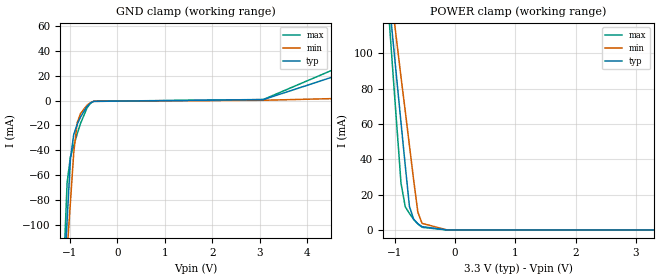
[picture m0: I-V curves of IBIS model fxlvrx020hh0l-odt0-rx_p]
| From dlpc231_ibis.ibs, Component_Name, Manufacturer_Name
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|   Model fxlvrx020hh0l-odt0-rx_p
[Model] fxlvrx020hh0l-odt0-rx_p
Model_type Input
Polarity   Non-Inverting
Vinl =  1.250V
Vinh =  1.250V
C_comp   0.838pF   0.793pF   0.889pF
C_comp_pullup   0.208pF   0.168pF   0.233pF
[Model Spec]
Vinh   1.250V   1.250V   1.250V
Vinl   1.250V   1.250V   1.250V
[Temperature Range]   40.000   0.125k   -40.000
[Voltage Range]   3.300V   2.970V   3.630V
[Pullup Reference]   3.300V   2.970V   3.630V
[Pulldown Reference]   0.0V   0.0V   0.0V
[POWER Clamp Reference]   3.300V   2.970V   3.630V
[GND Clamp Reference]   0.0V   0.0V   0.0V
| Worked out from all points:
|   GND clamp passes 1 mA (typ) near -0.52 V on its own axis
|   POWER clamp passes 1 mA (typ) near -0.49 V on its own axis
[GND_clamp]
|Voltage   I(typ)   I(min)   I(max)
-3.3V     -1.777A    -1.443A    -2.296A
-1.13V    -147.3mA   -160.7mA   -133.1mA
-1.06V    -96.46mA   -121mA     -65.94mA
-990mV    -46.56mA   -81.44mA   -45.11mA
-920mV    -27.23mA   -41.76mA   -36.16mA
-850mV    -19.43mA   -18.17mA   -27.05mA
-780mV    -13.39mA   -10.64mA   -18.6mA
-640mV    -4.604mA   -3.691mA   -5.833mA
-570mV    -2.048mA   -1.757mA   -2.243mA
-500mV    -679.6uA   -643.4uA   -592.3uA
3.07V     723uA      208.1uA    801.7uA
6.58V     44.35mA    3.413mA    57.79mA
[POWER_clamp]
|Voltage   I(typ)   I(min)   I(max)
-3.28V    1.18A      1.008A     1.441A
-1.18V    159.7mA    167.6mA    159.1mA
-1.11V    134.5mA    146.7mA    125.3mA
-1.04V    109.6mA    126.2mA    91.85mA
-900mV    60.75mA    86.59mA    26.55mA
-830mV    36.72mA    67.43mA    13.23mA
-760mV    13.35mA    47.84mA    9.33mA
-690mV    6.049mA    28.33mA    6.066mA
-620mV    3.518mA    10.04mA    3.397mA
-550mV    1.873mA    3.726mA    1.494mA
-130mV    0A         0A         0A
3.3V      0A         0A         0A
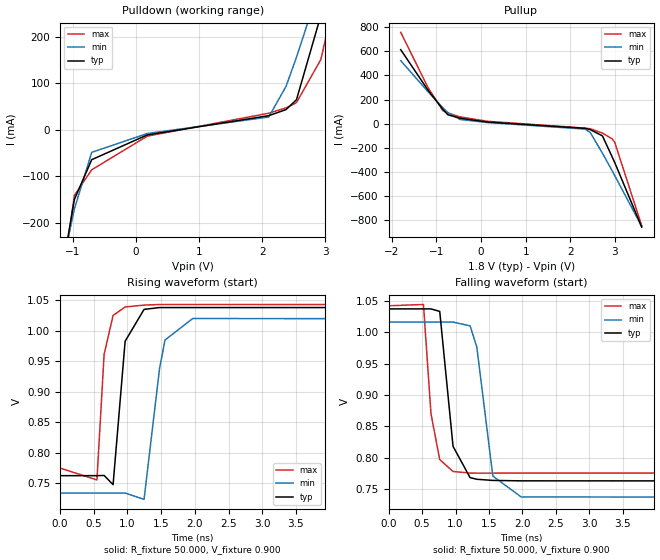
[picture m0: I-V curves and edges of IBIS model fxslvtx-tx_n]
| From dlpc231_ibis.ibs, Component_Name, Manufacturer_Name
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|   Model fxslvtx030hh0l-tx_n
[Model] fxslvtx-tx_n
Model_type Output
Polarity   Inverting
Vmeas =  0.900V
C_comp   4.596pF   4.576pF   4.628pF
C_comp_pullup   0.720pF   0.673pF   0.780pF
C_comp_pulldown   0.529pF   0.517pF   0.543pF
[Model Spec]
Vmeas   0.900V   0.900V   0.900V
[Temperature Range]   40.000   0.125k   -40.000
[Voltage Range]   1.800V   1.620V   1.980V
[Pullup Reference]   1.800V   1.620V   1.980V
[Pulldown Reference]   0.0V   0.0V   0.0V
[POWER Clamp Reference]   1.800V   1.620V   1.980V
[GND Clamp Reference]   0.0V   0.0V   0.0V
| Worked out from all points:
|   slope of the pulldown table from 0 to 0.27 V, typ, clamps not added: 26.4 ohm
|   slope of the pullup table from 0 to 0.27 V, typ, clamps not added: 26.3 ohm
|   rising waveform, R_fixture 50.000, V_fixture 0.900: 20-80 % time 115ps typ, 164ps min, 93.6ps max; typ from 0.763 V to 1.04 V
|   falling waveform, R_fixture 50.000, V_fixture 0.900: 20-80 % time 133ps typ, 178ps min, 123ps max; typ from 1.04 V to 0.763 V
[Pulldown]
|Voltage   I(typ)   I(min)   I(max)
-1.8V     -861.9mA   -731mA     -1.071A
-1.195V   -325.7mA   -310mA     -357.2mA
-975mV    -150.4mA   -170.7mA   -141.6mA
-700mV    -64.49mA   -48.72mA   -86.29mA
180mV     -11.16mA   -8.121mA   -13.74mA
2.105V    30.29mA    27.42mA    35.56mA
2.38V     43.45mA    93.62mA    47.16mA
2.545V    64.78mA    156.3mA    58.49mA
2.93V     245.8mA    316.5mA    151.1mA
3.095V    336.1mA    386mA      248.2mA
3.205V    397mA      432.4mA    324.4mA
3.6V      615.2mA    600.8mA    624mA
[Pullup]
|Voltage   I(typ)   I(min)   I(max)
-1.8V     614.6mA    523.2mA    759mA
-1.185V   275.8mA    263.9mA    296.7mA
-855mV    118.7mA    131.2mA    106.6mA
-745mV    73.55mA    92.03mA    88.76mA
-470mV    44.52mA    34.36mA    55.71mA
135mV     12.86mA    8.96mA     19.38mA
2.335V    -39.86mA   -46.08mA   -37.65mA
2.445V    -49.94mA   -73.94mA   -42.66mA
2.72V     -102.2mA   -245.9mA   -78.84mA
2.94V     -278.6mA   -394mA     -127.7mA
2.995V    -323.5mA   -432.3mA   -155.1mA
3.6V      -861.5mA   -855.2mA   -849.2mA
[Ramp]
| variable   typ   min   max
dV/dt_r   0.165/0.110n   0.169/0.150n   0.160/94.189p
dV/dt_f   0.165/0.143n   0.169/0.203n   0.160/0.123n
R_load = 50.000
[Rising Waveform]
R_fixture= 50.000
V_fixture= 0.900
V_fixture_min= 0.875
V_fixture_max= 0.908
|time   V(typ)   V(min)   V(max)
0s        762.5mV    734mV      774.9mV
546ps     762.5mV    734mV      755.5mV
653ps     762.8mV    734mV      961.4mV
786ps     747.7mV    734mV      1.025V
965ps     982.8mV    734mV      1.039V
1.246ns   1.035V     723.7mV    1.042V
1.476ns   1.038V     938.2mV    1.043V
1.557ns   1.038V     984.7mV    1.043V
1.968ns   1.038V     1.02V      1.043V
50ns      1.037V     1.016V     1.042V
[Falling Waveform]
R_fixture= 50.000
V_fixture= 0.900
V_fixture_min= 0.875
V_fixture_max= 0.908
|time   V(typ)   V(min)   V(max)
0s        1.037V     1.016V     1.042V
520ps     1.037V     1.016V     1.044V
632ps     1.037V     1.016V     870.4mV
763ps     1.033V     1.016V     797.2mV
962ps     818.3mV    1.016V     778.3mV
1.217ns   768.5mV    1.01V      775.8mV
1.317ns   765.9mV    976.4mV    775.7mV
1.557ns   764.1mV    770.9mV    775.7mV
1.981ns   763.4mV    737.8mV    775.8mV
50ns      762.5mV    734mV      774.9mV
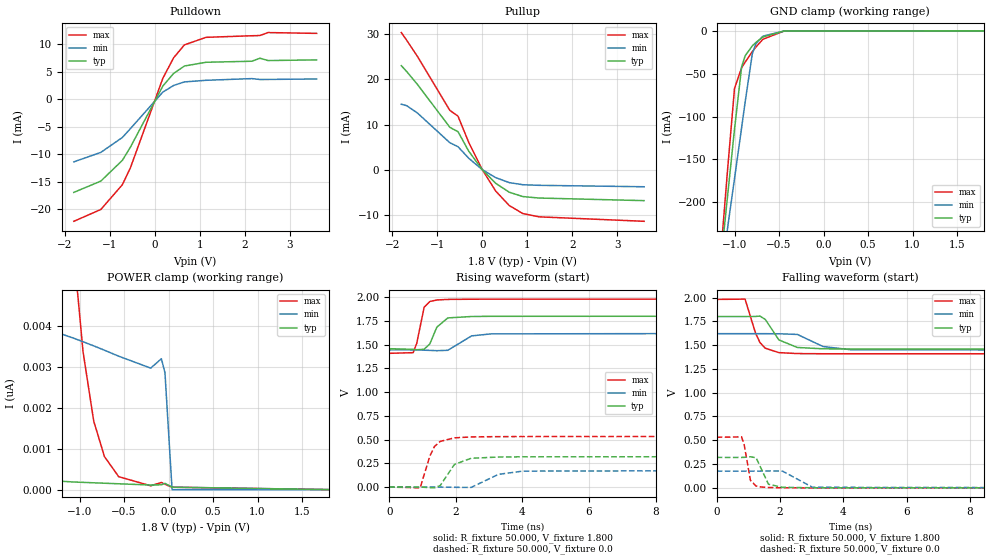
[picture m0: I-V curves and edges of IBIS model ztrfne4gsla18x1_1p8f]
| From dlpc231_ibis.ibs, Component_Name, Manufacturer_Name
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[Model] ztrfne4gsla18x1_1p8f
Model_type I/O
Polarity   Non-Inverting
Enable   Active-High
Vinl =  0.540V
Vinh =  1.260V
Vref = 0.000V
Rref = 0.50k
Cref = 50.00pF
Vmeas = 0.90V
C_comp   2.109pF   2.101pF   2.161pF
C_comp_pullup   0.472pF   0.454pF   0.586pF
C_comp_pulldown   0.472pF   0.454pF   0.586pF
[Temperature Range]   25.000   0.125k   -40.000
[Voltage Range]   1.800V   1.620V   1.980V
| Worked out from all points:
|   slope of the pulldown table from 0 to 0.27 V, typ, clamps not added: 79.5 ohm
|   slope of the pullup table from 0 to 0.27 V, typ, clamps not added: 97.1 ohm
|   GND clamp passes 1 mA (typ) near -0.53 V on its own axis
|   rising waveform, R_fixture 50.000, V_fixture 1.800: 20-80 % time 252ps typ, 379ps min, 183ps max; typ from 1.46 V to 1.8 V
|   rising waveform, R_fixture 50.000, V_fixture 0.0: 20-80 % time 403ps typ, 628ps min, 300ps max; typ from 0 V to 0.32 V
|   falling waveform, R_fixture 50.000, V_fixture 1.800: 20-80 % time 461ps typ, 702ps min, 338ps max; typ from 1.8 V to 1.46 V
|   falling waveform, R_fixture 50.000, V_fixture 0.0: 20-80 % time 230ps typ, 353ps min, 156ps max; typ from 0.32 V to 0 V
[Pulldown]
-1.8V     -16.95mA   -11.39mA   -22.22mA
-1.2V     -14.9mA    -9.67mA    -20.07mA
-720mV    -11.11mA   -6.946mA   -15.55mA
-540mV    -8.689mA   -5.327mA   -12.44mA
180mV     2.424mA    1.317mA    3.83mA
420mV     4.723mA    2.526mA    7.576mA
660mV     6.065mA    3.174mA    9.921mA
1.14V     6.75mA     3.464mA    11.29mA
2.16V     6.938mA    3.775mA    11.58mA
2.34V     7.486mA    3.611mA    11.62mA
2.52V     7.061mA    3.621mA    12.16mA
3.6V      7.184mA    3.708mA    12.01mA
[Pullup]
-1.8V     23.05mA    14.5mA     30.39mA
-1.68V    21.74mA    14.18mA    28.68mA
-1.44V    18.87mA    12.54mA    25.07mA
-720mV    9.367mA    5.957mA    13.13mA
-540mV    8.432mA    5.089mA    11.86mA
-300mV    4.077mA    2.52mA     6.027mA
0V        10.36pA    166.7pA    4.435pA
300mV     -3.041mA   -1.773mA   -4.761mA
600mV     -5mA       -2.872mA   -7.949mA
900mV     -5.961mA   -3.338mA   -9.725mA
1.26V     -6.291mA   -3.475mA   -10.46mA
3.6V      -6.87mA    -3.792mA   -11.45mA
[GND_clamp]
-1.8V     -927mA     -775.7mA   -1.101A
-1.16V    -275.3mA   -291.3mA   -268.1mA
-1.12V    -235.1mA   -261.5mA   -216.5mA
-1.08V    -194.9mA   -231.7mA   -164.9mA
-1V       -114.9mA   -172.5mA   -67.23mA
-920mV    -41.99mA   -112.9mA   -43.08mA
-880mV    -29.06mA   -82.77mA   -36.47mA
-800mV    -17.56mA   -26.87mA   -24.31mA
-760mV    -13.55mA   -15.08mA   -18.89mA
-680mV    -7.158mA   -6.178mA   -9.822mA
-440mV    -133.7uA   -176.5uA   -112.6uA
1.8V      0A         0A         0A
[POWER_clamp]
-1.8V     288.6pA    4.231nA    140.6nA
-1.08V    187.2pA    3.703nA    6.484nA
-1.04V    183.6pA    3.671nA    5.234nA
-960mV    176.5pA    3.605nA    3.359nA
-840mV    166pA      3.504nA    1.668nA
-720mV    155.7pA    3.399nA    806.1pA
-560mV    142pA      3.253nA    315.8pA
-200mV    111.6pA    2.962nA    92.54pA
-80mV     117.3pA    3.191nA    175.1pA
-40mV     151.6pA    2.851nA    129.2pA
40mV      60.08pA    0A         58.67pA
1.8V      0A         0A         0A
[Ramp]
dV/dt_r   0.192/0.402n   0.106/0.635n   0.319/0.301n
dV/dt_f   0.205/0.462n   0.105/0.700n   0.343/0.338n
R_load = 50.000
[Rising Waveform]
R_fixture= 50.000
V_fixture= 1.800
V_fixture_min= 1.620
V_fixture_max= 1.980
0s        1.458V     1.445V     1.409V
719ps     1.451V     1.445V     1.416V
829ps     1.447V     1.445V     1.516V
1.049ns   1.452V     1.442V     1.895V
1.22ns    1.508V     1.44V      1.955V
1.431ns   1.685V     1.437V     1.971V
1.761ns   1.782V     1.441V     1.977V
2.476ns   1.797V     1.593V     1.979V
3.066ns   1.799V     1.614V     1.98V
15ns      1.8V       1.62V      1.98V
[Rising Waveform]
R_fixture= 50.000
V_fixture= 0.0
V_fixture_min= 0.0
V_fixture_max= 0.0
0s        0V         0V         0V
930ps     -62.39uV   300.9uV    -8.214mV
1.22ns    -5.677mV   323.3uV    325.7mV
1.359ns   -8.367mV   274.3uV    427.2mV
1.531ns   15.77mV    79.15uV    481.1mV
1.96ns    238.9mV    -2.756mV   518.4mV
2.461ns   303.3mV    -3.894mV   528.2mV
3.281ns   316.4mV    133.8mV    531.5mV
4.01ns    318.9mV    168mV      531.9mV
15ns      320mV      176.1mV    532mV
[Falling Waveform]
R_fixture= 50.000
V_fixture= 1.800
V_fixture_min= 1.620
V_fixture_max= 1.980
0s        1.8V       1.62V      1.98V
896ps     1.8V       1.62V      1.983V
1.224ns   1.801V     1.62V      1.628V
1.364ns   1.805V     1.62V      1.528V
1.534ns   1.77V      1.62V      1.467V
1.965ns   1.554V     1.619V     1.421V
2.548ns   1.475V     1.612V     1.411V
3.358ns   1.461V     1.485V     1.409V
4.217ns   1.459V     1.452V     1.409V
15ns      1.458V     1.445V     1.409V
[Falling Waveform]
R_fixture= 50.000
V_fixture= 0.0
V_fixture_min= 0.0
V_fixture_max= 0.0
0s        320mV      176.1mV    532mV
785ps     319.9mV    176.1mV    535.5mV
866ps     320.4mV    176.1mV    458.1mV
1.066ns   326.6mV    176mV      79.15mV
1.244ns   316.4mV    176mV      18.67mV
1.394ns   209.6mV    176.2mV    9.401mV
1.635ns   38.02mV    177.8mV    3.778mV
2.076ns   6.113mV    176.3mV    834.5uV
3.028ns   788.1uV    6.018mV    40.72uV
15ns      0V         0V         0V
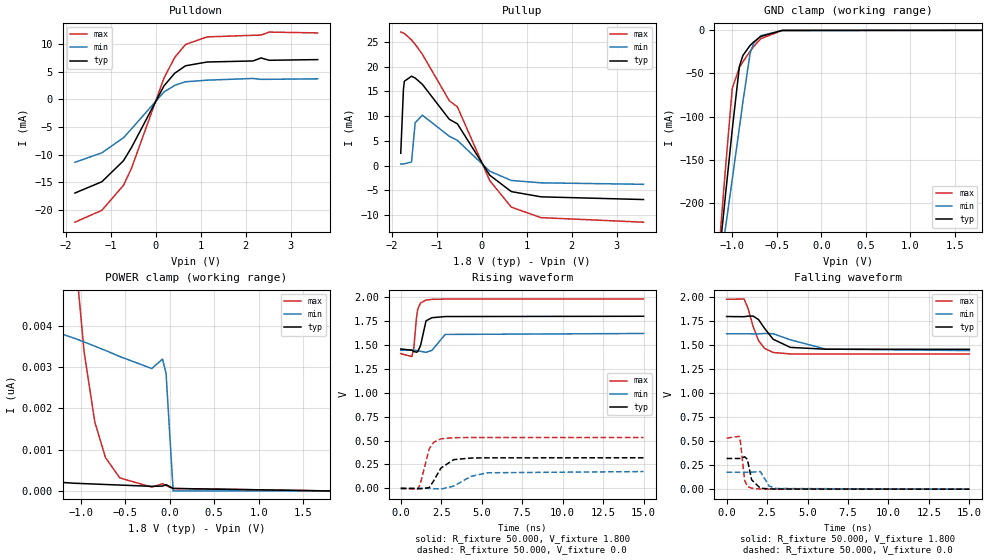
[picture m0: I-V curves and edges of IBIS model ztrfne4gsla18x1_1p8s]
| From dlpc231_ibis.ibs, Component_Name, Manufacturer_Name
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| Model ztrfne4gsla18x1_1p8s
[Model] ztrfne4gsla18x1_1p8s
Model_type I/O
Polarity   Non-Inverting
Enable   Active-High
Vinl =  0.540V
Vinh =  1.260V
Vref = 0.000V
Rref = 0.50k
Cref = 50.00pF
Vmeas = 0.90V
C_comp   2.095pF   2.092pF   2.148pF
C_comp_pullup   0.469pF   0.448pF   0.594pF
C_comp_pulldown   0.469pF   0.448pF   0.594pF
[Temperature Range]   25.000   0.125k   -40.000
[Voltage Range]   1.800V   1.620V   1.980V
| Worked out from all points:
|   slope of the pulldown table from 0 to 0.27 V, typ, clamps not added: 79.5 ohm
|   slope of the pullup table from 0 to 0.27 V, typ, clamps not added: 97.1 ohm
|   GND clamp passes 1 mA (typ) near -0.53 V on its own axis
|   rising waveform, R_fixture 50.000, V_fixture 1.800: 20-80 % time 240ps typ, 347ps min, 196ps max; typ from 1.46 V to 1.8 V
|   rising waveform, R_fixture 50.000, V_fixture 0.0: 20-80 % time 734ps typ, 1.24ns min, 504ps max; typ from 0 V to 0.32 V
|   falling waveform, R_fixture 50.000, V_fixture 1.800: 20-80 % time 1.02ns typ, 1.64ns min, 706ps max; typ from 1.8 V to 1.46 V
|   falling waveform, R_fixture 50.000, V_fixture 0.0: 20-80 % time 253ps typ, 354ps min, 201ps max; typ from 0.32 V to 0 V
[Pulldown]
-1.8V     -16.95mA   -11.39mA   -22.22mA
-1.2V     -14.9mA    -9.67mA    -20.07mA
-720mV    -11.11mA   -6.946mA   -15.55mA
-540mV    -8.689mA   -5.327mA   -12.44mA
180mV     2.424mA    1.317mA    3.83mA
420mV     4.723mA    2.526mA    7.576mA
660mV     6.065mA    3.174mA    9.921mA
1.14V     6.75mA     3.464mA    11.29mA
2.16V     6.938mA    3.775mA    11.58mA
2.34V     7.486mA    3.611mA    11.62mA
2.52V     7.061mA    3.621mA    12.16mA
3.6V      7.184mA    3.708mA    12.01mA
[Pullup]
-1.8V     2.484mA    326.4uA    26.98mA
-1.74V    15.41mA    339.3uA    26.8mA
-1.72V    17.04mA    346.2uA    26.7mA
-1.56V    18.06mA    719.8uA    25.39mA
-1.48V    17.7mA     8.623mA    24.52mA
-1.32V    16.43mA    10.18mA    22.51mA
-720mV    9.35mA     5.922mA    13.11mA
-540mV    8.432mA    5.089mA    11.86mA
180mV     -1.959mA   -1.146mA   -3.055mA
660mV     -5.269mA   -3.014mA   -8.412mA
1.32V     -6.324mA   -3.492mA   -10.53mA
3.6V      -6.87mA    -3.792mA   -11.45mA
[GND_clamp]
-1.8V     -927mA     -775.7mA   -1.101A
-1.16V    -275.3mA   -291.3mA   -268.1mA
-1.12V    -235.1mA   -261.5mA   -216.5mA
-1.08V    -194.9mA   -231.7mA   -164.9mA
-1V       -114.9mA   -172.5mA   -67.23mA
-920mV    -41.99mA   -112.9mA   -43.08mA
-880mV    -29.06mA   -82.77mA   -36.47mA
-800mV    -17.56mA   -26.87mA   -24.31mA
-760mV    -13.55mA   -15.08mA   -18.89mA
-680mV    -7.158mA   -6.178mA   -9.822mA
-440mV    -133.7uA   -176.5uA   -112.6uA
1.8V      0A         0A         0A
[POWER_clamp]
-1.8V     288.6pA    4.231nA    140.6nA
-1.08V    187.2pA    3.703nA    6.484nA
-1.04V    183.6pA    3.671nA    5.234nA
-960mV    176.5pA    3.605nA    3.359nA
-840mV    166pA      3.504nA    1.668nA
-720mV    155.7pA    3.399nA    806.1pA
-560mV    142pA      3.253nA    315.8pA
-200mV    111.6pA    2.962nA    92.54pA
-80mV     117.3pA    3.191nA    175.1pA
-40mV     151.6pA    2.851nA    129.2pA
40mV      60.08pA    0A         58.67pA
1.8V      0A         0A         0A
[Ramp]
dV/dt_r   0.192/0.733n   0.106/1.235n   0.319/0.505n
dV/dt_f   0.205/1.024n   0.105/1.646n   0.343/0.716n
R_load = 50.000
[Rising Waveform]
R_fixture= 50.000
V_fixture= 1.800
V_fixture_min= 1.620
V_fixture_max= 1.980
0s        1.458V     1.445V     1.409V
689ps     1.445V     1.446V     1.379V
810ps     1.433V     1.445V     1.472V
971ps     1.424V     1.442V     1.784V
1.051ns   1.431V     1.44V      1.875V
1.221ns   1.493V     1.434V     1.939V
1.561ns   1.752V     1.423V     1.969V
1.925ns   1.785V     1.443V     1.977V
2.746ns   1.797V     1.61V      1.98V
15ns      1.8V       1.62V      1.98V
[Rising Waveform]
R_fixture= 50.000
V_fixture= 0.0
V_fixture_min= 0.0
V_fixture_max= 0.0
0s        0V         0V         0V
1.07ns    -1.24mV    473.8uV    -8.116mV
1.2ns     -3.926mV   490.6uV    43.61mV
1.761ns   7.701mV    -536.2uV   413.9mV
2.04ns    80.74mV    -2.825mV   482.6mV
2.481ns   212.5mV    -6.943mV   518.4mV
3.276ns   300.8mV    24.34mV    530.3mV
4.346ns   317.5mV    126.1mV    531.9mV
5.366ns   319.6mV    163.2mV    532mV
15ns      320mV      176.1mV    532mV
[Falling Waveform]
R_fixture= 50.000
V_fixture= 1.800
V_fixture_min= 1.620
V_fixture_max= 1.980
0s        1.8V       1.62V      1.98V
1.085ns   1.798V     1.62V      1.982V
1.325ns   1.804V     1.62V      1.885V
1.636ns   1.805V     1.619V     1.697V
1.976ns   1.768V     1.619V     1.549V
2.336ns   1.679V     1.623V     1.469V
2.876ns   1.563V     1.621V     1.425V
3.944ns   1.478V     1.557V     1.41V
6.137ns   1.459V     1.46V      1.409V
15ns      1.458V     1.445V     1.409V
[Falling Waveform]
R_fixture= 50.000
V_fixture= 0.0
V_fixture_min= 0.0
V_fixture_max= 0.0
0s        320mV      176.1mV    532mV
786ps     319.7mV    176.1mV    551.6mV
856ps     320.3mV    176mV      491.5mV
1.116ns   337.7mV    175.9mV    91.16mV
1.284ns   311.5mV    175.9mV    29.33mV
1.548ns   97.14mV    177.3mV    9.31mV
2.088ns   9.682mV    183.3mV    1.632mV
2.618ns   3.218mV    33.57mV    353.7uV
3.054ns   1.41mV     6.768mV    104.6uV
15ns      0V         0V         0V
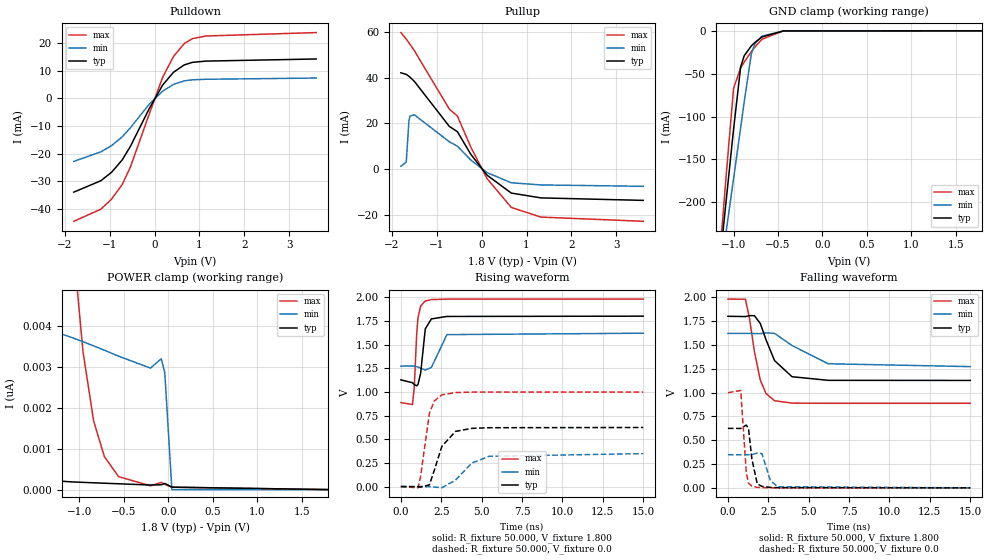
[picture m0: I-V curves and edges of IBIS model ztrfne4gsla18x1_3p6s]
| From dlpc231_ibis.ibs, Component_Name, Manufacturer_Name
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| Model ztrfne4gsla18x1_3p6s
[Model] ztrfne4gsla18x1_3p6s
Model_type I/O
Polarity   Non-Inverting
Enable   Active-High
Vinl =  0.540V
Vinh =  1.260V
Vref = 0.000V
Rref = 0.50k
Cref = 50.00pF
Vmeas = 0.90V
C_comp   2.197pF   2.186pF   2.249pF
C_comp_pullup   0.537pF   0.484pF   0.701pF
C_comp_pulldown   0.537pF   0.484pF   0.701pF
[Temperature Range]   25.000   0.125k   -40.000
[Voltage Range]   1.800V   1.620V   1.980V
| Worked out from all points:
|   slope of the pulldown table from 0 to 0.27 V, typ, clamps not added: 39.8 ohm
|   slope of the pullup table from 0 to 0.27 V, typ, clamps not added: 48.5 ohm
|   GND clamp passes 1 mA (typ) near -0.53 V on its own axis
|   rising waveform, R_fixture 50.000, V_fixture 1.800: 20-80 % time 240ps typ, 349ps min, 194ps max; typ from 1.13 V to 1.8 V
|   rising waveform, R_fixture 50.000, V_fixture 0.0: 20-80 % time 786ps typ, 1.31ns min, 520ps max; typ from 0 V to 0.624 V
|   falling waveform, R_fixture 50.000, V_fixture 1.800: 20-80 % time 1.04ns typ, 1.68ns min, 699ps max; typ from 1.8 V to 1.13 V
|   falling waveform, R_fixture 50.000, V_fixture 0.0: 20-80 % time 271ps typ, 377ps min, 211ps max; typ from 0.624 V to 0 V
[Pulldown]
-1.8V     -33.89mA   -22.78mA   -44.44mA
-1.2V     -29.79mA   -19.34mA   -40.09mA
-960mV    -26.74mA   -17.1mA    -36.45mA
-720mV    -22.21mA   -13.88mA   -31.07mA
-540mV    -17.37mA   -10.64mA   -24.87mA
-120mV    -3.725mA   -2.11mA    -5.686mA
180mV     4.844mA    2.631mA    7.654mA
420mV     9.436mA    5.045mA    15.14mA
660mV     12.11mA    6.338mA    19.82mA
840mV     13.02mA    6.716mA    21.6mA
1.14V     13.48mA    6.915mA    22.56mA
3.6V      14.25mA    7.361mA    23.8mA
[Pullup]
-1.8V     42.07mA    1.185mA    59.67mA
-1.68V    41.39mA    2.996mA    56.77mA
-1.62V    40.54mA    21.06mA    55.18mA
-1.6V     40.21mA    23.09mA    54.64mA
-1.5V     38.34mA    23.7mA     51.81mA
-720mV    18.62mA    11.91mA    26.16mA
-540mV    16.3mA     9.959mA    23.16mA
-240mV    6.367mA    3.893mA    9.494mA
120mV     -2.703mA   -1.584mA   -4.209mA
660mV     -10.54mA   -6.029mA   -16.83mA
1.32V     -12.65mA   -6.984mA   -21.05mA
3.6V      -13.74mA   -7.586mA   -22.89mA
[GND_clamp]
-1.8V     -927mA     -775.7mA   -1.101A
-1.16V    -275.3mA   -291.3mA   -268.1mA
-1.12V    -235.1mA   -261.5mA   -216.5mA
-1.08V    -194.9mA   -231.7mA   -164.9mA
-1V       -114.9mA   -172.5mA   -67.23mA
-920mV    -41.99mA   -112.9mA   -43.08mA
-880mV    -29.06mA   -82.77mA   -36.47mA
-800mV    -17.56mA   -26.87mA   -24.31mA
-760mV    -13.55mA   -15.08mA   -18.89mA
-680mV    -7.158mA   -6.178mA   -9.822mA
-440mV    -133.7uA   -176.5uA   -112.6uA
1.8V      0A         0A         0A
[POWER_clamp]
-1.8V     288.6pA    4.231nA    140.6nA
-1.08V    187.2pA    3.703nA    6.484nA
-1.04V    183.6pA    3.671nA    5.234nA
-960mV    176.5pA    3.605nA    3.359nA
-840mV    166pA      3.504nA    1.668nA
-720mV    155.7pA    3.399nA    806.1pA
-560mV    142pA      3.253nA    315.8pA
-200mV    111.6pA    2.962nA    92.54pA
-80mV     117.3pA    3.191nA    175.1pA
-40mV     151.6pA    2.851nA    129.2pA
40mV      60.08pA    0A         58.67pA
1.8V      0A         0A         0A
[Ramp]
dV/dt_r   0.374/0.786n   0.209/1.315n   0.599/0.525n
dV/dt_f   0.404/1.054n   0.209/1.684n   0.656/0.704n
R_load = 50.000
[Rising Waveform]
R_fixture= 50.000
V_fixture= 1.800
V_fixture_min= 1.620
V_fixture_max= 1.980
0s        1.127V     1.272V     886.8mV
719ps     1.097V     1.274V     866.4mV
829ps     1.077V     1.273V     1.044V
980ps     1.064V     1.267V     1.615V
1.06ns    1.078V     1.262V     1.785V
1.227ns   1.2V       1.25V      1.907V
1.511ns   1.666V     1.231V     1.961V
1.889ns   1.771V     1.258V     1.975V
2.851ns   1.797V     1.605V     1.98V
15ns      1.8V       1.62V      1.98V
[Rising Waveform]
R_fixture= 50.000
V_fixture= 0.0
V_fixture_min= 0.0
V_fixture_max= 0.0
0s        0V         0V         0V
1.069ns   -1.973mV   754.7uV    -13.93mV
1.21ns    -6.548mV   767.8uV    96.37mV
1.769ns   18.15mV    -983.2uV   774.5mV
2.069ns   172mV      -5.19mV    903.6mV
2.54ns    425.4mV    -12.79mV   969.1mV
3.38ns    582.4mV    67.33mV    993.3mV
4.396ns   614.7mV    248.5mV    997.7mV
5.466ns   621.5mV    319.8mV    998.6mV
15ns      623.9mV    347.9mV    998.7mV
[Falling Waveform]
R_fixture= 50.000
V_fixture= 1.800
V_fixture_min= 1.620
V_fixture_max= 1.980
0s        1.8V       1.62V      1.98V
1.085ns   1.797V     1.62V      1.979V
1.335ns   1.807V     1.62V      1.779V
1.644ns   1.806V     1.619V     1.426V
2.006ns   1.724V     1.618V     1.13V
2.354ns   1.556V     1.626V     991.1mV
2.888ns   1.335V     1.621V     914.3mV
3.968ns   1.166V     1.493V     888.9mV
6.208ns   1.128V     1.302V     887mV
15ns      1.127V     1.272V     886.8mV
[Falling Waveform]
R_fixture= 50.000
V_fixture= 0.0
V_fixture_min= 0.0
V_fixture_max= 0.0
0s        623.9mV    347.9mV    998.7mV
795ps     623.4mV    347.8mV    1.022V
1.136ns   658.8mV    347.4mV    163.4mV
1.276ns   620mV      347.4mV    49.4mV
1.484ns   304.3mV    348.7mV    17.99mV
1.814ns   42.55mV    364.8mV    5.362mV
2.107ns   15.25mV    359.1mV    2.102mV
2.627ns   4.855mV    76.61mV    455.8uV
3.087ns   2.001mV    12.32mV    124.7uV
15ns      0V         0V         0V
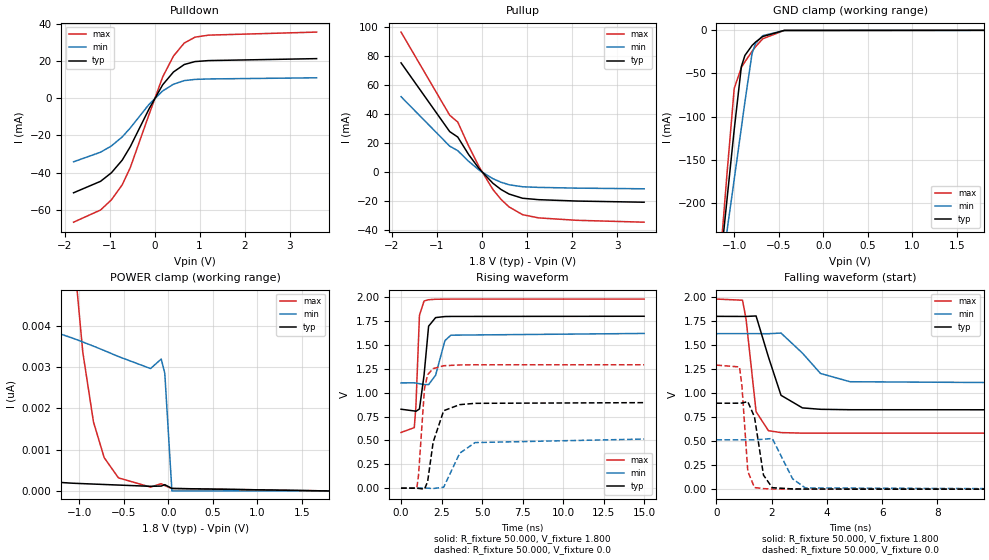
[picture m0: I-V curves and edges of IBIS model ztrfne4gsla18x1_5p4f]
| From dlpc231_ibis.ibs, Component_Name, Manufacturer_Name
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| Model ztrfne4gsla18x1_5p4f
[Model] ztrfne4gsla18x1_5p4f
Model_type I/O
Polarity   Non-Inverting
Enable   Active-High
Vinl =  0.540V
Vinh =  1.260V
Vref = 0.000V
Rref = 0.50k
Cref = 50.00pF
Vmeas = 0.90V
C_comp   2.335pF   2.280pF   2.446pF
C_comp_pullup   0.619pF   0.537pF   0.802pF
C_comp_pulldown   0.619pF   0.537pF   0.802pF
[Temperature Range]   25.000   0.125k   -40.000
[Voltage Range]   1.800V   1.620V   1.980V
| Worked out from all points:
|   slope of the pulldown table from 0 to 0.27 V, typ, clamps not added: 26.5 ohm
|   slope of the pullup table from 0 to 0.27 V, typ, clamps not added: 32.4 ohm
|   GND clamp passes 1 mA (typ) near -0.53 V on its own axis
|   rising waveform, R_fixture 50.000, V_fixture 1.800: 20-80 % time 293ps typ, 469ps min, 181ps max; typ from 0.827 V to 1.8 V
|   rising waveform, R_fixture 50.000, V_fixture 0.0: 20-80 % time 559ps typ, 910ps min, 318ps max; typ from 0 V to 0.895 V
|   falling waveform, R_fixture 50.000, V_fixture 1.800: 20-80 % time 531ps typ, 859ps min, 301ps max; typ from 1.8 V to 0.827 V
|   falling waveform, R_fixture 50.000, V_fixture 0.0: 20-80 % time 278ps typ, 454ps min, 174ps max; typ from 0.895 V to 0 V
[Pulldown]
-1.8V     -50.83mA   -34.16mA   -66.65mA
-1.2V     -44.66mA   -29mA      -60.09mA
-960mV    -40.09mA   -25.65mA   -54.65mA
-720mV    -33.3mA    -20.81mA   -46.59mA
-540mV    -26.05mA   -15.97mA   -37.31mA
-120mV    -5.589mA   -3.166mA   -8.53mA
180mV     7.268mA    3.947mA    11.48mA
420mV     14.16mA    7.57mA     22.72mA
660mV     18.18mA    9.512mA    29.74mA
900mV     19.76mA    10.17mA    32.9mA
1.2V      20.29mA    10.41mA    33.98mA
3.6V      21.34mA    11.03mA    35.62mA
[Pullup]
-1.8V     75.13mA    51.91mA    96.29mA
-720mV    27.93mA    17.95mA    39.19mA
-540mV    24.16mA    14.81mA    34.44mA
-300mV    12.23mA    7.543mA    18.07mA
-60mV     2.221mA    1.318mA    3.411mA
240mV     -7.567mA   -4.42mA    -11.82mA
420mV     -11.85mA   -6.876mA   -18.65mA
600mV     -15mA      -8.618mA   -23.85mA
900mV     -17.89mA   -10.01mA   -29.18mA
1.26V     -18.87mA   -10.43mA   -31.39mA
2.1V      -19.81mA   -10.93mA   -33.04mA
3.6V      -20.62mA   -11.39mA   -34.34mA
[GND_clamp]
-1.8V     -927mA     -775.7mA   -1.101A
-1.16V    -275.3mA   -291.3mA   -268.1mA
-1.12V    -235.1mA   -261.5mA   -216.5mA
-1.08V    -194.9mA   -231.7mA   -164.9mA
-1V       -114.9mA   -172.5mA   -67.23mA
-920mV    -41.99mA   -112.9mA   -43.08mA
-880mV    -29.06mA   -82.77mA   -36.47mA
-800mV    -17.56mA   -26.87mA   -24.31mA
-760mV    -13.55mA   -15.08mA   -18.89mA
-680mV    -7.158mA   -6.178mA   -9.822mA
-440mV    -133.7uA   -176.5uA   -112.6uA
1.8V      0A         0A         0A
[POWER_clamp]
-1.8V     288.6pA    4.231nA    140.6nA
-1.08V    187.2pA    3.703nA    6.484nA
-1.04V    183.6pA    3.671nA    5.234nA
-960mV    176.5pA    3.605nA    3.359nA
-840mV    166pA      3.504nA    1.668nA
-720mV    155.7pA    3.399nA    806.1pA
-560mV    142pA      3.253nA    315.8pA
-200mV    111.6pA    2.962nA    92.54pA
-80mV     117.3pA    3.191nA    175.1pA
-40mV     151.6pA    2.851nA    129.2pA
40mV      60.08pA    0A         58.67pA
1.8V      0A         0A         0A
[Ramp]
dV/dt_r   0.537/0.564n   0.309/0.916n   0.775/0.317n
dV/dt_f   0.584/0.538n   0.311/0.856n   0.838/0.303n
R_load = 50.000
[Rising Waveform]
R_fixture= 50.000
V_fixture= 1.800
V_fixture_min= 1.620
V_fixture_max= 1.980
0s        826.5mV    1.102V     583.2mV
816ps     808.6mV    1.103V     634mV
916ps     804.5mV    1.1V       854.1mV
1.136ns   829.5mV    1.094V     1.81V
1.421ns   1.186V     1.085V     1.96V
1.7ns     1.696V     1.084V     1.973V
2.134ns   1.786V     1.183V     1.978V
2.704ns   1.797V     1.544V     1.979V
3.074ns   1.798V     1.602V     1.98V
15ns      1.8V       1.62V      1.98V
[Rising Waveform]
R_fixture= 50.000
V_fixture= 0.0
V_fixture_min= 0.0
V_fixture_max= 0.0
0s        0V         0V         0V
976ps     -471.2uV   457.5uV    3.982mV
1.076ns   -2.154mV   472.2uV    131.3mV
1.446ns   -10.41mV   304.4uV    1.044V
1.64ns    68.35mV    -232.8uV   1.188V
1.981ns   481.8mV    -3.86mV    1.252V
2.63ns    811.1mV    9.891mV    1.282V
3.62ns    874.6mV    366mV      1.29V
4.57ns    888.3mV    477.5mV    1.292V
15ns      895.4mV    514.2mV    1.292V
[Falling Waveform]
R_fixture= 50.000
V_fixture= 1.800
V_fixture_min= 1.620
V_fixture_max= 1.980
0s        1.8V       1.62V      1.98V
946ps     1.799V     1.62V      1.968V
1.075ns   1.799V     1.62V      1.767V
1.436ns   1.804V     1.62V      806.6mV
1.884ns   1.376V     1.619V     609.1mV
2.338ns   977.8mV    1.626V     589.2mV
3.114ns   846.5mV    1.417V     583.6mV
3.768ns   831.7mV    1.205V     583.2mV
4.838ns   827.4mV    1.119V     583.2mV
15ns      826.5mV    1.102V     583.2mV
[Falling Waveform]
R_fixture= 50.000
V_fixture= 0.0
V_fixture_min= 0.0
V_fixture_max= 0.0
0s        895.4mV    514.2mV    1.292V
836ps     895.6mV    514.1mV    1.273V
926ps     897.6mV    514.1mV    1.068V
1.136ns   911.8mV    514mV      186mV
1.379ns   752mV      514.2mV    16.7mV
1.704ns   146.5mV    519.9mV    5.628mV
2.022ns   15.38mV    528.2mV    1.874mV
2.758ns   2.848mV    107.9mV    173.4uV
3.218ns   1.18mV     12.96mV    42.04uV
15ns      0V         0V         0V
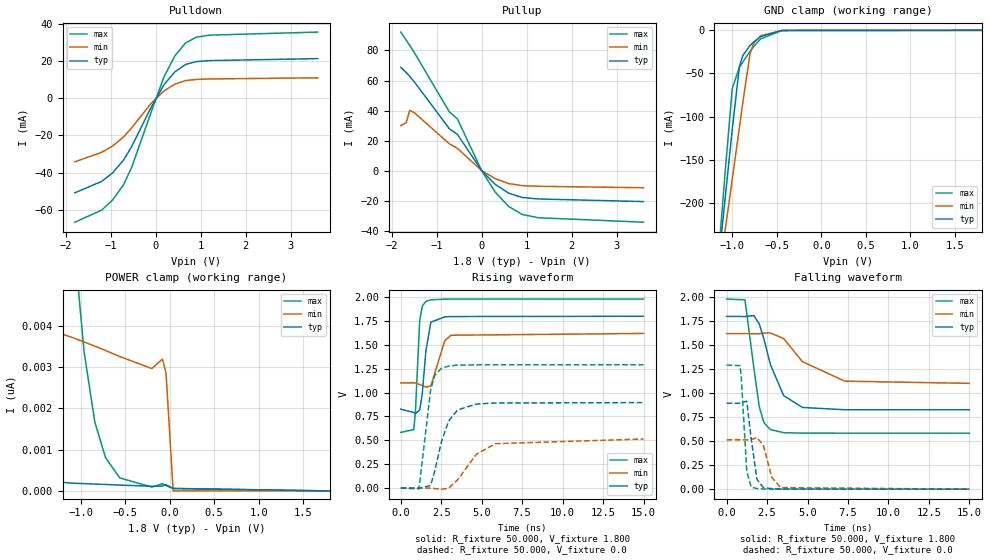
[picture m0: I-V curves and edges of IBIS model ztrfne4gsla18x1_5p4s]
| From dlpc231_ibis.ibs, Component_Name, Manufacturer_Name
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| Model ztrfne4gsla18x1_5p4s
[Model] ztrfne4gsla18x1_5p4s
Model_type I/O
Polarity   Non-Inverting
Enable   Active-High
Vinl =  0.540V
Vinh =  1.260V
Vref = 0.000V
Rref = 0.50k
Cref = 50.00pF
Vmeas = 0.90V
C_comp   2.281pF   2.243pF   2.413pF
C_comp_pullup   0.604pF   0.518pF   0.816pF
C_comp_pulldown   0.604pF   0.518pF   0.816pF
[Temperature Range]   25.000   0.125k   -40.000
[Voltage Range]   1.800V   1.620V   1.980V
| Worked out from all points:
|   slope of the pulldown table from 0 to 0.27 V, typ, clamps not added: 26.5 ohm
|   slope of the pullup table from 0 to 0.27 V, typ, clamps not added: 32.4 ohm
|   GND clamp passes 1 mA (typ) near -0.53 V on its own axis
|   rising waveform, R_fixture 50.000, V_fixture 1.800: 20-80 % time 302ps typ, 456ps min, 218ps max; typ from 0.827 V to 1.8 V
|   rising waveform, R_fixture 50.000, V_fixture 0.0: 20-80 % time 900ps typ, 1.53ns min, 508ps max; typ from 0 V to 0.895 V
|   falling waveform, R_fixture 50.000, V_fixture 1.800: 20-80 % time 1.1ns typ, 1.83ns min, 621ps max; typ from 1.8 V to 0.827 V
|   falling waveform, R_fixture 50.000, V_fixture 0.0: 20-80 % time 361ps typ, 513ps min, 259ps max; typ from 0.895 V to 0 V
[Pulldown]
-1.8V     -50.83mA   -34.16mA   -66.65mA
-1.2V     -44.66mA   -29mA      -60.09mA
-960mV    -40.09mA   -25.65mA   -54.65mA
-720mV    -33.3mA    -20.81mA   -46.59mA
-540mV    -26.05mA   -15.97mA   -37.31mA
-120mV    -5.589mA   -3.166mA   -8.53mA
180mV     7.268mA    3.947mA    11.48mA
420mV     14.16mA    7.57mA     22.72mA
660mV     18.18mA    9.512mA    29.74mA
900mV     19.76mA    10.17mA    32.9mA
1.2V      20.29mA    10.41mA    33.98mA
3.6V      21.34mA    11.03mA    35.62mA
[Pullup]
-1.8V     68.72mA    29.98mA    92.25mA
-1.68V    65.4mA     31.9mA     86.99mA
-1.6V     62.76mA    40.08mA    83.35mA
-1.5V     59.2mA     38.62mA    78.68mA
-720mV    27.89mA    17.89mA    39.16mA
-540mV    24.16mA    14.81mA    34.44mA
0V        10.36pA    166.7pA    4.435pA
300mV     -9.124mA   -5.319mA   -14.29mA
600mV     -15mA      -8.618mA   -23.85mA
900mV     -17.89mA   -10.01mA   -29.18mA
1.26V     -18.87mA   -10.43mA   -31.39mA
3.6V      -20.62mA   -11.39mA   -34.34mA
[GND_clamp]
-1.8V     -927mA     -775.7mA   -1.101A
-1.16V    -275.3mA   -291.3mA   -268.1mA
-1.12V    -235.1mA   -261.5mA   -216.5mA
-1.08V    -194.9mA   -231.7mA   -164.9mA
-1V       -114.9mA   -172.5mA   -67.23mA
-920mV    -41.99mA   -112.9mA   -43.08mA
-880mV    -29.06mA   -82.77mA   -36.47mA
-800mV    -17.56mA   -26.87mA   -24.31mA
-760mV    -13.55mA   -15.08mA   -18.89mA
-680mV    -7.158mA   -6.178mA   -9.822mA
-440mV    -133.7uA   -176.5uA   -112.6uA
1.8V      0A         0A         0A
[POWER_clamp]
-1.8V     288.6pA    4.231nA    140.6nA
-1.08V    187.2pA    3.703nA    6.484nA
-1.04V    183.6pA    3.671nA    5.234nA
-960mV    176.5pA    3.605nA    3.359nA
-840mV    166pA      3.504nA    1.668nA
-720mV    155.7pA    3.399nA    806.1pA
-560mV    142pA      3.253nA    315.8pA
-200mV    111.6pA    2.962nA    92.54pA
-80mV     117.3pA    3.191nA    175.1pA
-40mV     151.6pA    2.851nA    129.2pA
40mV      60.08pA    0A         58.67pA
1.8V      0A         0A         0A
[Ramp]
dV/dt_r   0.537/0.903n   0.308/1.530n   0.775/0.514n
dV/dt_f   0.584/1.110n   0.311/1.838n   0.838/0.627n
R_load = 50.000
[Rising Waveform]
R_fixture= 50.000
V_fixture= 1.800
V_fixture_min= 1.620
V_fixture_max= 1.980
0s        826.5mV    1.102V     583.2mV
806ps     791.8mV    1.103V     612.7mV
906ps     780.5mV    1.101V     799mV
1.17ns    817.2mV    1.085V     1.754V
1.331ns   990.6mV    1.073V     1.906V
1.553ns   1.437V     1.059V     1.956V
1.86ns    1.738V     1.069V     1.972V
2.714ns   1.793V     1.542V     1.979V
3.104ns   1.797V     1.601V     1.98V
15ns      1.8V       1.62V      1.98V
[Rising Waveform]
R_fixture= 50.000
V_fixture= 0.0
V_fixture_min= 0.0
V_fixture_max= 0.0
0s        0V         0V         0V
1.126ns   -2.506mV   652.6uV    -7.974mV
1.846ns   27.93mV    -1.249mV   1.028V
2.095ns   174.6mV    -4.421mV   1.179V
2.506ns   482.3mV    -11.2mV    1.254V
2.95ns    700.1mV    -2.553mV   1.278V
3.51ns    819mV      86.19mV    1.288V
4.67ns    880.2mV    354.1mV    1.291V
5.85ns    891.5mV    465.3mV    1.292V
15ns      895.4mV    514.1mV    1.292V
[Falling Waveform]
R_fixture= 50.000
V_fixture= 1.800
V_fixture_min= 1.620
V_fixture_max= 1.980
0s        1.8V       1.62V      1.98V
1.135ns   1.798V     1.62V      1.972V
1.686ns   1.808V     1.619V     1.263V
2.016ns   1.722V     1.619V     861mV
2.305ns   1.565V     1.626V     693.1mV
2.704ns   1.299V     1.627V     620.6mV
3.523ns   975mV      1.569V     588.4mV
4.688ns   851.1mV    1.328V     583.5mV
7.298ns   827.1mV    1.125V     583.2mV
15ns      826.5mV    1.102V     583.2mV
[Falling Waveform]
R_fixture= 50.000
V_fixture= 0.0
V_fixture_min= 0.0
V_fixture_max= 0.0
0s        895.4mV    514.2mV    1.292V
836ps     895.5mV    514.1mV    1.287V
916ps     898.2mV    514mV      1.143V
1.246ns   917.2mV    513.7mV    188.8mV
1.514ns   534.4mV    515.6mV    21.8mV
1.874ns   102.6mV    536.7mV    6.178mV
2.267ns   16.87mV    459.9mV    1.869mV
2.798ns   5.102mV    122.1mV    434.1uV
3.337ns   1.88mV     16.17mV    105.4uV
15ns      0V         0V         0V
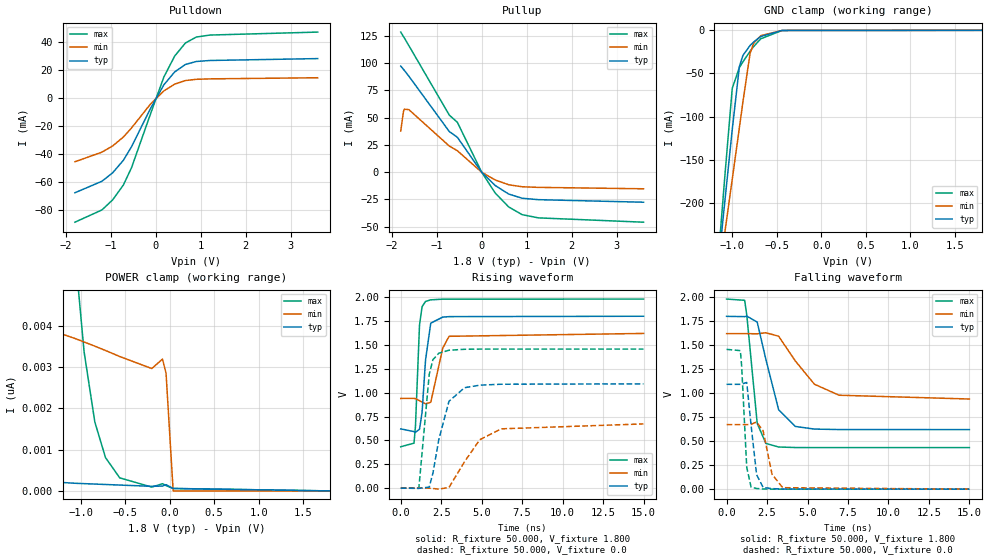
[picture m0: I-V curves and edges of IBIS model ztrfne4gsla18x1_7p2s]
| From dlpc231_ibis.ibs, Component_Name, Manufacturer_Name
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| Model ztrfne4gsla18x1_7p2s
[Model] ztrfne4gsla18x1_7p2s
Model_type I/O
Polarity   Non-Inverting
Enable   Active-High
Vinl =  0.540V
Vinh =  1.260V
Vref = 0.000V
Rref = 0.50k
Cref = 50.00pF
Vmeas = 0.90V
C_comp   2.363pF   2.288pF   2.543pF
C_comp_pullup   0.659pF   0.550pF   0.898pF
C_comp_pulldown   0.659pF   0.550pF   0.898pF
[Temperature Range]   25.000   0.125k   -40.000
[Voltage Range]   1.800V   1.620V   1.980V
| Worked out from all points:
|   slope of the pulldown table from 0 to 0.27 V, typ, clamps not added: 19.9 ohm
|   slope of the pullup table from 0 to 0.27 V, typ, clamps not added: 24.3 ohm
|   GND clamp passes 1 mA (typ) near -0.53 V on its own axis
|   rising waveform, R_fixture 50.000, V_fixture 1.800: 20-80 % time 296ps typ, 452ps min, 211ps max; typ from 0.62 V to 1.8 V
|   rising waveform, R_fixture 50.000, V_fixture 0.0: 20-80 % time 833ps typ, 1.58ns min, 434ps max; typ from 0 V to 1.09 V
|   falling waveform, R_fixture 50.000, V_fixture 1.800: 20-80 % time 967ps typ, 1.82ns min, 514ps max; typ from 1.8 V to 0.62 V
|   falling waveform, R_fixture 50.000, V_fixture 0.0: 20-80 % time 365ps typ, 519ps min, 254ps max; typ from 1.09 V to 0 V
[Pulldown]
-1.8V     -67.78mA   -45.55mA   -88.87mA
-1.2V     -59.54mA   -38.67mA   -80.11mA
-960mV    -53.44mA   -34.19mA   -72.85mA
-720mV    -44.39mA   -27.75mA   -62.11mA
-540mV    -34.73mA   -21.28mA   -49.74mA
-120mV    -7.451mA   -4.22mA    -11.37mA
180mV     9.688mA    5.261mA    15.31mA
420mV     18.87mA    10.09mA    30.28mA
660mV     24.23mA    12.68mA    39.65mA
900mV     26.34mA    13.56mA    43.85mA
1.2V      27.05mA    13.87mA    45.28mA
3.6V      28.41mA    14.68mA    47.41mA
[Pullup]
-1.8V     97.23mA    37.75mA    128.4mA
-1.74V    94.29mA    55.57mA    124.3mA
-1.72V    93.27mA    57.7mA     123mA
-1.62V    88.01mA    57.37mA    116mA
-720mV    37.26mA    23.96mA    52.32mA
-540mV    31.98mA    19.65mA    45.69mA
0V        10.36pA    166.7pA    4.435pA
300mV     -12.17mA   -7.092mA   -19.05mA
600mV     -20mA      -11.49mA   -31.8mA
900mV     -23.85mA   -13.35mA   -38.91mA
1.26V     -25.17mA   -13.9mA    -41.85mA
3.6V      -27.51mA   -15.2mA    -45.81mA
[GND_clamp]
-1.8V     -927mA     -775.7mA   -1.101A
-1.16V    -275.3mA   -291.3mA   -268.1mA
-1.12V    -235.1mA   -261.5mA   -216.5mA
-1.08V    -194.9mA   -231.7mA   -164.9mA
-1V       -114.9mA   -172.5mA   -67.23mA
-920mV    -41.99mA   -112.9mA   -43.08mA
-880mV    -29.06mA   -82.77mA   -36.47mA
-800mV    -17.56mA   -26.87mA   -24.31mA
-760mV    -13.55mA   -15.08mA   -18.89mA
-680mV    -7.158mA   -6.178mA   -9.822mA
-440mV    -133.7uA   -176.5uA   -112.6uA
1.8V      0A         0A         0A
[POWER_clamp]
-1.8V     288.6pA    4.231nA    140.6nA
-1.08V    187.2pA    3.703nA    6.484nA
-1.04V    183.6pA    3.671nA    5.234nA
-960mV    176.5pA    3.605nA    3.359nA
-840mV    166pA      3.504nA    1.668nA
-720mV    155.7pA    3.399nA    806.1pA
-560mV    142pA      3.253nA    315.8pA
-200mV    111.6pA    2.962nA    92.54pA
-80mV     117.3pA    3.191nA    175.1pA
-40mV     151.6pA    2.851nA    129.2pA
40mV      60.08pA    0A         58.67pA
1.8V      0A         0A         0A
[Ramp]
dV/dt_r   0.655/0.836n   0.403/1.589n   0.874/0.435n
dV/dt_f   0.708/0.975n   0.409/1.828n   0.928/0.515n
R_load = 50.000
[Rising Waveform]
R_fixture= 50.000
V_fixture= 1.800
V_fixture_min= 1.620
V_fixture_max= 1.980
0s        620.3mV    939mV      433.1mV
819ps     592mV      940.3mV    471mV
909ps     585.2mV    936.4mV    647.6mV
1.159ns   616.9mV    916.1mV    1.707V
1.317ns   792.6mV    900.6mV    1.9V
1.532ns   1.343V     882.5mV    1.955V
1.854ns   1.728V     898.8mV    1.972V
2.594ns   1.791V     1.466V     1.979V
2.985ns   1.796V     1.59V      1.979V
15ns      1.8V       1.62V      1.98V
[Rising Waveform]
R_fixture= 50.000
V_fixture= 0.0
V_fixture_min= 0.0
V_fixture_max= 0.0
0s        0V         0V         0V
1.119ns   -3.101mV   826.7uV    2.722mV
1.76ns    10.68mV    -861uV     1.192V
1.989ns   157.7mV    -3.991mV   1.345V
2.352ns   509.1mV    -11.04mV   1.413V
2.98ns    909.1mV    6.51mV     1.444V
3.942ns   1.052V     276.8mV    1.454V
4.88ns    1.078V     506.5mV    1.456V
6.2ns     1.088V     620.7mV    1.456V
15ns      1.092V     672.4mV    1.456V
[Falling Waveform]
R_fixture= 50.000
V_fixture= 1.800
V_fixture_min= 1.620
V_fixture_max= 1.980
0s        1.8V       1.62V      1.98V
1.115ns   1.797V     1.62V      1.967V
1.251ns   1.802V     1.62V      1.81V
1.892ns   1.74V      1.618V     686mV
2.426ns   1.353V     1.629V     476.6mV
3.215ns   828mV      1.593V     439.1mV
4.248ns   653.3mV    1.335V     433.7mV
5.427ns   625.8mV    1.093V     433.2mV
6.95ns    620.9mV    978.4mV    433.1mV
15ns      620.3mV    939mV      433.1mV
[Falling Waveform]
R_fixture= 50.000
V_fixture= 0.0
V_fixture_min= 0.0
V_fixture_max= 0.0
0s        1.092V     672.9mV    1.456V
852ps     1.092V     672.6mV    1.443V
932ps     1.095V     672.5mV    1.281V
1.245ns   1.111V     672.2mV    228mV
1.515ns   664.4mV    674.7mV    20.43mV
1.855ns   150.1mV    700.2mV    6.827mV
2.258ns   18.04mV    607.1mV    2.015mV
2.808ns   5.569mV    155.5mV    434.6uV
3.468ns   1.682mV    15.4mV     75uV
15ns      0V         0V         0V
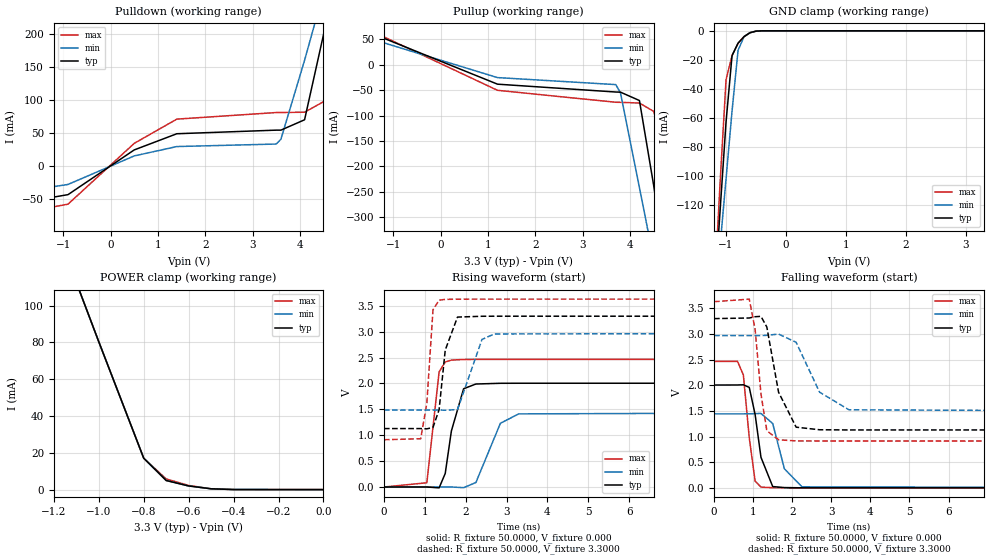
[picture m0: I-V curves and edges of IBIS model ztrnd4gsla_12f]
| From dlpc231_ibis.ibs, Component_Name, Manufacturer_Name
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| Model ztrnd4gsla_12f
[Model]   ztrnd4gsla_12f
Model_type   I/O
Polarity   Non-Inverting
Enable   Active-High
Vinl = 0.8000V
Vinh = 2.0000V
Vmeas = 1.5000V
Cref =50.0000pF
Rref = 0.5000k
Vref =  0.000V
C_comp   0.7000pF   0.7000pF   0.7000pF
[Temperature Range]   25.0000   0.1240k   -40.0000
[Voltage Range]   3.3000V   2.9700V   3.6300V
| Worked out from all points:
|   slope of the pulldown table from 0 to 0.495 V, typ, clamps not added: 20.8 ohm
|   slope of the pullup table from 0 to 0.495 V, typ, clamps not added: 25.7 ohm
|   GND clamp passes 1 mA (typ) near -0.57 V on its own axis
|   POWER clamp passes 1 mA (typ) near -0.54 V on its own axis
|   rising waveform, R_fixture 50.0000, V_fixture 0.000: 20-80 % time 257ps typ, 438ps min, 208ps max; typ from 0 V to 2 V
|   rising waveform, R_fixture 50.0000, V_fixture 3.3000: 20-80 % time 199ps typ, 304ps min, 158ps max; typ from 1.13 V to 3.3 V
|   falling waveform, R_fixture 50.0000, V_fixture 0.000: 20-80 % time 264ps typ, 319ps min, 208ps max; typ from 2 V to 0 V
|   falling waveform, R_fixture 50.0000, V_fixture 3.3000: 20-80 % time 345ps typ, 596ps min, 227ps max; typ from 3.3 V to 1.13 V
[Pulldown]
-3.3V     -73mA      -55mA      -90mA
-900mV    -43.69mA   -28.26mA   -58.09mA
500mV     23.99mA    14.89mA    33.9mA
1.4V      48.44mA    29.06mA    70.56mA
3.5V      53.88mA    32.86mA    80.51mA
3.6V      53.91mA    40.18mA    80.55mA
4.1V      69.56mA    159.6mA    81.03mA
4.5V      198.3mA    262.5mA    96.9mA
4.7V      266mA      317.2mA    172.7mA
4.9V      336.1mA    374.9mA    257.2mA
5.1V      409.2mA    436.3mA    344.5mA
6.6V      1.092A     994.6mA    1.119A
[Pullup]
-3.3V     43mA       55.7mA     31mA
-2.5V     69.3mA     66.1mA     65.5mA
-1.5V     63.3mA     51.6mA     67.9mA
1.2V      -38.25mA   -25.31mA   -50.33mA
3.7V      -53.69mA   -39.1mA    -73.83mA
3.8V      -53.99mA   -55.36mA   -73.99mA
4.2V      -70.44mA   -241.6mA   -75.38mA
4.5V      -236.8mA   -383.2mA   -91.7mA
4.7V      -361.3mA   -478.4mA   -150.8mA
4.9V      -486.6mA   -574.2mA   -307mA
5.1V      -612.6mA   -670.5mA   -464.3mA
6.6V      -1.569A    -1.403A    -1.657A
[GND_clamp]
-3.3V     -1.517A    -1.206A    -1.849A
-1.2V     -185.7mA   -194.8mA   -182.8mA
-1.1V     -124mA     -148.1mA   -104.8mA
-1V       -62.54mA   -101.7mA   -33.61mA
-900mV    -17.04mA   -55.16mA   -17.04mA
-800mV    -8.525mA   -13.45mA   -8.525mA
-700mV    -3.999mA   -3.999mA   -3.999mA
-600mV    -1.289mA   -1.289mA   -1.289mA
-500mV    -219.7uA   -252.6uA   -203.6uA
-400mV    -15.61uA   -27.49uA   -11.15uA
3.3V      3.373nA    3.373nA    17.05nA
[POWER_clamp]
-3.3V     1.027A     840.1mA    1.22A
-1.1V     112.7mA    112.7mA    112.7mA
-1V       80.41mA    80.41mA    80.41mA
-800mV    17.08mA    17.08mA    17.08mA
-700mV    4.947mA    4.947mA    5.794mA
-600mV    1.98mA     1.98mA     2.27mA
-500mV    443.8uA    443.8uA    443.8uA
-400mV    34.78uA    34.78uA    34.78uA
0V        3.373nA    3.373nA    57.43nA
[Ramp]
dV/dt_r   1.2030/0.2484n   0.8658/0.4212n   1.4790/0.1694n
dV/dt_f   1.3026/0.3326n   0.8898/0.5892n   1.6300/0.2114n
R_load = 50.0000
[Rising Waveform]
R_fixture = 50.0000
V_fixture = 0.000
V_fixture_min = 0.000
V_fixture_max = 0.000
0s        0V         0V         0V
1.05ns    386uV      -4.8uV     82.49mV
1.35ns    -16.27mV   73.97uV    2.224V
1.5ns     262.1mV    381.9uV    2.415V
1.65ns    1.081V     344.9uV    2.452V
1.95ns    1.899V     -12.83mV   2.464V
2.25ns    1.99V      86.8mV     2.465V
2.85ns    2.004V     1.232V     2.465V
3.3ns     2.005V     1.413V     2.465V
14.85ns   2.005V     1.443V     2.465V
[Rising Waveform]
R_fixture = 50.0000
V_fixture = 3.3000
V_fixture_min = 2.9700
V_fixture_max = 3.6300
0s        1.129V     1.487V     913.4mV
900ps     1.129V     1.487V     933.1mV
1.05ns    1.124V     1.487V     1.623V
1.2ns     1.151V     1.487V     3.423V
1.35ns    1.495V     1.487V     3.61V
1.5ns     2.646V     1.484V     3.625V
1.8ns     3.283V     1.495V     3.629V
2.4ns     3.299V     2.852V     3.63V
2.7ns     3.3V       2.957V     3.63V
14.85ns   3.3V       2.97V      3.63V
[Falling Waveform]
R_fixture = 50.0000
V_fixture = 0.000
V_fixture_min = 0.000
V_fixture_max = 0.000
0s        2.005V     1.443V     2.465V
600ps     2.006V     1.443V     2.466V
750ps     2.01V      1.443V     2.2V
900ps     1.959V     1.444V     979.7mV
1.05ns    1.433V     1.448V     132mV
1.2ns     595.7mV    1.451V     14.35mV
1.5ns     25.44mV    1.255V     3.15mV
1.8ns     5.564mV    370.9mV    662.8uV
2.25ns    878.8uV    20.03mV    57.62uV
14.85ns   0V         0V         0V
[Falling Waveform]
R_fixture = 50.0000
V_fixture = 3.3000
V_fixture_min = 2.9700
V_fixture_max = 3.6300
0s        3.3V       2.97V      3.63V
900ps     3.312V     2.969V     3.68V
1.05ns    3.337V     2.969V     3.091V
1.2ns     3.344V     2.97V      1.828V
1.35ns    3.135V     2.974V     1.114V
1.65ns    1.865V     2.999V     937.2mV
2.1ns     1.183V     2.838V     915.4mV
2.7ns     1.133V     1.865V     913.5mV
3.45ns    1.129V     1.522V     913.4mV
14.85ns   1.129V     1.487V     913.4mV
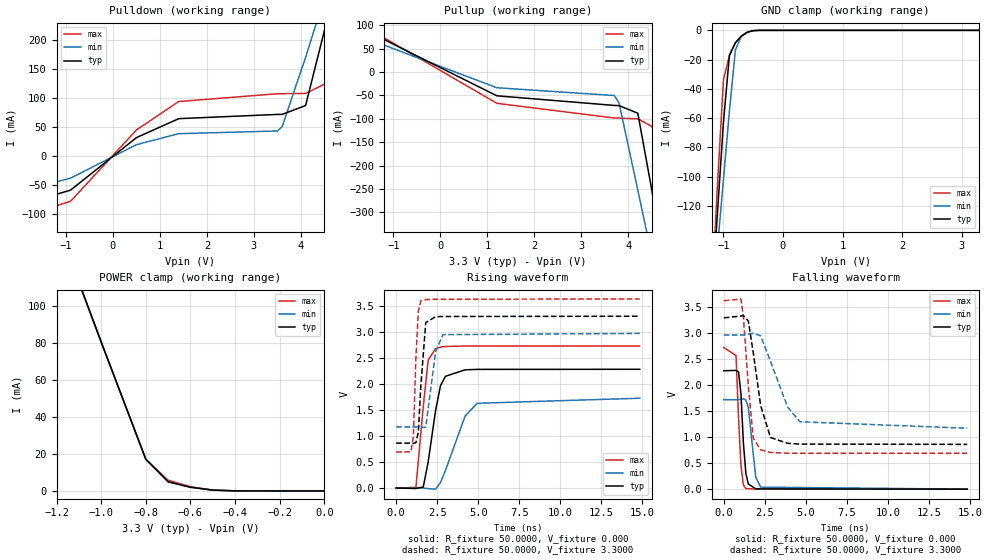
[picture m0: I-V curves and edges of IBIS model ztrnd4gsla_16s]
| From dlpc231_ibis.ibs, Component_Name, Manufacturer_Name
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| Model ztrnd4gsla_16s
[Model]   ztrnd4gsla_16s
Model_type   I/O
Polarity   Non-Inverting
Enable   Active-High
Vinl = 0.8000V
Vinh = 2.0000V
Vmeas = 1.5000V
Cref =50.0000pF
Rref = 0.5000k
Vref =  0.000V
C_comp   0.7000pF   0.7000pF   0.7000pF
[Temperature Range]   25.0000   0.1240k   -40.0000
[Voltage Range]   3.3000V   2.9700V   3.6300V
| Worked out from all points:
|   slope of the pulldown table from 0 to 0.495 V, typ, clamps not added: 15.6 ohm
|   slope of the pullup table from 0 to 0.495 V, typ, clamps not added: 19.3 ohm
|   GND clamp passes 1 mA (typ) near -0.57 V on its own axis
|   POWER clamp passes 1 mA (typ) near -0.54 V on its own axis
|   rising waveform, R_fixture 50.0000, V_fixture 0.000: 20-80 % time 668ps typ, 1.19ns min, 438ps max; typ from 0 V to 2.28 V
|   rising waveform, R_fixture 50.0000, V_fixture 3.3000: 20-80 % time 250ps typ, 336ps min, 212ps max; typ from 0.863 V to 3.3 V
|   falling waveform, R_fixture 50.0000, V_fixture 0.000: 20-80 % time 258ps typ, 337ps min, 235ps max; typ from 2.28 V to 0 V
|   falling waveform, R_fixture 50.0000, V_fixture 3.3000: 20-80 % time 674ps typ, 1.28ns min, 425ps max; typ from 3.3 V to 0.863 V
[Pulldown]
-3.3V     -98mA      -73mA      -121mA
-1.9V     -82.3mA    -58.8mA    -103mA
-900mV    -58.28mA   -37.7mA    -77.43mA
500mV     32mA       19.87mA    45.18mA
1.4V      64.66mA    38.81mA    94.14mA
3.5V      71.95mA    43.46mA    107.5mA
3.6V      72mA       50.62mA    107.6mA
4.1V      87.22mA    170.1mA    108.1mA
4.5V      216.1mA    273mA      123.9mA
4.7V      283.8mA    327.8mA    199mA
4.9V      354.1mA    385.5mA    283.7mA
6.6V      1.114A     1.007A     1.151A
[Pullup]
-3.3V     58mA       74.3mA     41mA
-2.5V     92.4mA     88.2mA     87.5mA
-1.5V     84.3mA     68.8mA     90.6mA
1.2V      -50.97mA   -33.74mA   -67.05mA
3.7V      -71.59mA   -50.41mA   -98.43mA
3.8V      -71.91mA   -66.34mA   -98.65mA
4.2V      -88.26mA   -252.6mA   -100.2mA
4.5V      -253.9mA   -394.2mA   -116.5mA
4.7V      -378.3mA   -489.4mA   -173.9mA
4.9V      -503.7mA   -585.2mA   -330.2mA
5.1V      -629.8mA   -681.5mA   -487.5mA
6.6V      -1.587A    -1.414A    -1.681A
[GND_clamp]
-3.3V     -1.517A    -1.206A    -1.849A
-1.2V     -185.7mA   -194.8mA   -182.8mA
-1.1V     -124mA     -148.1mA   -104.8mA
-1V       -62.54mA   -101.7mA   -33.61mA
-900mV    -17.04mA   -55.16mA   -17.04mA
-800mV    -8.525mA   -13.45mA   -8.525mA
-700mV    -3.999mA   -3.999mA   -3.999mA
-600mV    -1.289mA   -1.289mA   -1.289mA
-500mV    -219.7uA   -252.6uA   -203.6uA
-400mV    -15.61uA   -27.49uA   -11.15uA
3.3V      3.373nA    3.373nA    17.05nA
[POWER_clamp]
-3.3V     1.027A     840.1mA    1.22A
-1.1V     112.7mA    112.7mA    112.7mA
-1V       80.41mA    80.41mA    80.41mA
-800mV    17.08mA    17.08mA    17.08mA
-700mV    4.947mA    4.947mA    5.794mA
-600mV    1.98mA     1.98mA     2.27mA
-500mV    443.8uA    443.8uA    443.8uA
-400mV    34.78uA    34.78uA    34.78uA
0V        3.373nA    3.373nA    57.43nA
[Ramp]
dV/dt_r   1.3686/0.6595n   1.0344/1.1845n   1.6374/0.4328n
dV/dt_f   1.4623/0.6741n   1.0776/1.2825n   1.7638/0.4167n
R_load = 50.0000
[Rising Waveform]
R_fixture = 50.0000
V_fixture = 0.000
V_fixture_min = 0.000
V_fixture_max = 0.000
0s        0V         0V         0V
1.2ns     -8.573mV   -9.09uV    13.25mV
1.65ns    20.5mV     691.6uV    1.568V
1.95ns    502.5mV    -11.96mV   2.46V
2.4ns     1.489V     -21.86mV   2.677V
2.7ns     1.967V     106.7mV    2.707V
3ns       2.146V     336.6mV    2.719V
4.2ns     2.271V     1.383V     2.728V
4.95ns    2.279V     1.628V     2.729V
14.85ns   2.281V     1.725V     2.729V
[Rising Waveform]
R_fixture = 50.0000
V_fixture = 3.3000
V_fixture_min = 2.9700
V_fixture_max = 3.6300
0s        862.8mV    1.174V     690.3mV
900ps     862.6mV    1.174V     696.6mV
1.05ns    857.3mV    1.174V     999.4mV
1.2ns     870.5mV    1.174V     2.5V
1.35ns    1.077V     1.173V     3.401V
1.5ns     1.957V     1.17V      3.597V
1.8ns     3.177V     1.169V     3.62V
2.4ns     3.291V     2.62V      3.626V
2.85ns    3.295V     2.947V     3.628V
14.85ns   3.3V       2.97V      3.63V
[Falling Waveform]
R_fixture = 50.0000
V_fixture = 0.000
V_fixture_min = 0.000
V_fixture_max = 0.000
0s        2.281V     1.725V     2.729V
750ps     2.288V     1.724V     2.574V
900ps     2.261V     1.725V     1.388V
1.05ns    1.835V     1.73V      446.2mV
1.2ns     881.2mV    1.737V     80.53mV
1.35ns    302.2mV    1.718V     13.4mV
1.5ns     98.68mV    1.571V     7.626mV
1.95ns    7.169mV    228.3mV    3.834mV
2.25ns    4.575mV    39.11mV    2.422mV
14.85ns   0V         0V         0V
[Falling Waveform]
R_fixture = 50.0000
V_fixture = 3.3000
V_fixture_min = 2.9700
V_fixture_max = 3.6300
0s        3.3V       2.97V      3.63V
1.05ns    3.336V     2.969V     3.662V
1.2ns     3.344V     2.969V     3.313V
1.5ns     3.24V      2.988V     1.985V
1.8ns     2.631V     3.004V     983.7mV
2.25ns    1.612V     2.954V     757.3mV
2.85ns    995.1mV    2.463V     707.6mV
3.9ns     883.1mV    1.579V     692.2mV
4.65ns    868.5mV    1.298V     690.7mV
14.85ns   862.8mV    1.174V     690.3mV
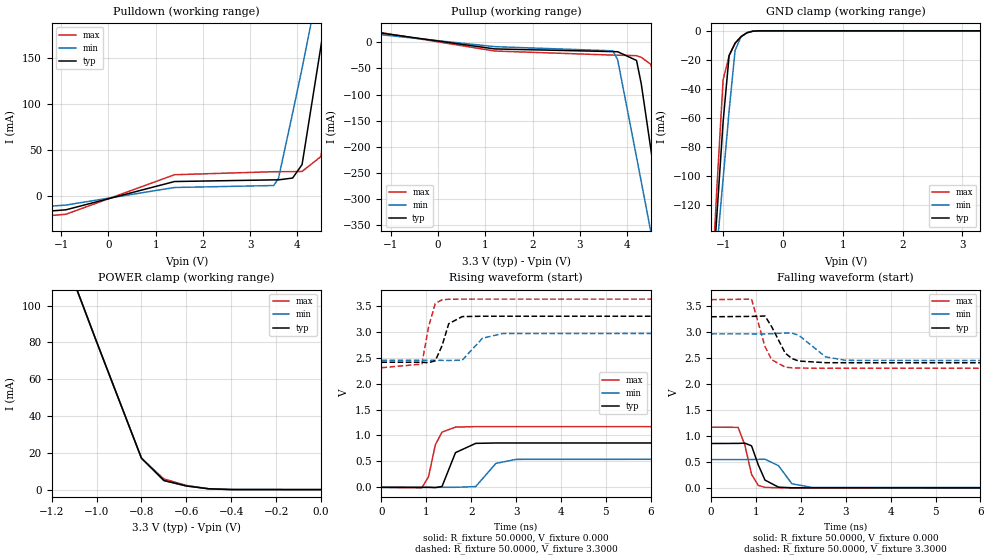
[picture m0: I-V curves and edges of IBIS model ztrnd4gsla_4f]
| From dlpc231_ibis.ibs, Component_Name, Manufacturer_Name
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| Model ztrnd4gsla_4f
[Model]   ztrnd4gsla_4f
Model_type   I/O
Polarity   Non-Inverting
Enable   Active-High
Vinl = 0.8000V
Vinh = 2.0000V
Vmeas = 1.5000V
Cref =50.0000pF
Rref = 0.5000k
Vref =  0.000V
C_comp   0.7000pF   0.7000pF   0.7000pF
[Temperature Range]   25.0000   0.1240k   -40.0000
[Voltage Range]   3.3000V   2.9700V   3.6300V
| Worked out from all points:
|   slope of the pulldown table from 0 to 0.495 V, typ, clamps not added: 62.5 ohm
|   slope of the pullup table from 0 to 0.495 V, typ, clamps not added: 77 ohm
|   GND clamp passes 1 mA (typ) near -0.57 V on its own axis
|   POWER clamp passes 1 mA (typ) near -0.54 V on its own axis
|   rising waveform, R_fixture 50.0000, V_fixture 0.000: 20-80 % time 253ps typ, 326ps min, 215ps max; typ from 0 V to 0.856 V
|   rising waveform, R_fixture 50.0000, V_fixture 3.3000: 20-80 % time 211ps typ, 265ps min, 199ps max; typ from 2.41 V to 3.3 V
|   falling waveform, R_fixture 50.0000, V_fixture 0.000: 20-80 % time 237ps typ, 278ps min, 217ps max; typ from 0.856 V to 0 V
|   falling waveform, R_fixture 50.0000, V_fixture 3.3000: 20-80 % time 325ps typ, 437ps min, 296ps max; typ from 3.3 V to 2.41 V
[Pulldown]
-3.3V     -24mA      -18mA      -30mA
-900mV    -14.55mA   -9.41mA    -19.37mA
1.4V      16.11mA    9.655mA    23.49mA
3.5V      17.9mA     11.77mA    26.76mA
3.6V      17.91mA    19.43mA    26.77mA
3.9V      19.9mA     90.39mA    26.83mA
4.1V      34.51mA    138.9mA    27.06mA
4.5V      163.1mA    241.5mA    43.23mA
4.7V      230.5mA    296.1mA    120.2mA
4.9V      300.3mA    353.6mA    204.3mA
5.1V      373.1mA    414.8mA    291.1mA
6.6V      1.049A     968.2mA    1.056A
[Pullup]
-3.3V     15mA       18.5mA     10mA
-1.5V     21.2mA     17.2mA     22.7mA
1.2V      -12.77mA   -8.444mA   -16.81mA
3.7V      -17.91mA   -16.46mA   -24.61mA
3.8V      -18.14mA   -33.44mA   -24.66mA
4.2V      -34.83mA   -219.7mA   -25.74mA
4.3V      -79.52mA   -266.7mA   -28.82mA
4.5V      -202.8mA   -361.2mA   -42.15mA
4.7V      -327.1mA   -456.4mA   -104.6mA
4.9V      -452.4mA   -552.1mA   -260.7mA
5.1V      -578.3mA   -648.3mA   -417.9mA
6.6V      -1.534A    -1.38A     -1.61A
[GND_clamp]
-3.3V     -1.517A    -1.206A    -1.849A
-1.2V     -185.7mA   -194.8mA   -182.8mA
-1.1V     -124mA     -148.1mA   -104.8mA
-1V       -62.54mA   -101.7mA   -33.61mA
-900mV    -17.04mA   -55.16mA   -17.04mA
-800mV    -8.525mA   -13.45mA   -8.525mA
-700mV    -3.999mA   -3.999mA   -3.999mA
-600mV    -1.289mA   -1.289mA   -1.289mA
-500mV    -219.7uA   -252.6uA   -203.6uA
-400mV    -15.61uA   -27.49uA   -11.15uA
3.3V      3.373nA    3.373nA    17.05nA
[POWER_clamp]
-3.3V     1.027A     840.1mA    1.22A
-1.1V     112.7mA    112.7mA    112.7mA
-1V       80.41mA    80.41mA    80.41mA
-800mV    17.08mA    17.08mA    17.08mA
-700mV    4.947mA    4.947mA    5.794mA
-600mV    1.98mA     1.98mA     2.27mA
-500mV    443.8uA    443.8uA    443.8uA
-400mV    34.78uA    34.78uA    34.78uA
0V        3.373nA    3.373nA    57.43nA
[Ramp]
dV/dt_r   0.5134/0.2343n   0.3275/0.3025n   0.7026/0.1999n
dV/dt_f   0.5322/0.3194n   0.3126/0.4236n   0.7938/0.2708n
R_load = 50.0000
[Rising Waveform]
R_fixture = 50.0000
V_fixture = 0.000
V_fixture_min = 0.000
V_fixture_max = 0.000
0s        0V         0V         0V
900ps     168.8uV    -1.632uV   -9.925mV
1.05ns    559.1uV    -3.729uV   204.7mV
1.2ns     -5.581mV   -3.758uV   817.5mV
1.35ns    17.02mV    52.15uV    1.065V
1.65ns    669.2mV    424.8uV    1.162V
2.1ns     848.3mV    15.08mV    1.171V
2.55ns    855.4mV    461.2mV    1.171V
3ns       855.7mV    539.8mV    1.171V
14.85ns   855.7mV    545.9mV    1.171V
[Rising Waveform]
R_fixture = 50.0000
V_fixture = 3.3000
V_fixture_min = 2.9700
V_fixture_max = 3.6300
0s        2.413V     2.449V     2.307V
900ps     2.412V     2.449V     2.377V
1.05ns    2.404V     2.449V     3.091V
1.2ns     2.442V     2.449V     3.548V
1.35ns    2.73V      2.449V     3.617V
1.5ns     3.156V     2.447V     3.628V
1.8ns     3.293V     2.452V     3.63V
2.25ns    3.3V       2.875V     3.63V
2.7ns     3.3V       2.967V     3.63V
14.85ns   3.3V       2.97V      3.63V
[Falling Waveform]
R_fixture = 50.0000
V_fixture = 0.000
V_fixture_min = 0.000
V_fixture_max = 0.000
0s        855.7mV    545.9mV    1.171V
600ps     857.7mV    545.8mV    1.167V
750ps     862.2mV    545.8mV    828.3mV
900ps     810.5mV    546.6mV    260.5mV
1.05ns    443.3mV    549.4mV    46.77mV
1.2ns     149.3mV    552.3mV    10.12mV
1.5ns     13.42mV    427.8mV    705.8uV
1.8ns     1.72mV     78.17mV    48.42uV
2.25ns    77.66uV    8.578mV    494.6nV
14.85ns   0V         0V         0V
[Falling Waveform]
R_fixture = 50.0000
V_fixture = 3.3000
V_fixture_min = 2.9700
V_fixture_max = 3.6300
0s        3.3V       2.97V      3.63V
900ps     3.307V     2.969V     3.64V
1.2ns     3.314V     2.969V     2.722V
1.35ns    3.105V     2.972V     2.471V
1.65ns    2.599V     2.988V     2.329V
1.8ns     2.494V     2.985V     2.315V
1.95ns    2.446V     2.944V     2.31V
2.55ns    2.414V     2.526V     2.307V
3ns       2.413V     2.459V     2.307V
14.85ns   2.413V     2.449V     2.307V
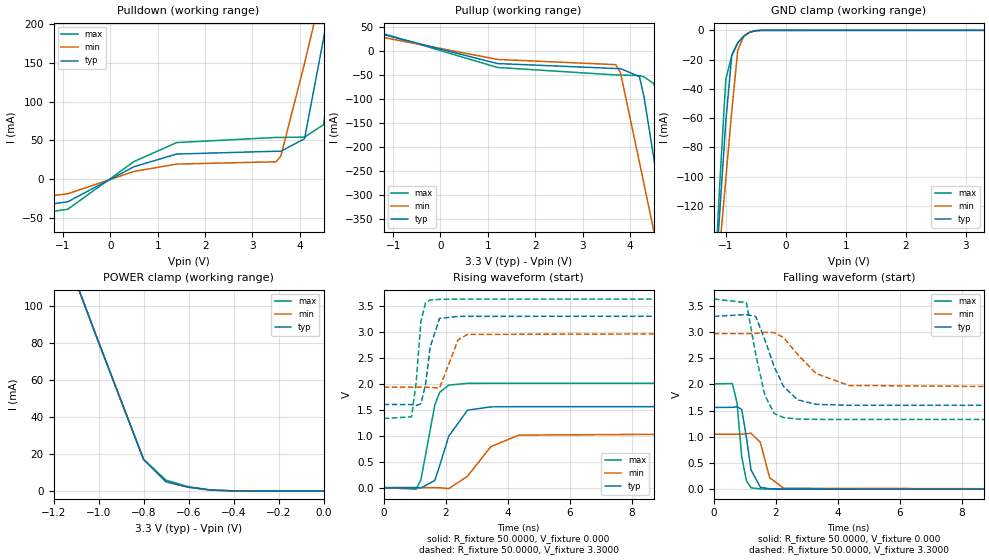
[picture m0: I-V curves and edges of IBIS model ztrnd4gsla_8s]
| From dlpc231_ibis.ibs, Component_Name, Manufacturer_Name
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| Model ztrnd4gsla_8s
[Model]   ztrnd4gsla_8s
Model_type   I/O
Polarity   Non-Inverting
Enable   Active-High
Vinl = 0.8000V
Vinh = 2.0000V
Vmeas = 1.5000V
Cref =50.0000pF
Rref = 0.5000k
Vref =  0.000V
C_comp   0.7000pF   0.7000pF   0.7000pF
[Temperature Range]   25.0000   0.1240k   -40.0000
[Voltage Range]   3.3000V   2.9700V   3.6300V
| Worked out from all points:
|   slope of the pulldown table from 0 to 0.495 V, typ, clamps not added: 31.1 ohm
|   slope of the pullup table from 0 to 0.495 V, typ, clamps not added: 38.5 ohm
|   GND clamp passes 1 mA (typ) near -0.57 V on its own axis
|   POWER clamp passes 1 mA (typ) near -0.54 V on its own axis
|   rising waveform, R_fixture 50.0000, V_fixture 0.000: 20-80 % time 550ps typ, 870ps min, 384ps max; typ from 0 V to 1.56 V
|   rising waveform, R_fixture 50.0000, V_fixture 3.3000: 20-80 % time 255ps typ, 328ps min, 202ps max; typ from 1.6 V to 3.3 V
|   falling waveform, R_fixture 50.0000, V_fixture 0.000: 20-80 % time 256ps typ, 288ps min, 216ps max; typ from 1.56 V to 0 V
|   falling waveform, R_fixture 50.0000, V_fixture 3.3000: 20-80 % time 687ps typ, 1.03ns min, 467ps max; typ from 3.3 V to 1.6 V
[Pulldown]
-3.3V     -49mA      -37mA      -60mA
-900mV    -29.2mA    -18.88mA   -38.82mA
500mV     16.04mA    9.953mA    22.68mA
1.4V      32.36mA    19.42mA    47.15mA
3.5V      35.98mA    22.38mA    53.75mA
3.6V      36mA       29.86mA    53.78mA
4.1V      52.11mA    149.3mA    54.16mA
4.5V      180.8mA    252.1mA    70.17mA
4.7V      248.3mA    306.7mA    146.6mA
4.9V      318.3mA    364.3mA    230.8mA
5.1V      391.2mA    425.6mA    317.9mA
6.6V      1.071A     981.5mA    1.087A
[Pullup]
-3.3V     29mA       37.1mA     20mA
-1.5V     42.2mA     34.4mA     45.3mA
1.2V      -25.52mA   -16.89mA   -33.59mA
3.7V      -35.8mA    -27.78mA   -49.22mA
3.8V      -36.07mA   -44.4mA    -49.33mA
4.2V      -52.63mA   -230.7mA   -50.56mA
4.3V      -96.51mA   -277.7mA   -53.61mA
4.5V      -219.8mA   -372.2mA   -66.93mA
4.7V      -344.2mA   -467.4mA   -127.7mA
4.9V      -469.5mA   -563.1mA   -283.9mA
5.1V      -595.5mA   -659.4mA   -441.1mA
6.6V      -1.552A    -1.391A    -1.633A
[GND_clamp]
-3.3V     -1.517A    -1.206A    -1.849A
-1.2V     -185.7mA   -194.8mA   -182.8mA
-1.1V     -124mA     -148.1mA   -104.8mA
-1V       -62.54mA   -101.7mA   -33.61mA
-900mV    -17.04mA   -55.16mA   -17.04mA
-800mV    -8.525mA   -13.45mA   -8.525mA
-700mV    -3.999mA   -3.999mA   -3.999mA
-600mV    -1.289mA   -1.289mA   -1.289mA
-500mV    -219.7uA   -252.6uA   -203.6uA
-400mV    -15.61uA   -27.49uA   -11.15uA
3.3V      3.373nA    3.373nA    17.05nA
[POWER_clamp]
-3.3V     1.027A     840.1mA    1.22A
-1.1V     112.7mA    112.7mA    112.7mA
-1V       80.41mA    80.41mA    80.41mA
-800mV    17.08mA    17.08mA    17.08mA
-700mV    4.947mA    4.947mA    5.794mA
-600mV    1.98mA     1.98mA     2.27mA
-500mV    443.8uA    443.8uA    443.8uA
-400mV    34.78uA    34.78uA    34.78uA
0V        3.373nA    3.373nA    57.43nA
[Ramp]
dV/dt_r   0.9354/0.5421n   0.6288/0.8699n   1.2060/0.3776n
dV/dt_f   1.0194/0.6830n   0.6204/1.0289n   1.3794/0.4672n
R_load = 50.0000
[Rising Waveform]
R_fixture = 50.0000
V_fixture = 0.000
V_fixture_min = 0.000
V_fixture_max = 0.000
0s        0V         0V         0V
1.05ns    1.145mV    -7.76uV    -28.88mV
1.2ns     -6.544mV   -9.567uV   150.5mV
1.65ns    139.7mV    930.6uV    1.595V
1.8ns     414.7mV    -2.404mV   1.832V
2.1ns     992.1mV    -17.24mV   1.974V
2.7ns     1.491V     218mV      2.008V
3.45ns    1.555V     787.7mV    2.01V
4.35ns    1.559V     1.011V     2.01V
14.85ns   1.559V     1.048V     2.01V
[Rising Waveform]
R_fixture = 50.0000
V_fixture = 3.3000
V_fixture_min = 2.9700
V_fixture_max = 3.6300
0s        1.601V     1.935V     1.331V
900ps     1.6V       1.935V     1.364V
1.05ns    1.583V     1.935V     2.043V
1.2ns     1.615V     1.936V     3.196V
1.35ns    1.985V     1.935V     3.56V
1.5ns     2.709V     1.93V      3.612V
1.8ns     3.257V     1.917V     3.625V
2.4ns     3.296V     2.846V     3.629V
2.7ns     3.298V     2.949V     3.629V
14.85ns   3.3V       2.97V      3.63V
[Falling Waveform]
R_fixture = 50.0000
V_fixture = 0.000
V_fixture_min = 0.000
V_fixture_max = 0.000
0s        1.559V     1.048V     2.01V
600ps     1.563V     1.048V     2.016V
750ps     1.575V     1.048V     1.646V
900ps     1.523V     1.049V     619.5mV
1.05ns    996.7mV    1.057V     165.9mV
1.2ns     369.3mV    1.068V     25.13mV
1.5ns     35.35mV    894.3mV    5.521mV
1.8ns     6.654mV    219.7mV    2.83mV
2.25ns    2.943mV    17.75mV    747.4uV
14.85ns   0V         0V         0V
[Falling Waveform]
R_fixture = 50.0000
V_fixture = 3.3000
V_fixture_min = 2.9700
V_fixture_max = 3.6300
0s        3.3V       2.97V      3.63V
1.05ns    3.333V     2.969V     3.562V
1.35ns    3.299V     2.973V     2.581V
1.65ns    2.848V     2.995V     1.785V
1.95ns    2.332V     2.989V     1.443V
2.25ns    1.961V     2.894V     1.367V
2.7ns     1.706V     2.574V     1.339V
3.3ns     1.62V      2.208V     1.333V
4.35ns    1.602V     1.98V      1.331V
14.85ns   1.601V     1.935V     1.331V
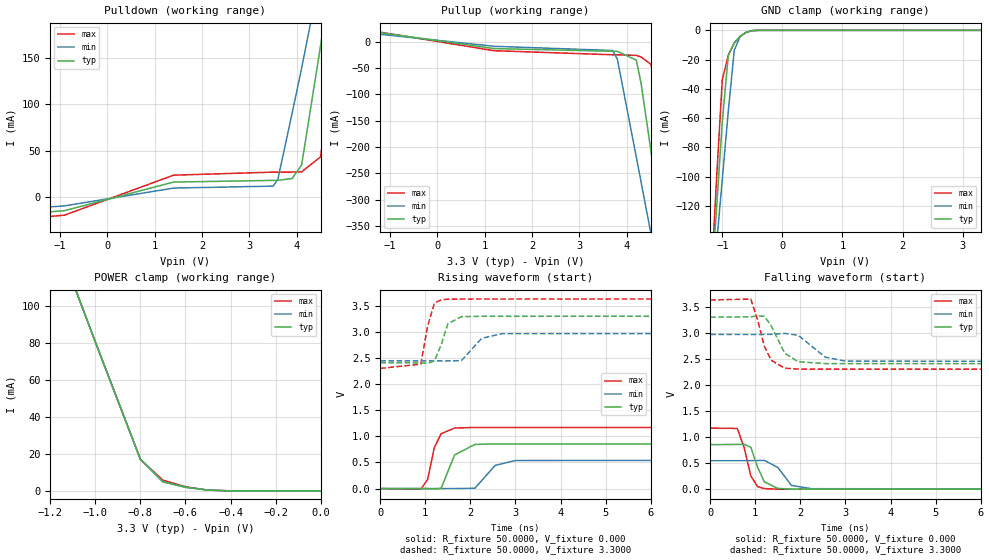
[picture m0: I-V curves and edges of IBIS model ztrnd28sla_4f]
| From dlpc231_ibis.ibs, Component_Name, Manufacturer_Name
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| Model ztrnd28sla_4f
[Model]   ztrnd28sla_4f
Model_type   I/O
Polarity   Non-Inverting
Enable   Active-High
Vinl = 0.8000V
Vinh = 2.0000V
Vmeas = 1.5000V
Cref =50.0000pF
Rref = 0.5000k
Vref =  0.000V
C_comp   0.7000pF   0.7000pF   0.7000pF
[Temperature Range]   25.0000   0.1240k   -40.0000
[Voltage Range]   3.3000V   2.9700V   3.6300V
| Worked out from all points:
|   slope of the pulldown table from 0 to 0.495 V, typ, clamps not added: 62.2 ohm
|   slope of the pullup table from 0 to 0.495 V, typ, clamps not added: 76.9 ohm
|   GND clamp passes 1 mA (typ) near -0.57 V on its own axis
|   POWER clamp passes 1 mA (typ) near -0.54 V on its own axis
|   rising waveform, R_fixture 50.0000, V_fixture 0.000: 20-80 % time 268ps typ, 330ps min, 221ps max; typ from 0 V to 0.856 V
|   rising waveform, R_fixture 50.0000, V_fixture 3.3000: 20-80 % time 217ps typ, 271ps min, 199ps max; typ from 2.41 V to 3.3 V
|   falling waveform, R_fixture 50.0000, V_fixture 0.000: 20-80 % time 237ps typ, 283ps min, 220ps max; typ from 0.856 V to 0 V
|   falling waveform, R_fixture 50.0000, V_fixture 3.3000: 20-80 % time 324ps typ, 435ps min, 292ps max; typ from 3.3 V to 2.41 V
[Pulldown]
-3.3V     -24mA      -18mA      -30mA
-900mV    -14.61mA   -9.45mA    -19.44mA
1.4V      16.19mA    9.709mA    23.59mA
3.5V      17.99mA    11.83mA    26.87mA
3.6V      18mA       19.49mA    26.89mA
3.9V      19.99mA    90.45mA    26.94mA
4.1V      34.59mA    138.9mA    27.17mA
4.5V      163.2mA    241.6mA    43.34mA
4.7V      230.6mA    296.2mA    120.3mA
4.9V      300.4mA    353.7mA    204.4mA
5.1V      373.1mA    414.9mA    291.2mA
6.6V      1.049A     968.3mA    1.056A
[Pullup]
-3.3V     15mA       18.6mA     10mA
-1.5V     21.2mA     17.2mA     22.7mA
1.2V      -12.77mA   -8.446mA   -16.81mA
3.7V      -17.91mA   -16.47mA   -24.61mA
3.8V      -18.14mA   -33.44mA   -24.67mA
4.2V      -34.83mA   -219.7mA   -25.75mA
4.3V      -79.53mA   -266.7mA   -28.82mA
4.5V      -202.8mA   -361.2mA   -42.16mA
4.7V      -327.1mA   -456.4mA   -104.6mA
4.9V      -452.4mA   -552.1mA   -260.7mA
5.1V      -578.3mA   -648.3mA   -417.9mA
6.6V      -1.534A    -1.38A     -1.61A
[GND_clamp]
-3.3V     -1.517A    -1.206A    -1.849A
-1.2V     -185.7mA   -194.8mA   -182.8mA
-1.1V     -124mA     -148.1mA   -104.8mA
-1V       -62.54mA   -101.7mA   -33.61mA
-900mV    -17.04mA   -55.16mA   -17.04mA
-800mV    -8.525mA   -13.45mA   -8.525mA
-700mV    -3.999mA   -3.999mA   -3.999mA
-600mV    -1.289mA   -1.289mA   -1.289mA
-500mV    -219.7uA   -252.6uA   -203.6uA
-400mV    -15.61uA   -27.49uA   -11.15uA
3.3V      3.373nA    3.373nA    17.05nA
[POWER_clamp]
-3.3V     1.027A     840.1mA    1.22A
-1.1V     112.7mA    112.7mA    112.7mA
-1V       80.41mA    80.41mA    80.41mA
-800mV    17.08mA    17.08mA    17.08mA
-700mV    4.947mA    4.947mA    5.794mA
-600mV    1.98mA     1.98mA     2.27mA
-500mV    443.8uA    443.8uA    443.8uA
-400mV    34.78uA    34.78uA    34.78uA
0V        3.373nA    3.373nA    57.43nA
[Ramp]
dV/dt_r   0.5135/0.2406n   0.3276/0.3187n   0.7026/0.2044n
dV/dt_f   0.5346/0.3177n   0.3144/0.4244n   0.7968/0.2646n
R_load = 50.0000
[Rising Waveform]
R_fixture = 50.0000
V_fixture = 0.000
V_fixture_min = 0.000
V_fixture_max = 0.000
0s        0V         0V         0V
900ps     173.3uV    -1.53uV    -11.16mV
1.05ns    404.1uV    -3.481uV   173.2mV
1.2ns     -6.434mV   -3.271uV   786.1mV
1.35ns    5.755mV    54.49uV    1.05V
1.65ns    644.4mV    309.3uV    1.16V
2.1ns     846.2mV    7.359mV    1.171V
2.55ns    855.4mV    444.8mV    1.171V
3ns       855.8mV    537.6mV    1.171V
14.85ns   855.8mV    546.1mV    1.171V
[Rising Waveform]
R_fixture = 50.0000
V_fixture = 3.3000
V_fixture_min = 2.9700
V_fixture_max = 3.6300
0s        2.409V     2.446V     2.302V
900ps     2.408V     2.446V     2.383V
1.05ns    2.399V     2.446V     3.107V
1.2ns     2.444V     2.446V     3.55V
1.35ns    2.752V     2.446V     3.617V
1.5ns     3.157V     2.444V     3.628V
1.8ns     3.293V     2.45V      3.63V
2.25ns    3.3V       2.878V     3.63V
2.7ns     3.3V       2.966V     3.63V
14.85ns   3.3V       2.97V      3.63V
[Falling Waveform]
R_fixture = 50.0000
V_fixture = 0.000
V_fixture_min = 0.000
V_fixture_max = 0.000
0s        855.8mV    546.1mV    1.171V
600ps     857.9mV    545.9mV    1.165V
750ps     862.5mV    545.9mV    801.5mV
900ps     803.4mV    546.8mV    252.9mV
1.05ns    422.1mV    549.7mV    48.96mV
1.2ns     141.4mV    552.5mV    10.44mV
1.5ns     13.98mV    415.7mV    624.9uV
1.8ns     1.725mV    72.06mV    41.5uV
2.25ns    57.74uV    8.991mV    422.4nV
14.85ns   0V         0V         0V
[Falling Waveform]
R_fixture = 50.0000
V_fixture = 3.3000
V_fixture_min = 2.9700
V_fixture_max = 3.6300
0s        3.3V       2.97V      3.63V
900ps     3.308V     2.969V     3.648V
1.05ns    3.327V     2.969V     3.249V
1.2ns     3.316V     2.97V      2.743V
1.35ns    3.138V     2.972V     2.475V
1.65ns    2.612V     2.989V     2.322V
1.95ns    2.445V     2.954V     2.304V
2.55ns    2.41V      2.534V     2.302V
3ns       2.409V     2.457V     2.302V
14.85ns   2.409V     2.446V     2.302V
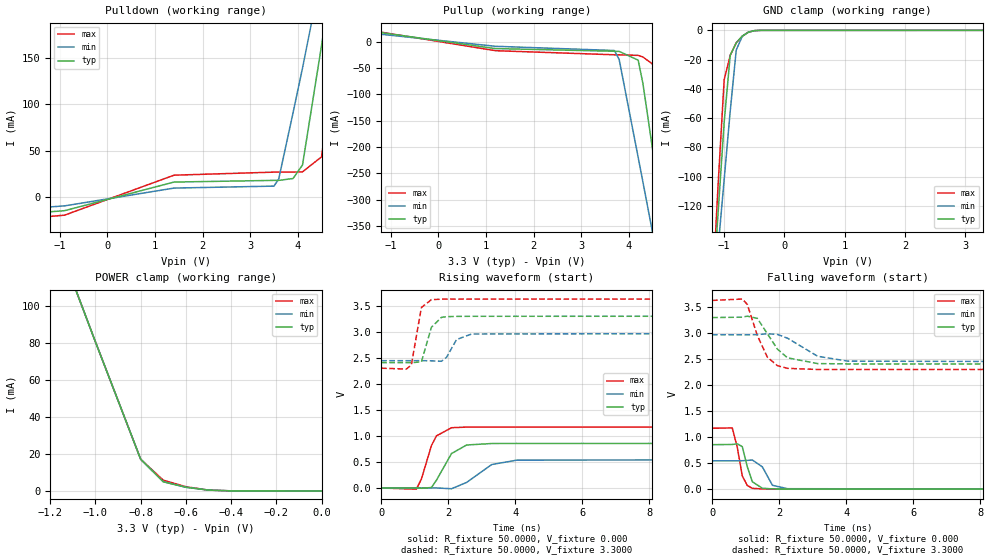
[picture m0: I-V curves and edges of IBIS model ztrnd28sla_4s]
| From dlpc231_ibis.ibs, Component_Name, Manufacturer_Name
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| Model ztrnd28sla_4s
[Model]   ztrnd28sla_4s
Model_type   I/O
Polarity   Non-Inverting
Enable   Active-High
Vinl = 0.8000V
Vinh = 2.0000V
Vmeas = 1.5000V
Cref =50.0000pF
Rref = 0.5000k
Vref =  0.000V
C_comp   0.7000pF   0.7000pF   0.7000pF
[Temperature Range]   25.0000   0.1240k   -40.0000
[Voltage Range]   3.3000V   2.9700V   3.6300V
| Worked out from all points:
|   slope of the pulldown table from 0 to 0.495 V, typ, clamps not added: 62.2 ohm
|   slope of the pullup table from 0 to 0.495 V, typ, clamps not added: 76.9 ohm
|   GND clamp passes 1 mA (typ) near -0.57 V on its own axis
|   POWER clamp passes 1 mA (typ) near -0.54 V on its own axis
|   rising waveform, R_fixture 50.0000, V_fixture 0.000: 20-80 % time 473ps typ, 698ps min, 370ps max; typ from 0 V to 0.856 V
|   rising waveform, R_fixture 50.0000, V_fixture 3.3000: 20-80 % time 245ps typ, 291ps min, 218ps max; typ from 2.41 V to 3.3 V
|   falling waveform, R_fixture 50.0000, V_fixture 0.000: 20-80 % time 233ps typ, 271ps min, 219ps max; typ from 0.856 V to 0 V
|   falling waveform, R_fixture 50.0000, V_fixture 3.3000: 20-80 % time 586ps typ, 836ps min, 477ps max; typ from 3.3 V to 2.41 V
[Pulldown]
-3.3V     -24mA      -18mA      -30mA
-900mV    -14.61mA   -9.45mA    -19.44mA
1.4V      16.19mA    9.709mA    23.59mA
3.5V      17.99mA    11.83mA    26.87mA
3.6V      18mA       19.49mA    26.89mA
3.9V      19.99mA    90.45mA    26.94mA
4.1V      34.59mA    138.9mA    27.17mA
4.5V      163.2mA    241.6mA    43.34mA
4.7V      230.6mA    296.2mA    120.3mA
4.9V      300.4mA    353.7mA    204.4mA
5.1V      373.1mA    414.9mA    291.2mA
6.6V      1.049A     968.3mA    1.056A
[Pullup]
-3.3V     15mA       18.6mA     10mA
-1.5V     21.2mA     17.2mA     22.7mA
1.2V      -12.77mA   -8.446mA   -16.81mA
3.7V      -17.91mA   -16.47mA   -24.61mA
3.8V      -18.14mA   -33.44mA   -24.67mA
4.2V      -34.83mA   -219.7mA   -25.75mA
4.3V      -79.53mA   -266.7mA   -28.82mA
4.5V      -202.8mA   -361.2mA   -42.16mA
4.7V      -327.1mA   -456.4mA   -104.6mA
4.9V      -452.4mA   -552.1mA   -260.7mA
5.1V      -578.3mA   -648.3mA   -417.9mA
6.6V      -1.534A    -1.38A     -1.61A
[GND_clamp]
-3.3V     -1.517A    -1.206A    -1.849A
-1.2V     -185.7mA   -194.8mA   -182.8mA
-1.1V     -124mA     -148.1mA   -104.8mA
-1V       -62.54mA   -101.7mA   -33.61mA
-900mV    -17.04mA   -55.16mA   -17.04mA
-800mV    -8.525mA   -13.45mA   -8.525mA
-700mV    -3.999mA   -3.999mA   -3.999mA
-600mV    -1.289mA   -1.289mA   -1.289mA
-500mV    -219.7uA   -252.6uA   -203.6uA
-400mV    -15.61uA   -27.49uA   -11.15uA
3.3V      3.373nA    3.373nA    17.05nA
[POWER_clamp]
-3.3V     1.027A     840.1mA    1.22A
-1.1V     112.7mA    112.7mA    112.7mA
-1V       80.41mA    80.41mA    80.41mA
-800mV    17.08mA    17.08mA    17.08mA
-700mV    4.947mA    4.947mA    5.794mA
-600mV    1.98mA     1.98mA     2.27mA
-500mV    443.8uA    443.8uA    443.8uA
-400mV    34.78uA    34.78uA    34.78uA
0V        3.373nA    3.373nA    57.43nA
[Ramp]
dV/dt_r   0.5135/0.4666n   0.3276/0.6893n   0.7026/0.3567n
dV/dt_f   0.5346/0.5866n   0.3144/0.8333n   0.7968/0.4698n
R_load = 50.0000
[Rising Waveform]
R_fixture = 50.0000
V_fixture = 0.000
V_fixture_min = 0.000
V_fixture_max = 0.000
0s        0V         0V         0V
1.05ns    971.3uV    -6.119uV   -22.53mV
1.2ns     -5.624mV   -7.537uV   171.8mV
1.5ns     8.957mV    467.8uV    815.5mV
1.65ns    150.2mV    738.1uV    1.002V
2.1ns     662.4mV    -14.51mV   1.158V
2.55ns    826.2mV    106.8mV    1.17V
3.3ns     854.8mV    451mV      1.171V
4.05ns    855.8mV    534.9mV    1.171V
14.85ns   855.8mV    546.1mV    1.171V
[Rising Waveform]
R_fixture = 50.0000
V_fixture = 3.3000
V_fixture_min = 2.9700
V_fixture_max = 3.6300
0s        2.409V     2.446V     2.302V
750ps     2.409V     2.446V     2.285V
900ps     2.408V     2.446V     2.362V
1.2ns     2.423V     2.447V     3.468V
1.5ns     3.089V     2.443V     3.619V
1.8ns     3.278V     2.435V     3.628V
1.95ns    3.291V     2.51V      3.629V
2.25ns    3.297V     2.853V     3.629V
2.7ns     3.299V     2.959V     3.63V
14.85ns   3.3V       2.97V      3.63V
[Falling Waveform]
R_fixture = 50.0000
V_fixture = 0.000
V_fixture_min = 0.000
V_fixture_max = 0.000
0s        855.8mV    546.1mV    1.171V
600ps     859.5mV    545.8mV    1.178V
750ps     872.4mV    545.7mV    807.4mV
900ps     818.2mV    547mV      254.8mV
1.05ns    430.9mV    552.9mV    70.71mV
1.2ns     142.5mV    561.6mV    16.38mV
1.5ns     17.77mV    429.1mV    4.294mV
1.8ns     5.075mV    74.81mV    1.412mV
2.25ns    1.512mV    8.841mV    220.5uV
14.85ns   0V         0V         0V
[Falling Waveform]
R_fixture = 50.0000
V_fixture = 3.3000
V_fixture_min = 2.9700
V_fixture_max = 3.6300
0s        3.3V       2.97V      3.63V
900ps     3.308V     2.969V     3.656V
1.05ns    3.327V     2.969V     3.554V
1.35ns    3.285V     2.972V     2.954V
1.65ns    2.988V     2.989V     2.537V
1.95ns    2.693V     2.976V     2.375V
2.25ns    2.526V     2.904V     2.323V
3.15ns    2.415V     2.556V     2.302V
4.05ns    2.409V     2.462V     2.302V
14.85ns   2.409V     2.446V     2.302V
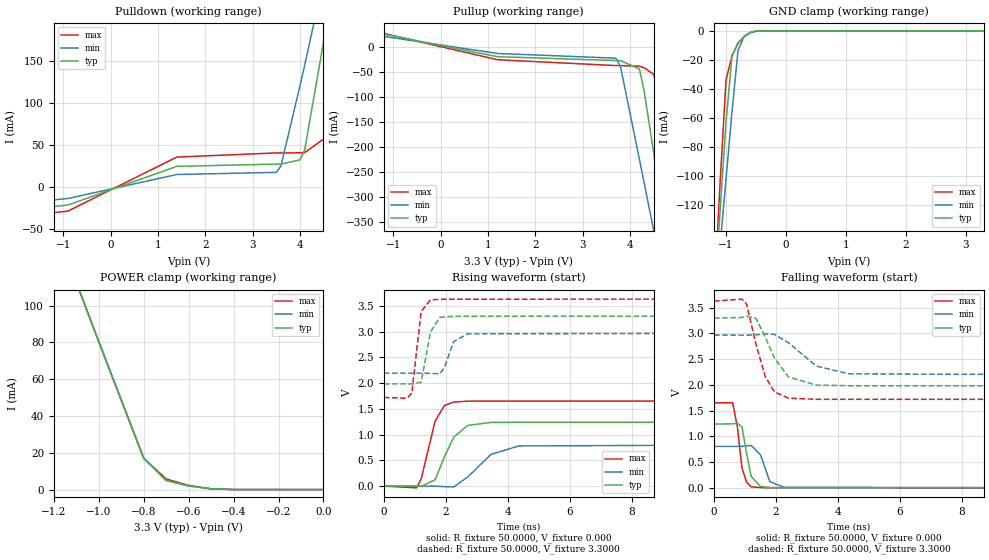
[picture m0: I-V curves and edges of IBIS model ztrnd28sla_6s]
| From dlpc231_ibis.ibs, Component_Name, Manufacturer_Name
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| Model ztrnd28sla_6s
[Model]   ztrnd28sla_6s
Model_type   I/O
Polarity   Non-Inverting
Enable   Active-High
Vinl = 0.8000V
Vinh = 2.0000V
Vmeas = 1.5000V
Cref =50.0000pF
Rref = 0.5000k
Vref =  0.000V
C_comp   0.7000pF   0.7000pF   0.7000pF
[Temperature Range]   25.0000   0.1240k   -40.0000
[Voltage Range]   3.3000V   2.9700V   3.6300V
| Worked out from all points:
|   slope of the pulldown table from 0 to 0.495 V, typ, clamps not added: 41.7 ohm
|   slope of the pullup table from 0 to 0.495 V, typ, clamps not added: 51.3 ohm
|   GND clamp passes 1 mA (typ) near -0.57 V on its own axis
|   POWER clamp passes 1 mA (typ) near -0.54 V on its own axis
|   rising waveform, R_fixture 50.0000, V_fixture 0.000: 20-80 % time 568ps typ, 865ps min, 419ps max; typ from 0 V to 1.24 V
|   rising waveform, R_fixture 50.0000, V_fixture 3.3000: 20-80 % time 249ps typ, 283ps min, 219ps max; typ from 1.98 V to 3.3 V
|   falling waveform, R_fixture 50.0000, V_fixture 0.000: 20-80 % time 236ps typ, 275ps min, 222ps max; typ from 1.24 V to 0 V
|   falling waveform, R_fixture 50.0000, V_fixture 3.3000: 20-80 % time 664ps typ, 950ps min, 516ps max; typ from 3.3 V to 1.98 V
[Pulldown]
-3.3V     -36mA      -27mA      -45mA
-900mV    -21.82mA   -14.1mA    -29.03mA
1.4V      24.15mA    14.48mA    35.22mA
3.5V      26.85mA    17.02mA    40.14mA
3.6V      26.87mA    24.59mA    40.16mA
4V        31.8mA     119.5mA    40.29mA
4.1V      43.22mA    144mA      40.49mA
4.5V      171.8mA    246.7mA    56.57mA
4.7V      239.3mA    301.4mA    133.3mA
4.9V      309.2mA    358.9mA    217.5mA
5.1V      382mA      420.2mA    304.4mA
6.6V      1.06A      974.8mA    1.071A
[Pullup]
-3.3V     22mA       27.8mA     15mA
-1.5V     31.7mA     25.8mA     34mA
1.2V      -19.14mA   -12.66mA   -25.2mA
3.7V      -26.85mA   -22.12mA   -36.91mA
3.8V      -27.1mA    -38.91mA   -36.99mA
4.2V      -43.73mA   -225.2mA   -38.15mA
4.3V      -88.01mA   -272.2mA   -41.21mA
4.5V      -211.3mA   -366.7mA   -54.54mA
4.7V      -335.7mA   -461.9mA   -116.1mA
4.9V      -460.9mA   -557.6mA   -272.3mA
5.1V      -586.9mA   -653.8mA   -429.5mA
6.6V      -1.543A    -1.386A    -1.621A
[GND_clamp]
-3.3V     -1.517A    -1.206A    -1.849A
-1.2V     -185.7mA   -194.8mA   -182.8mA
-1.1V     -124mA     -148.1mA   -104.8mA
-1V       -62.54mA   -101.7mA   -33.61mA
-900mV    -17.04mA   -55.16mA   -17.04mA
-800mV    -8.525mA   -13.45mA   -8.525mA
-700mV    -3.999mA   -3.999mA   -3.999mA
-600mV    -1.289mA   -1.289mA   -1.289mA
-500mV    -219.7uA   -252.6uA   -203.6uA
-400mV    -15.61uA   -27.49uA   -11.15uA
3.3V      3.373nA    3.373nA    17.05nA
[POWER_clamp]
-3.3V     1.027A     840.1mA    1.22A
-1.1V     112.7mA    112.7mA    112.7mA
-1V       80.41mA    80.41mA    80.41mA
-800mV    17.08mA    17.08mA    17.08mA
-700mV    4.947mA    4.947mA    5.794mA
-600mV    1.98mA     1.98mA     2.27mA
-500mV    443.8uA    443.8uA    443.8uA
-400mV    34.78uA    34.78uA    34.78uA
0V        3.373nA    3.373nA    57.43nA
[Ramp]
dV/dt_r   0.7440/0.5575n   0.4834/0.8551n   0.9906/0.4072n
dV/dt_f   0.7896/0.6637n   0.4662/0.9502n   1.1454/0.5090n
R_load = 50.0000
[Rising Waveform]
R_fixture = 50.0000
V_fixture = 0.000
V_fixture_min = 0.000
V_fixture_max = 0.000
0s        0V         0V         0V
1.05ns    980.5uV    -7.218uV   -34.04mV
1.2ns     -7.843mV   -8.771uV   136.7mV
1.65ns    122.8mV    774.7uV    1.261V
1.95ns    566.6mV    -11.01mV   1.563V
2.25ns    948.2mV    -17.19mV   1.632V
2.7ns     1.178V     174.8mV    1.649V
3.45ns    1.236V     613.7mV    1.651V
4.35ns    1.24V      779.7mV    1.651V
14.85ns   1.24V      805.7mV    1.651V
[Rising Waveform]
R_fixture = 50.0000
V_fixture = 3.3000
V_fixture_min = 2.9700
V_fixture_max = 3.6300
0s        1.984V     2.193V     1.721V
750ps     1.985V     2.193V     1.706V
900ps     1.983V     2.193V     1.808V
1.2ns     2.015V     2.193V     3.39V
1.5ns     2.991V     2.187V     3.616V
1.8ns     3.272V     2.182V     3.626V
1.95ns    3.287V     2.299V     3.628V
2.25ns    3.295V     2.807V     3.629V
2.7ns     3.298V     2.956V     3.629V
14.85ns   3.3V       2.97V      3.63V
[Falling Waveform]
R_fixture = 50.0000
V_fixture = 0.000
V_fixture_min = 0.000
V_fixture_max = 0.000
0s        1.24V      805.7mV    1.651V
600ps     1.244V     805.5mV    1.655V
750ps     1.257V     805.3mV    1.192V
900ps     1.184V     806.9mV    385.6mV
1.05ns    659.5mV    814.2mV    107.9mV
1.2ns     220.9mV    824.5mV    20.06mV
1.5ns     24.9mV     638.3mV    5.191mV
1.8ns     6.078mV    119.2mV    2.323mV
2.25ns    2.42mV     12.49mV    522uV
14.85ns   0V         0V         0V
[Falling Waveform]
R_fixture = 50.0000
V_fixture = 3.3000
V_fixture_min = 2.9700
V_fixture_max = 3.6300
0s        3.3V       2.97V      3.63V
900ps     3.311V     2.969V     3.668V
1.05ns    3.334V     2.969V     3.571V
1.35ns    3.295V     2.973V     2.793V
1.65ns    2.931V     2.995V     2.166V
1.95ns    2.52V      2.981V     1.863V
2.4ns     2.155V     2.821V     1.744V
3.3ns     1.997V     2.366V     1.721V
4.35ns    1.985V     2.216V     1.721V
14.85ns   1.984V     2.193V     1.721V
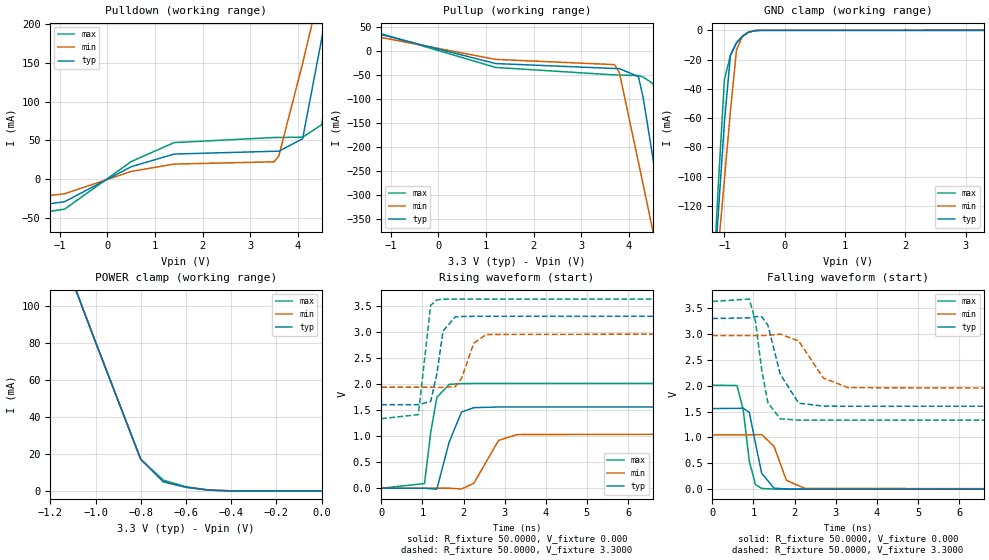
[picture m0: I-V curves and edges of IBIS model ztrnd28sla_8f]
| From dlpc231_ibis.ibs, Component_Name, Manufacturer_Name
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| Model ztrnd28sla_8f
[Model]   ztrnd28sla_8f
Model_type   I/O
Polarity   Non-Inverting
Enable   Active-High
Vinl = 0.8000V
Vinh = 2.0000V
Vmeas = 1.5000V
Cref =50.0000pF
Rref = 0.5000k
Vref =  0.000V
C_comp   0.7000pF   0.7000pF   0.7000pF
[Temperature Range]   25.0000   0.1240k   -40.0000
[Voltage Range]   3.3000V   2.9700V   3.6300V
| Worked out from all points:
|   slope of the pulldown table from 0 to 0.495 V, typ, clamps not added: 31.2 ohm
|   slope of the pullup table from 0 to 0.495 V, typ, clamps not added: 38.5 ohm
|   GND clamp passes 1 mA (typ) near -0.57 V on its own axis
|   POWER clamp passes 1 mA (typ) near -0.54 V on its own axis
|   rising waveform, R_fixture 50.0000, V_fixture 0.000: 20-80 % time 280ps typ, 432ps min, 222ps max; typ from 0 V to 1.56 V
|   rising waveform, R_fixture 50.0000, V_fixture 3.3000: 20-80 % time 210ps typ, 274ps min, 197ps max; typ from 1.6 V to 3.3 V
|   falling waveform, R_fixture 50.0000, V_fixture 0.000: 20-80 % time 240ps typ, 287ps min, 217ps max; typ from 1.56 V to 0 V
|   falling waveform, R_fixture 50.0000, V_fixture 3.3000: 20-80 % time 369ps typ, 533ps min, 260ps max; typ from 3.3 V to 1.6 V
[Pulldown]
-3.3V     -49mA      -37mA      -60mA
-900mV    -29.14mA   -18.84mA   -38.75mA
500mV     16mA       9.925mA    22.62mA
1.4V      32.28mA    19.36mA    47.04mA
3.5V      35.89mA    22.32mA    53.63mA
3.6V      35.91mA    29.8mA     53.66mA
4.1V      52.02mA    149.2mA    54.04mA
4.5V      180.7mA    252mA      70.05mA
4.7V      248.2mA    306.7mA    146.4mA
4.9V      318.2mA    364.2mA    230.7mA
5.1V      391.1mA    425.6mA    317.8mA
6.6V      1.071A     981.4mA    1.087A
[Pullup]
-3.3V     29mA       37.1mA     20mA
-1.5V     42.2mA     34.4mA     45.3mA
1.2V      -25.52mA   -16.88mA   -33.59mA
3.7V      -35.8mA    -27.78mA   -49.22mA
3.8V      -36.07mA   -44.39mA   -49.33mA
4.2V      -52.63mA   -230.7mA   -50.56mA
4.3V      -96.51mA   -277.7mA   -53.61mA
4.5V      -219.8mA   -372.2mA   -66.93mA
4.7V      -344.2mA   -467.4mA   -127.7mA
4.9V      -469.5mA   -563.1mA   -283.9mA
5.1V      -595.5mA   -659.4mA   -441.1mA
6.6V      -1.552A    -1.391A    -1.633A
[GND_clamp]
-3.3V     -1.517A    -1.206A    -1.849A
-1.2V     -185.7mA   -194.8mA   -182.8mA
-1.1V     -124mA     -148.1mA   -104.8mA
-1V       -62.54mA   -101.7mA   -33.61mA
-900mV    -17.04mA   -55.16mA   -17.04mA
-800mV    -8.525mA   -13.45mA   -8.525mA
-700mV    -3.999mA   -3.999mA   -3.999mA
-600mV    -1.289mA   -1.289mA   -1.289mA
-500mV    -219.7uA   -252.6uA   -203.6uA
-400mV    -15.61uA   -27.49uA   -11.15uA
3.3V      3.373nA    3.373nA    17.05nA
[POWER_clamp]
-3.3V     1.027A     840.1mA    1.22A
-1.1V     112.7mA    112.7mA    112.7mA
-1V       80.41mA    80.41mA    80.41mA
-800mV    17.08mA    17.08mA    17.08mA
-700mV    4.947mA    4.947mA    5.794mA
-600mV    1.98mA     1.98mA     2.27mA
-500mV    443.8uA    443.8uA    443.8uA
-400mV    34.78uA    34.78uA    34.78uA
0V        3.373nA    3.373nA    57.43nA
[Ramp]
dV/dt_r   0.9354/0.2774n   0.6288/0.4207n   1.2060/0.2027n
dV/dt_f   1.0176/0.3618n   0.6192/0.5273n   1.3776/0.2537n
R_load = 50.0000
[Rising Waveform]
R_fixture = 50.0000
V_fixture = 0.000
V_fixture_min = 0.000
V_fixture_max = 0.000
0s        0V         0V         0V
1.05ns    272.7uV    -4.478uV   89.53mV
1.2ns     -9.996mV   -4.152uV   1.063V
1.35ns    -18.03mV   72.47uV    1.742V
1.65ns    885mV      240.4uV    1.993V
1.95ns    1.462V     -13.98mV   2.008V
2.25ns    1.546V     94.01mV    2.01V
2.85ns    1.559V     916.2mV    2.01V
3.3ns     1.559V     1.03V      2.01V
14.85ns   1.559V     1.048V     2.01V
[Rising Waveform]
R_fixture = 50.0000
V_fixture = 3.3000
V_fixture_min = 2.9700
V_fixture_max = 3.6300
0s        1.604V     1.938V     1.334V
900ps     1.603V     1.938V     1.413V
1.2ns     1.666V     1.938V     3.508V
1.35ns    2.187V     1.938V     3.614V
1.5ns     3.017V     1.934V     3.627V
1.8ns     3.288V     1.951V     3.629V
1.95ns    3.296V     2.105V     3.63V
2.25ns    3.299V     2.784V     3.63V
2.55ns    3.3V       2.95V      3.63V
14.85ns   3.3V       2.97V      3.63V
[Falling Waveform]
R_fixture = 50.0000
V_fixture = 0.000
V_fixture_min = 0.000
V_fixture_max = 0.000
0s        1.559V     1.048V     2.01V
600ps     1.562V     1.048V     2.004V
750ps     1.566V     1.048V     1.537V
900ps     1.482V     1.049V     532.2mV
1.05ns    881.7mV    1.053V     89.01mV
1.2ns     304.9mV    1.057V     13.96mV
1.5ns     20.74mV    827.7mV    2.018mV
1.8ns     4.258mV    171.2mV    246.6uV
2.25ns    383.6uV    14.98mV    11.4uV
14.85ns   0V         0V         0V
[Falling Waveform]
R_fixture = 50.0000
V_fixture = 3.3000
V_fixture_min = 2.9700
V_fixture_max = 3.6300
0s        3.3V       2.97V      3.63V
900ps     3.313V     2.969V     3.676V
1.05ns    3.337V     2.969V     3.237V
1.2ns     3.336V     2.97V      2.307V
1.35ns    3.173V     2.974V     1.67V
1.65ns    2.226V     2.998V     1.36V
2.1ns     1.662V     2.865V     1.335V
2.7ns     1.606V     2.15V      1.334V
3.3ns     1.604V     1.963V     1.334V
14.85ns   1.604V     1.938V     1.334V
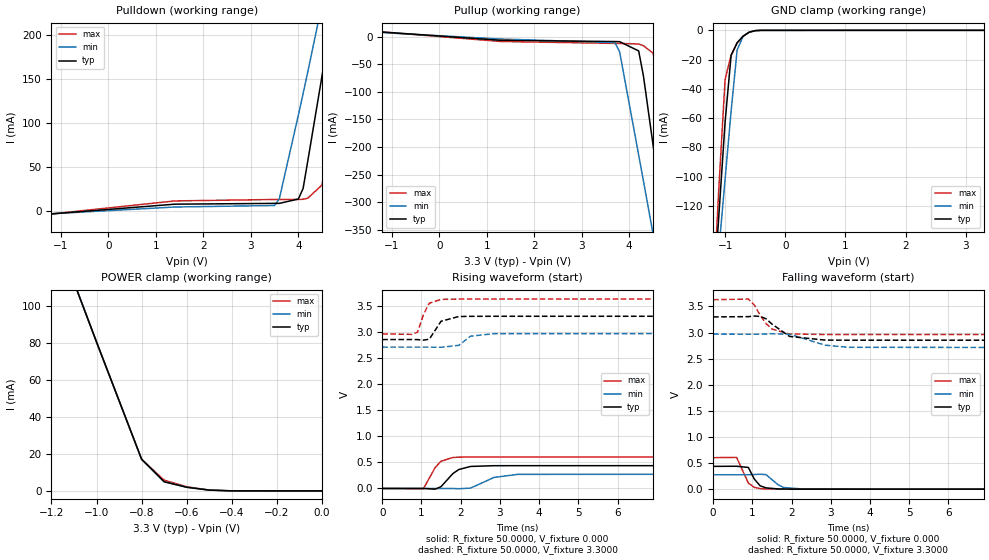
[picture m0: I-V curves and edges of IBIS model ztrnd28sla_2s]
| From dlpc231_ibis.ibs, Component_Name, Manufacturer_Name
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| Model ztrnd28sla_2s
[Model]   ztrnd28sla_2s
Model_type   I/O
Polarity   Non-Inverting
Enable   Active-High
Vinl = 0.8000V
Vinh = 2.0000V
Vmeas = 1.5000V
Cref =50.0000pF
Rref = 0.5000k
Vref =  0.000V
C_comp   0.7000pF   0.7000pF   0.7000pF
[Temperature Range]   25.0000   0.1240k   -40.0000
[Voltage Range]   3.3000V   2.9700V   3.6300V
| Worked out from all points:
|   slope of the pulldown table from 0 to 0.495 V, typ, clamps not added: 125 ohm
|   slope of the pullup table from 0 to 0.495 V, typ, clamps not added: 154 ohm
|   GND clamp passes 1 mA (typ) near -0.57 V on its own axis
|   POWER clamp passes 1 mA (typ) near -0.54 V on its own axis
|   rising waveform, R_fixture 50.0000, V_fixture 0.000: 20-80 % time 364ps typ, 503ps min, 304ps max; typ from 0 V to 0.437 V
|   rising waveform, R_fixture 50.0000, V_fixture 3.3000: 20-80 % time 237ps typ, 270ps min, 218ps max; typ from 2.85 V to 3.3 V
|   falling waveform, R_fixture 50.0000, V_fixture 0.000: 20-80 % time 228ps typ, 264ps min, 215ps max; typ from 0.437 V to 0 V
|   falling waveform, R_fixture 50.0000, V_fixture 3.3000: 20-80 % time 472ps typ, 639ps min, 385ps max; typ from 3.3 V to 2.85 V
[Pulldown]
-3.3V     -12mA      -9mA       -15mA
1.4V      8.055mA    4.828mA    11.75mA
3.5V      8.95mA     6.531mA    13.38mA
3.6V      8.957mA    14.28mA    13.39mA
4V        13.9mA     109.2mA    13.43mA
4.1V      25.79mA    133.7mA    13.62mA
4.2V      57.48mA    158.7mA    14.96mA
4.5V      154.3mA    236.3mA    29.88mA
4.7V      221.6mA    290.9mA    107.1mA
4.9V      291.4mA    348.3mA    191.1mA
5.1V      364.1mA    409.5mA    277.8mA
6.6V      1.038A     961.6mA    1.04A
[Pullup]
-3.3V     7mA        9.3mA      5mA
-1.7V     11.3mA     9.5mA      11.8mA
1.3V      -6.71mA    -4.429mA   -8.856mA
3.7V      -8.962mA   -10.81mA   -12.3mA
3.8V      -9.181mA   -27.96mA   -12.33mA
4.2V      -25.94mA   -214.3mA   -13.34mA
4.3V      -71.03mA   -261.2mA   -16.42mA
4.5V      -194.2mA   -355.7mA   -29.77mA
4.7V      -318.6mA   -450.9mA   -93.02mA
4.9V      -443.8mA   -546.6mA   -249.2mA
5.1V      -569.7mA   -642.7mA   -406.3mA
6.6V      -1.526A    -1.374A    -1.598A
[GND_clamp]
-3.3V     -1.517A    -1.206A    -1.849A
-1.2V     -185.7mA   -194.8mA   -182.8mA
-1.1V     -124mA     -148.1mA   -104.8mA
-1V       -62.54mA   -101.7mA   -33.61mA
-900mV    -17.04mA   -55.16mA   -17.04mA
-800mV    -8.525mA   -13.45mA   -8.525mA
-700mV    -3.999mA   -3.999mA   -3.999mA
-600mV    -1.289mA   -1.289mA   -1.289mA
-500mV    -219.7uA   -252.6uA   -203.6uA
-400mV    -15.61uA   -27.49uA   -11.15uA
3.3V      3.373nA    3.373nA    17.05nA
[POWER_clamp]
-3.3V     1.027A     840.1mA    1.22A
-1.1V     112.7mA    112.7mA    112.7mA
-1V       80.41mA    80.41mA    80.41mA
-800mV    17.08mA    17.08mA    17.08mA
-700mV    4.947mA    4.947mA    5.794mA
-600mV    1.98mA     1.98mA     2.27mA
-500mV    443.8uA    443.8uA    443.8uA
-400mV    34.78uA    34.78uA    34.78uA
0V        3.373nA    3.373nA    57.43nA
[Ramp]
dV/dt_r   0.2620/0.3511n   0.1658/0.4992n   0.3620/0.2820n
dV/dt_f   0.2676/0.4613n   0.1566/0.6413n   0.4002/0.3770n
R_load = 50.0000
[Rising Waveform]
R_fixture = 50.0000
V_fixture = 0.000
V_fixture_min = 0.000
V_fixture_max = 0.000
0s        0V         0V         0V
1.05ns    819.8uV    -4.414uV   -5.727mV
1.35ns    -13.42mV   55.12uV    403mV
1.5ns     35.29mV    333.9uV    522mV
1.8ns     284.6mV    -1.154mV   593.3mV
1.95ns    362.6mV    -5.238mV   600mV
2.25ns    422mV      6.652mV    603mV
2.85ns    436.4mV    211.4mV    603.4mV
3.45ns    436.7mV    270mV      603.4mV
14.85ns   436.7mV    276.4mV    603.4mV
[Rising Waveform]
R_fixture = 50.0000
V_fixture = 3.3000
V_fixture_min = 2.9700
V_fixture_max = 3.6300
0s        2.854V     2.709V     2.963V
750ps     2.854V     2.709V     2.953V
900ps     2.853V     2.709V     2.995V
1.05ns    2.843V     2.709V     3.332V
1.2ns     2.861V     2.709V     3.551V
1.5ns     3.205V     2.706V     3.624V
1.95ns    3.295V     2.743V     3.629V
2.25ns    3.299V     2.919V     3.63V
2.85ns    3.3V       2.967V     3.63V
14.85ns   3.3V       2.97V      3.63V
[Falling Waveform]
R_fixture = 50.0000
V_fixture = 0.000
V_fixture_min = 0.000
V_fixture_max = 0.000
0s        436.7mV    276.4mV    603.4mV
600ps     439.1mV    276.2mV    609.1mV
900ps     415.6mV    277mV      116.7mV
1.05ns    195mV      280.8mV    34.56mV
1.2ns     64.2mV     286.2mV    10.34mV
1.35ns    24.8mV     278.5mV    4.554mV
1.65ns    5.094mV    88.63mV    932.9uV
1.8ns     2.876mV    31.61mV    406.1uV
2.25ns    452.1uV    4.692mV    34.21uV
14.85ns   0V         0V         0V
[Falling Waveform]
R_fixture = 50.0000
V_fixture = 3.3000
V_fixture_min = 2.9700
V_fixture_max = 3.6300
0s        3.3V       2.97V      3.63V
900ps     3.305V     2.969V     3.642V
1.05ns    3.317V     2.969V     3.529V
1.2ns     3.309V     2.969V     3.334V
1.35ns    3.264V     2.971V     3.172V
1.5ns     3.164V     2.978V     3.069V
1.95ns    2.926V     2.97V      2.973V
2.85ns    2.856V     2.759V     2.963V
3.45ns    2.854V     2.718V     2.963V
14.85ns   2.854V     2.709V     2.963V
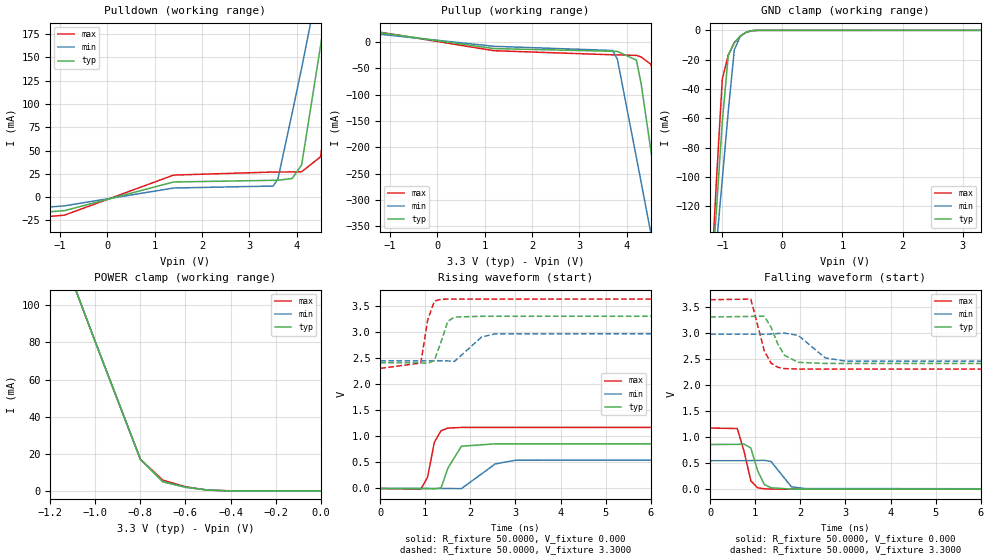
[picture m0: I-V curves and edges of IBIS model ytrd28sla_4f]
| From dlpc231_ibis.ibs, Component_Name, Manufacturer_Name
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| Model ytrd28sla_4f
[Model]   ytrd28sla_4f
Model_type   3-state
Polarity   Non-Inverting
Enable   Active-High
Vmeas = 1.5000V
Cref =50.0000pF
Rref = 0.5000k
Vref =  0.000V
C_comp   0.7000pF   0.7000pF   0.7000pF
[Temperature Range]   25.0000   0.1240k   -40.0000
[Voltage Range]   3.3000V   2.9700V   3.6300V
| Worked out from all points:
|   slope of the pulldown table from 0 to 0.495 V, typ, clamps not added: 62.2 ohm
|   slope of the pullup table from 0 to 0.495 V, typ, clamps not added: 76.9 ohm
|   GND clamp passes 1 mA (typ) near -0.57 V on its own axis
|   POWER clamp passes 1 mA (typ) near -0.54 V on its own axis
|   rising waveform, R_fixture 50.0000, V_fixture 0.000: 20-80 % time 228ps typ, 313ps min, 180ps max; typ from 0 V to 0.856 V
|   rising waveform, R_fixture 50.0000, V_fixture 3.3000: 20-80 % time 212ps typ, 259ps min, 178ps max; typ from 2.41 V to 3.3 V
|   falling waveform, R_fixture 50.0000, V_fixture 0.000: 20-80 % time 217ps typ, 265ps min, 203ps max; typ from 0.856 V to 0 V
|   falling waveform, R_fixture 50.0000, V_fixture 3.3000: 20-80 % time 297ps typ, 415ps min, 263ps max; typ from 3.3 V to 2.41 V
[Pulldown]
-3.3V     -24mA      -19mA      -30mA
-900mV    -14.61mA   -9.45mA    -19.44mA
1.4V      16.19mA    9.709mA    23.59mA
3.5V      17.99mA    11.83mA    26.87mA
3.6V      18mA       19.48mA    26.89mA
3.9V      19.99mA    90.29mA    26.94mA
4.1V      34.58mA    138.6mA    27.17mA
4.5V      162.9mA    241mA      43.33mA
4.7V      230.1mA    295.4mA    120.2mA
4.9V      299.8mA    352.8mA    204.1mA
5.1V      372.3mA    413.8mA    290.7mA
6.6V      1.047A     966.1mA    1.054A
[Pullup]
-3.3V     14mA       18.5mA     10mA
-1.5V     21.1mA     17.2mA     22.7mA
1.2V      -12.77mA   -8.446mA   -16.81mA
3.7V      -17.91mA   -16.42mA   -24.61mA
3.8V      -18.14mA   -33.36mA   -24.67mA
4.2V      -34.7mA    -219.5mA   -25.73mA
4.3V      -79.36mA   -266.4mA   -28.76mA
4.5V      -202.5mA   -360.7mA   -42mA
4.7V      -326.7mA   -455.7mA   -104.3mA
4.9V      -451.8mA   -551.3mA   -260.4mA
5.1V      -577.6mA   -647.4mA   -417.4mA
6.6V      -1.532A    -1.378A    -1.608A
[GND_clamp]
-3.3V     -1.515A    -1.204A    -1.847A
-1.2V     -185.5mA   -194.5mA   -182.5mA
-1.1V     -123.8mA   -147.9mA   -104.5mA
-1V       -62.37mA   -101.6mA   -33.38mA
-900mV    -16.91mA   -55.06mA   -16.91mA
-800mV    -8.434mA   -13.38mA   -8.434mA
-700mV    -3.946mA   -3.946mA   -3.946mA
-600mV    -1.264mA   -1.264mA   -1.264mA
-500mV    -213uA     -246.3uA   -196.1uA
-400mV    -14.84uA   -26.5uA    -10.46uA
3.3V      3.366nA    3.366nA    16.84nA
[POWER_clamp]
-3.3V     1.025A     838.2mA    1.218A
-1.1V     112.5mA    112.5mA    112.5mA
-1V       80.27mA    80.27mA    80.27mA
-800mV    17.07mA    17.07mA    17.07mA
-700mV    4.946mA    4.946mA    5.793mA
-600mV    1.98mA     1.98mA     2.27mA
-500mV    443.7uA    443.7uA    443.7uA
-400mV    34.77uA    34.77uA    34.77uA
0V        3.366nA    3.366nA    56.62nA
[Ramp]
dV/dt_r   0.5135/0.2100n   0.3277/0.2878n   0.7026/0.1692n
dV/dt_f   0.5346/0.2879n   0.3144/0.3980n   0.7968/0.2335n
R_load = 50.0000
[Rising Waveform]
R_fixture = 50.0000
V_fixture = 0.000
V_fixture_min = 0.000
V_fixture_max = 0.000
0s        0V         0V         0V
900ps     202.2uV    -1.736uV   -12.85mV
1.05ns    363.5uV    -3.75uV    215.9mV
1.2ns     -7.418mV   -2.483uV   886.5mV
1.35ns    12.27mV    63.88uV    1.108V
1.5ns     388.1mV    321.3uV    1.157V
1.8ns     810.4mV    -2.864mV   1.17V
2.55ns    855.7mV    470.4mV    1.171V
3ns       855.8mV    541.4mV    1.171V
14.85ns   855.8mV    546.1mV    1.171V
[Rising Waveform]
R_fixture = 50.0000
V_fixture = 3.3000
V_fixture_min = 2.9700
V_fixture_max = 3.6300
0s        2.409V     2.446V     2.302V
900ps     2.408V     2.446V     2.404V
1.05ns    2.398V     2.446V     3.221V
1.2ns     2.454V     2.446V     3.591V
1.35ns    2.812V     2.446V     3.626V
1.5ns     3.206V     2.444V     3.629V
1.65ns    3.285V     2.437V     3.629V
2.25ns    3.3V       2.904V     3.63V
2.55ns    3.3V       2.964V     3.63V
14.85ns   3.3V       2.97V      3.63V
[Falling Waveform]
R_fixture = 50.0000
V_fixture = 0.000
V_fixture_min = 0.000
V_fixture_max = 0.000
0s        855.8mV    546.1mV    1.171V
600ps     858.4mV    545.9mV    1.162V
750ps     863.3mV    545.9mV    724.6mV
900ps     789.9mV    546.9mV    160.4mV
1.05ns    354.8mV    550.2mV    26.75mV
1.2ns     89.15mV    553.1mV    6.866mV
1.35ns    26.52mV    529.6mV    1.842mV
1.8ns     1.265mV    45.15mV    33.77uV
2.1ns     151uV      11.85mV    940.1nV
14.85ns   0V         0V         0V
[Falling Waveform]
R_fixture = 50.0000
V_fixture = 3.3000
V_fixture_min = 2.9700
V_fixture_max = 3.6300
0s        3.3V       2.97V      3.63V
900ps     3.31V      2.969V     3.643V
1.2ns     3.314V     2.97V      2.649V
1.35ns    3.103V     2.973V     2.414V
1.5ns     2.778V     2.983V     2.335V
1.65ns    2.564V     2.99V      2.311V
1.95ns    2.431V     2.948V     2.302V
2.55ns    2.409V     2.515V     2.302V
3ns       2.409V     2.454V     2.302V
14.85ns   2.409V     2.446V     2.302V
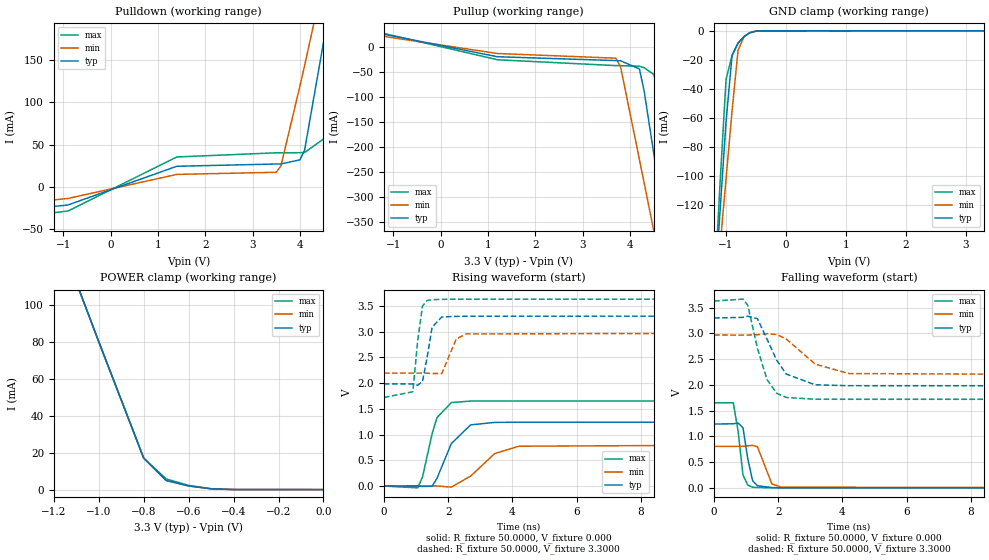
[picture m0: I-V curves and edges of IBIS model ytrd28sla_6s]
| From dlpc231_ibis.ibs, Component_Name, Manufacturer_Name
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| Model ytrd28sla_6s
[Model]   ytrd28sla_6s
Model_type   3-state
Polarity   Non-Inverting
Enable   Active-High
Vmeas = 1.5000V
Cref =50.0000pF
Rref = 0.5000k
Vref =  0.000V
C_comp   0.7000pF   0.7000pF   0.7000pF
[Temperature Range]   25.0000   0.1240k   -40.0000
[Voltage Range]   3.3000V   2.9700V   3.6300V
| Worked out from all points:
|   slope of the pulldown table from 0 to 0.495 V, typ, clamps not added: 41.7 ohm
|   slope of the pullup table from 0 to 0.495 V, typ, clamps not added: 51.3 ohm
|   GND clamp passes 1 mA (typ) near -0.57 V on its own axis
|   POWER clamp passes 1 mA (typ) near -0.54 V on its own axis
|   rising waveform, R_fixture 50.0000, V_fixture 0.000: 20-80 % time 542ps typ, 847ps min, 391ps max; typ from 0 V to 1.24 V
|   rising waveform, R_fixture 50.0000, V_fixture 3.3000: 20-80 % time 220ps typ, 263ps min, 204ps max; typ from 1.98 V to 3.3 V
|   falling waveform, R_fixture 50.0000, V_fixture 0.000: 20-80 % time 218ps typ, 263ps min, 197ps max; typ from 1.24 V to 0 V
|   falling waveform, R_fixture 50.0000, V_fixture 3.3000: 20-80 % time 649ps typ, 937ps min, 490ps max; typ from 3.3 V to 1.98 V
[Pulldown]
-3.3V     -36mA      -28mA      -45mA
-900mV    -21.82mA   -14.1mA    -29.04mA
1.4V      24.15mA    14.48mA    35.22mA
3.5V      26.85mA    17.01mA    40.14mA
3.6V      26.87mA    24.58mA    40.16mA
4V        31.8mA     119.2mA    40.29mA
4.1V      43.21mA    143.7mA    40.49mA
4.5V      171.5mA    246.1mA    56.57mA
4.7V      238.8mA    300.6mA    133.1mA
4.9V      308.6mA    358mA      217.1mA
5.1V      381.2mA    419.1mA    303.9mA
6.6V      1.058A     972.6mA    1.069A
[Pullup]
-3.3V     22mA       27.8mA     15mA
-1.5V     31.6mA     25.8mA     34mA
1.2V      -19.14mA   -12.66mA   -25.2mA
3.7V      -26.85mA   -22.07mA   -36.91mA
3.8V      -27.1mA    -38.84mA   -36.99mA
4.2V      -43.6mA    -224.9mA   -38.13mA
4.3V      -87.85mA   -271.8mA   -41.15mA
4.5V      -211mA     -366.2mA   -54.38mA
4.7V      -335.3mA   -461.2mA   -115.9mA
4.9V      -460.4mA   -556.8mA   -271.9mA
5.1V      -586.2mA   -652.9mA   -429mA
6.6V      -1.541A    -1.384A    -1.619A
[GND_clamp]
-3.3V     -1.515A    -1.204A    -1.847A
-1.2V     -185.5mA   -194.5mA   -182.5mA
-1.1V     -123.8mA   -147.9mA   -104.5mA
-1V       -62.37mA   -101.6mA   -33.38mA
-900mV    -16.91mA   -55.06mA   -16.91mA
-800mV    -8.434mA   -13.38mA   -8.434mA
-700mV    -3.946mA   -3.946mA   -3.946mA
-600mV    -1.264mA   -1.264mA   -1.264mA
-500mV    -213uA     -246.3uA   -196.1uA
-400mV    -14.84uA   -26.5uA    -10.46uA
3.3V      3.366nA    3.366nA    16.84nA
[POWER_clamp]
-3.3V     1.025A     838.2mA    1.218A
-1.1V     112.5mA    112.5mA    112.5mA
-1V       80.27mA    80.27mA    80.27mA
-800mV    17.07mA    17.07mA    17.07mA
-700mV    4.946mA    4.946mA    5.793mA
-600mV    1.98mA     1.98mA     2.27mA
-500mV    443.7uA    443.7uA    443.7uA
-400mV    34.77uA    34.77uA    34.77uA
0V        3.366nA    3.366nA    56.62nA
[Ramp]
dV/dt_r   0.7440/0.5395n   0.4834/0.8388n   0.9906/0.3882n
dV/dt_f   0.7896/0.6441n   0.4662/0.9352n   1.1454/0.4877n
R_load = 50.0000
[Rising Waveform]
R_fixture = 50.0000
V_fixture = 0.000
V_fixture_min = 0.000
V_fixture_max = 0.000
0s        0V         0V         0V
1.05ns    941.4uV    -7.781uV   -35.26mV
1.2ns     -8.92mV    -7.606uV   171.5mV
1.5ns     -4.324mV   629.5uV    1.016V
1.65ns    147.9mV    745.8uV    1.327V
2.1ns     826.1mV    -20.57mV   1.621V
2.7ns     1.188V     193.4mV    1.65V
3.45ns    1.236V     631.1mV    1.651V
4.2ns     1.24V      773.5mV    1.651V
14.85ns   1.24V      805.7mV    1.651V
[Rising Waveform]
R_fixture = 50.0000
V_fixture = 3.3000
V_fixture_min = 2.9700
V_fixture_max = 3.6300
0s        1.984V     2.193V     1.721V
900ps     1.982V     2.193V     1.832V
1.05ns    1.958V     2.193V     2.816V
1.2ns     2.028V     2.193V     3.496V
1.35ns    2.518V     2.192V     3.606V
1.5ns     3.086V     2.186V     3.619V
1.8ns     3.283V     2.185V     3.626V
2.25ns    3.295V     2.853V     3.629V
2.55ns    3.298V     2.954V     3.629V
14.85ns   3.3V       2.97V      3.63V
[Falling Waveform]
R_fixture = 50.0000
V_fixture = 0.000
V_fixture_min = 0.000
V_fixture_max = 0.000
0s        1.24V      805.7mV    1.651V
600ps     1.245V     805.4mV    1.653V
750ps     1.259V     805.2mV    1.095V
900ps     1.168V     807.3mV    250.6mV
1.05ns    565.8mV    815.4mV    53.4mV
1.2ns     139.8mV    826.4mV    12.31mV
1.35ns    40.88mV    799.6mV    6.901mV
1.8ns     5.51mV     76.08mV    2.229mV
2.1ns     3.322mV    13.86mV    801.8uV
14.85ns   0V         0V         0V
[Falling Waveform]
R_fixture = 50.0000
V_fixture = 3.3000
V_fixture_min = 2.9700
V_fixture_max = 3.6300
0s        3.3V       2.97V      3.63V
900ps     3.313V     2.969V     3.667V
1.05ns    3.336V     2.969V     3.547V
1.35ns    3.287V     2.974V     2.712V
1.65ns    2.888V     2.996V     2.103V
1.95ns    2.479V     2.979V     1.838V
2.25ns    2.211V     2.891V     1.756V
3.15ns    2.002V     2.404V     1.722V
4.2ns     1.985V     2.221V     1.721V
14.85ns   1.984V     2.193V     1.721V
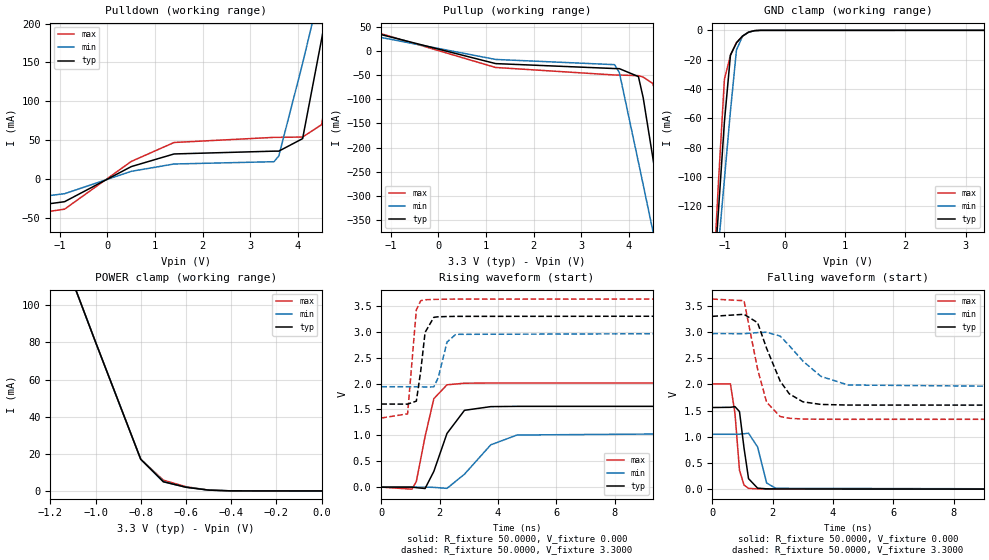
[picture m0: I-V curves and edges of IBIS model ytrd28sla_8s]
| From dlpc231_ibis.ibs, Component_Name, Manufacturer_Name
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| Model ytrd28sla_8s
[Model]   ytrd28sla_8s
Model_type   3-state
Polarity   Non-Inverting
Enable   Active-High
Vmeas = 1.5000V
Cref =50.0000pF
Rref = 0.5000k
Vref =  0.000V
C_comp   0.7000pF   0.7000pF   0.7000pF
[Temperature Range]   25.0000   0.1240k   -40.0000
[Voltage Range]   3.3000V   2.9700V   3.6300V
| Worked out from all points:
|   slope of the pulldown table from 0 to 0.495 V, typ, clamps not added: 31.2 ohm
|   slope of the pullup table from 0 to 0.495 V, typ, clamps not added: 38.5 ohm
|   GND clamp passes 1 mA (typ) near -0.57 V on its own axis
|   POWER clamp passes 1 mA (typ) near -0.54 V on its own axis
|   rising waveform, R_fixture 50.0000, V_fixture 0.000: 20-80 % time 629ps typ, 1.03ns min, 442ps max; typ from 0 V to 1.56 V
|   rising waveform, R_fixture 50.0000, V_fixture 3.3000: 20-80 % time 221ps typ, 270ps min, 207ps max; typ from 1.6 V to 3.3 V
|   falling waveform, R_fixture 50.0000, V_fixture 0.000: 20-80 % time 221ps typ, 270ps min, 188ps max; typ from 1.56 V to 0 V
|   falling waveform, R_fixture 50.0000, V_fixture 3.3000: 20-80 % time 738ps typ, 1.12ns min, 509ps max; typ from 3.3 V to 1.6 V
[Pulldown]
-3.3V     -49mA      -37mA      -60mA
-900mV    -29.14mA   -18.84mA   -38.76mA
500mV     16mA       9.925mA    22.62mA
1.4V      32.28mA    19.36mA    47.04mA
3.5V      35.89mA    22.32mA    53.63mA
3.6V      35.91mA    29.79mA    53.66mA
4.1V      52.01mA    148.9mA    54.04mA
4.5V      180.4mA    251.4mA    70.04mA
4.7V      247.7mA    305.9mA    146.3mA
4.9V      317.6mA    363.3mA    230.4mA
5.1V      390.3mA    424.5mA    317.2mA
6.6V      1.069A     979.2mA    1.085A
[Pullup]
-3.3V     29mA       37.1mA     20mA
-1.5V     42.2mA     34.4mA     45.3mA
1.2V      -25.52mA   -16.88mA   -33.59mA
3.7V      -35.8mA    -27.73mA   -49.22mA
3.8V      -36.06mA   -44.32mA   -49.33mA
4.2V      -52.5mA    -230.4mA   -50.54mA
4.3V      -96.34mA   -277.3mA   -53.55mA
4.5V      -219.5mA   -371.7mA   -66.77mA
4.7V      -343.8mA   -466.8mA   -127.4mA
4.9V      -468.9mA   -562.4mA   -283.5mA
5.1V      -594.8mA   -658.4mA   -440.6mA
6.6V      -1.55A     -1.389A    -1.631A
[GND_clamp]
-3.3V     -1.515A    -1.204A    -1.847A
-1.2V     -185.5mA   -194.5mA   -182.5mA
-1.1V     -123.8mA   -147.9mA   -104.5mA
-1V       -62.37mA   -101.6mA   -33.38mA
-900mV    -16.91mA   -55.06mA   -16.91mA
-800mV    -8.434mA   -13.38mA   -8.434mA
-700mV    -3.946mA   -3.946mA   -3.946mA
-600mV    -1.264mA   -1.264mA   -1.264mA
-500mV    -213uA     -246.3uA   -196.1uA
-400mV    -14.84uA   -26.5uA    -10.46uA
3.3V      3.366nA    3.366nA    16.84nA
[POWER_clamp]
-3.3V     1.025A     838.2mA    1.218A
-1.1V     112.5mA    112.5mA    112.5mA
-1V       80.27mA    80.27mA    80.27mA
-800mV    17.07mA    17.07mA    17.07mA
-700mV    4.946mA    4.946mA    5.793mA
-600mV    1.98mA     1.98mA     2.27mA
-500mV    443.7uA    443.7uA    443.7uA
-400mV    34.77uA    34.77uA    34.77uA
0V        3.366nA    3.366nA    56.62nA
[Ramp]
dV/dt_r   0.9354/0.6259n   0.6288/1.0226n   1.2060/0.4327n
dV/dt_f   1.0176/0.7333n   0.6192/1.1225n   1.3776/0.5031n
R_load = 50.0000
[Rising Waveform]
R_fixture = 50.0000
V_fixture = 0.000
V_fixture_min = 0.000
V_fixture_max = 0.000
0s        0V         0V         0V
1.05ns    778.2uV    -8.022uV   -39.12mV
1.2ns     -10.22mV   -7.649uV   109.3mV
1.5ns     -26.45mV   653.2uV    978.1mV
1.8ns     304.7mV    -4.257mV   1.707V
2.25ns    1.036V     -23.9mV    1.975V
2.85ns    1.483V     250.4mV    2.006V
3.75ns    1.554V     816.1mV    2.01V
4.65ns    1.559V     1.006V     2.01V
14.85ns   1.559V     1.048V     2.01V
[Rising Waveform]
R_fixture = 50.0000
V_fixture = 3.3000
V_fixture_min = 2.9700
V_fixture_max = 3.6300
0s        1.604V     1.938V     1.334V
900ps     1.602V     1.938V     1.414V
1.2ns     1.66V      1.938V     3.42V
1.35ns    2.24V      1.938V     3.598V
1.5ns     2.987V     1.931V     3.617V
1.8ns     3.278V     1.936V     3.623V
1.95ns    3.288V     2.112V     3.625V
2.25ns    3.293V     2.799V     3.628V
2.55ns    3.296V     2.949V     3.629V
14.85ns   3.3V       2.97V      3.63V
[Falling Waveform]
R_fixture = 50.0000
V_fixture = 0.000
V_fixture_min = 0.000
V_fixture_max = 0.000
0s        1.559V     1.048V     2.01V
600ps     1.563V     1.048V     2.01V
750ps     1.576V     1.048V     1.444V
900ps     1.481V     1.05V      359.7mV
1.05ns    786.1mV    1.058V     79.46mV
1.2ns     200.8mV    1.068V     15.04mV
1.5ns     19.87mV    805.7mV    5.768mV
1.8ns     6.53mV     118.3mV    3.492mV
2.1ns     4.386mV    16.3mV     1.582mV
14.85ns   0V         0V         0V
[Falling Waveform]
R_fixture = 50.0000
V_fixture = 3.3000
V_fixture_min = 2.9700
V_fixture_max = 3.6300
0s        3.3V       2.97V      3.63V
1.05ns    3.339V     2.969V     3.599V
1.5ns     3.179V     2.99V      2.292V
1.8ns     2.687V     2.996V     1.659V
2.25ns    2.061V     2.923V     1.387V
2.55ns    1.821V     2.741V     1.354V
3ns       1.668V     2.447V     1.339V
3.6ns     1.618V     2.154V     1.335V
4.5ns     1.606V     1.989V     1.334V
14.85ns   1.604V     1.938V     1.334V
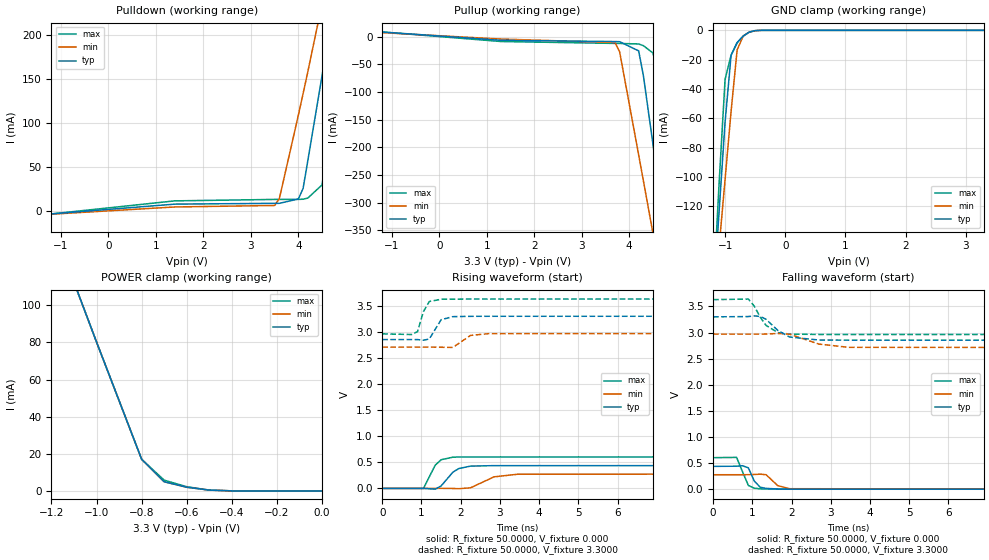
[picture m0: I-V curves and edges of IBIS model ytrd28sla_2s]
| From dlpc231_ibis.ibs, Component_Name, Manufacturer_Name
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| Model ytrd28sla_2s
[Model]   ytrd28sla_2s
Model_type   3-state
Polarity   Non-Inverting
Enable   Active-High
Vmeas = 1.5000V
Cref =50.0000pF
Rref = 0.5000k
Vref =  0.000V
C_comp   0.7000pF   0.7000pF   0.7000pF
[Temperature Range]   25.0000   0.1240k   -40.0000
[Voltage Range]   3.3000V   2.9700V   3.6300V
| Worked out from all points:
|   slope of the pulldown table from 0 to 0.495 V, typ, clamps not added: 125 ohm
|   slope of the pullup table from 0 to 0.495 V, typ, clamps not added: 154 ohm
|   GND clamp passes 1 mA (typ) near -0.57 V on its own axis
|   POWER clamp passes 1 mA (typ) near -0.54 V on its own axis
|   rising waveform, R_fixture 50.0000, V_fixture 0.000: 20-80 % time 341ps typ, 476ps min, 274ps max; typ from 0 V to 0.437 V
|   rising waveform, R_fixture 50.0000, V_fixture 3.3000: 20-80 % time 218ps typ, 256ps min, 198ps max; typ from 2.85 V to 3.3 V
|   falling waveform, R_fixture 50.0000, V_fixture 0.000: 20-80 % time 202ps typ, 235ps min, 203ps max; typ from 0.437 V to 0 V
|   falling waveform, R_fixture 50.0000, V_fixture 3.3000: 20-80 % time 449ps typ, 633ps min, 359ps max; typ from 3.3 V to 2.85 V
[Pulldown]
-3.3V     -12mA      -10mA      -15mA
1.4V      8.055mA    4.828mA    11.75mA
3.5V      8.95mA     6.53mA     13.38mA
3.6V      8.957mA    14.27mA    13.39mA
4V        13.9mA     108.9mA    13.43mA
4.1V      25.78mA    133.4mA    13.62mA
4.2V      57.42mA    158.3mA    14.96mA
4.5V      154mA      235.7mA    29.88mA
4.7V      221.2mA    290.1mA    107mA
4.9V      290.8mA    347.4mA    190.8mA
5.1V      363.2mA    408.4mA    277.3mA
6.6V      1.036A     959.4mA    1.038A
[Pullup]
-3.3V     7mA        9.3mA      5mA
-1.7V     11.3mA     9.5mA      11.8mA
1.3V      -6.71mA    -4.429mA   -8.856mA
3.7V      -8.961mA   -10.76mA   -12.3mA
3.8V      -9.174mA   -27.88mA   -12.33mA
4.2V      -25.8mA    -214mA     -13.32mA
4.3V      -70.86mA   -260.9mA   -16.36mA
4.5V      -194mA     -355.2mA   -29.61mA
4.7V      -318.2mA   -450.2mA   -92.76mA
4.9V      -443.3mA   -545.8mA   -248.8mA
5.1V      -569mA     -641.8mA   -405.8mA
6.6V      -1.524A    -1.372A    -1.596A
[GND_clamp]
-3.3V     -1.515A    -1.204A    -1.847A
-1.2V     -185.5mA   -194.5mA   -182.5mA
-1.1V     -123.8mA   -147.9mA   -104.5mA
-1V       -62.37mA   -101.6mA   -33.38mA
-900mV    -16.91mA   -55.06mA   -16.91mA
-800mV    -8.434mA   -13.38mA   -8.434mA
-700mV    -3.946mA   -3.946mA   -3.946mA
-600mV    -1.264mA   -1.264mA   -1.264mA
-500mV    -213uA     -246.3uA   -196.1uA
-400mV    -14.84uA   -26.5uA    -10.46uA
3.3V      3.366nA    3.366nA    16.84nA
[POWER_clamp]
-3.3V     1.025A     838.2mA    1.218A
-1.1V     112.5mA    112.5mA    112.5mA
-1V       80.27mA    80.27mA    80.27mA
-800mV    17.07mA    17.07mA    17.07mA
-700mV    4.946mA    4.946mA    5.793mA
-600mV    1.98mA     1.98mA     2.27mA
-500mV    443.7uA    443.7uA    443.7uA
-400mV    34.77uA    34.77uA    34.77uA
0V        3.366nA    3.366nA    56.62nA
[Ramp]
dV/dt_r   0.2620/0.3248n   0.1658/0.4758n   0.3620/0.2530n
dV/dt_f   0.2676/0.4394n   0.1566/0.6201n   0.4002/0.3499n
R_load = 50.0000
[Rising Waveform]
R_fixture = 50.0000
V_fixture = 0.000
V_fixture_min = 0.000
V_fixture_max = 0.000
0s        0V         0V         0V
1.05ns    860.2uV    -4.86uV    -1.572mV
1.35ns    -14.81mV   65.89uV    444.9mV
1.5ns     46.26mV    387.8uV    549.3mV
1.8ns     309.6mV    -1.464mV   598.1mV
1.95ns    380.3mV    -6.022mV   601.8mV
2.25ns    427.2mV    10.82mV    603.4mV
2.85ns    436.5mV    221.2mV    603.4mV
3.45ns    436.7mV    271.3mV    603.4mV
14.85ns   436.7mV    276.4mV    603.4mV
[Rising Waveform]
R_fixture = 50.0000
V_fixture = 3.3000
V_fixture_min = 2.9700
V_fixture_max = 3.6300
0s        2.854V     2.709V     2.963V
750ps     2.854V     2.709V     2.95V
900ps     2.853V     2.709V     3.006V
1.05ns    2.841V     2.709V     3.39V
1.2ns     2.865V     2.709V     3.583V
1.5ns     3.234V     2.706V     3.627V
1.8ns     3.293V     2.702V     3.629V
2.25ns    3.299V     2.933V     3.63V
2.7ns     3.3V       2.966V     3.63V
14.85ns   3.3V       2.97V      3.63V
[Falling Waveform]
R_fixture = 50.0000
V_fixture = 0.000
V_fixture_min = 0.000
V_fixture_max = 0.000
0s        436.7mV    276.4mV    603.4mV
600ps     439.7mV    276.2mV    608.4mV
750ps     449mV      276.1mV    334.1mV
900ps     408.4mV    277.2mV    71.54mV
1.05ns    156.6mV    281.4mV    18.65mV
1.2ns     38.07mV    287.2mV    6.447mV
1.35ns    14.34mV    277.3mV    3.535mV
1.65ns    4.023mV    67.34mV    773.9uV
1.95ns    1.361mV    8.525mV    141.3uV
14.85ns   0V         0V         0V
[Falling Waveform]
R_fixture = 50.0000
V_fixture = 3.3000
V_fixture_min = 2.9700
V_fixture_max = 3.6300
0s        3.3V       2.97V      3.63V
900ps     3.306V     2.969V     3.641V
1.05ns    3.319V     2.969V     3.506V
1.2ns     3.308V     2.969V     3.297V
1.35ns    3.254V     2.971V     3.137V
1.65ns    3.041V     2.982V     2.999V
1.95ns    2.914V     2.968V     2.97V
2.7ns     2.856V     2.778V     2.963V
3.45ns    2.854V     2.717V     2.963V
14.85ns   2.854V     2.709V     2.963V
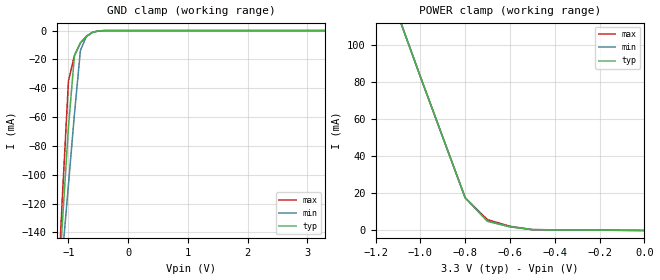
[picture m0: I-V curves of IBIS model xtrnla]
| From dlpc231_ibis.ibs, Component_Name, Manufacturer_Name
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| Model xtrnla
[Model]   xtrnla
Model_type   Input
Polarity   Non-Inverting
Enable   Active-High
Vinl = 0.8000V
Vinh = 2.0000V
C_comp   0.7000pF   0.7000pF   0.7000pF
[Temperature Range]   25.0000   0.1240k   -40.0000
[Voltage Range]   3.3000V   2.9700V   3.6300V
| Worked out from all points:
|   GND clamp passes 1 mA (typ) near -0.57 V on its own axis
|   POWER clamp passes 1 mA (typ) near -0.54 V on its own axis
[GND_clamp]
-3.3V     -1.621A    -1.269A    -2.01A
-1.2V     -198mA     -204.3mA   -198mA
-1.1V     -132.1mA   -155.3mA   -113.7mA
-1V       -66.63mA   -106.7mA   -34.83mA
-900mV    -17.32mA   -57.88mA   -17.32mA
-800mV    -8.573mA   -13.75mA   -8.573mA
-700mV    -4.014mA   -4.014mA   -4.014mA
-600mV    -1.291mA   -1.291mA   -1.291mA
-500mV    -219.8uA   -252.7uA   -203.7uA
-400mV    -15.61uA   -27.49uA   -11.15uA
3.3V      3.373nA    3.373nA    17.05nA
[POWER_clamp]
-3.3V     1.084A     871.5mA    1.299A
-1.1V     116.5mA    116.5mA    116.5mA
-1V       83.07mA    83.07mA    83.07mA
-800mV    17.65mA    17.65mA    17.65mA
-700mV    4.968mA    4.968mA    5.819mA
-600mV    1.985mA    1.985mA    2.276mA
-500mV    444.2uA    444.2uA    444.2uA
0V        3.373nA    3.373nA    57.43nA
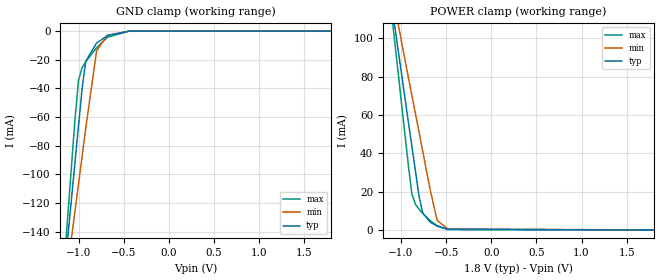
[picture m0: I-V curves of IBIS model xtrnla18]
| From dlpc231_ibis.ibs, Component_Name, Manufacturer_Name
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| Model xtrnla18
[Model] xtrnla18
Model_type Input
Polarity   Non-Inverting
Enable   Active-High
Vinl =  0.540V
Vinh =  1.260V
C_comp   1.622pF   1.492pF   1.779pF
C_comp_pullup   0.865pF   0.772pF   0.967pF
C_comp_pulldown   0.865pF   0.772pF   0.967pF
[Temperature Range]   25.000   0.125k   -40.000
[Voltage Range]   1.800V   1.620V   1.980V
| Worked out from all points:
|   GND clamp passes 1 mA (typ) near -0.58 V on its own axis
|   POWER clamp passes 1 mA (typ) near -0.54 V on its own axis
[GND_clamp]
-1.8V     -598.2mA   -501.7mA   -710.9mA
-1.16V    -171.2mA   -184.6mA   -163.8mA
-1.12V    -144.9mA   -165mA     -130mA
-1.08V    -118.6mA   -145.6mA   -96.24mA
-1.04V    -92.42mA   -126.2mA   -62.54mA
-1V       -66.27mA   -106.8mA   -34.35mA
-960mV    -40.09mA   -87.44mA   -25.54mA
-920mV    -21.19mA   -67.96mA   -21.42mA
-800mV    -8.345mA   -13.86mA   -11.62mA
-680mV    -3.193mA   -2.898mA   -4.322mA
-440mV    -45.57uA   -66.52uA   -36.67uA
1.8V      0A         0A         0A
[POWER_clamp]
-1.8V     368.8mA    314mA      433.7mA
-1.16V    136.8mA    139.5mA    137.3mA
-1.12V    123.2mA    129.4mA    119.8mA
-920mV    56.82mA    79.82mA    34.31mA
-880mV    43.86mA    70.32mA    18.87mA
-840mV    30.83mA    60.81mA    13.38mA
-800mV    17.65mA    51.08mA    10.77mA
-760mV    9.024mA    41.24mA    8.635mA
-680mV    4.213mA    21.65mA    4.997mA
-600mV    1.989mA    5.049mA    2.281mA
-480mV    292.3uA    521.4uA    246.2uA
1.8V      0A         0A         0A
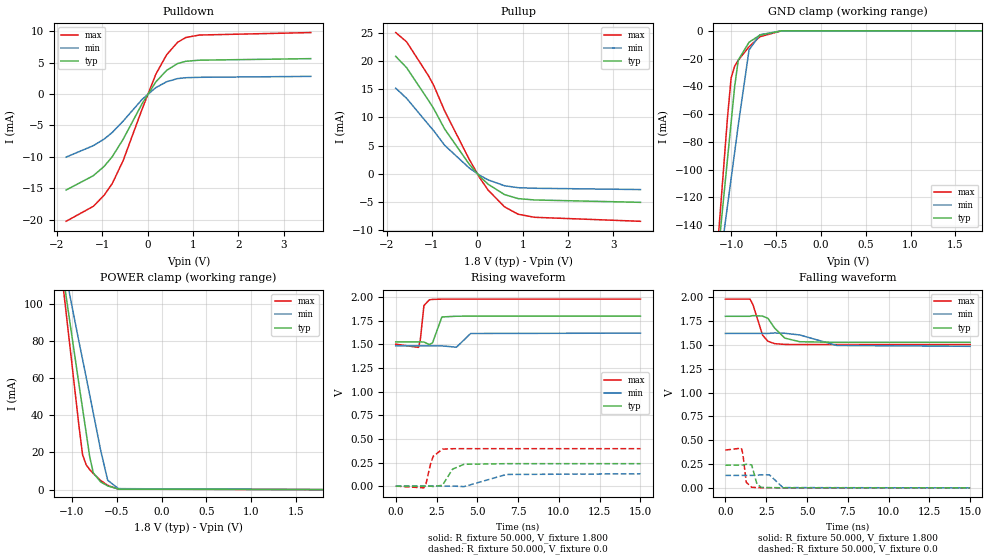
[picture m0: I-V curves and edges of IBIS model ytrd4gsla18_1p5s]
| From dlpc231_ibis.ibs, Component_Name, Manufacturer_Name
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| Model ytrd4gsla18_1p5s
[Model] ytrd4gsla18_1p5s
Model_type 3-state
Polarity   Non-Inverting
Enable   Active-High
Vmeas =  0.900V
Cref =  50.000pF
Rref =  0.500k
Vref =  0.0V
C_comp   1.682pF   1.563pF   1.805pF
C_comp_pullup   0.895pF   0.815pF   0.980pF
C_comp_pulldown   0.895pF   0.815pF   0.980pF
[Temperature Range]   25.000   0.125k   -40.000
[Voltage Range]   1.800V   1.620V   1.980V
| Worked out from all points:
|   slope of the pulldown table from 0 to 0.27 V, typ, clamps not added: 99.4 ohm
|   slope of the pullup table from 0 to 0.27 V, typ, clamps not added: 132 ohm
|   GND clamp passes 1 mA (typ) near -0.59 V on its own axis
|   POWER clamp passes 1 mA (typ) near -0.54 V on its own axis
|   rising waveform, R_fixture 50.000, V_fixture 1.800: 20-80 % time 210ps typ, 320ps min, 161ps max; typ from 1.53 V to 1.8 V
|   rising waveform, R_fixture 50.000, V_fixture 0.0: 20-80 % time 547ps typ, 949ps min, 367ps max; typ from 0 V to 0.238 V
|   falling waveform, R_fixture 50.000, V_fixture 1.800: 20-80 % time 772ps typ, 1.27ns min, 530ps max; typ from 1.8 V to 1.53 V
|   falling waveform, R_fixture 50.000, V_fixture 0.0: 20-80 % time 208ps typ, 316ps min, 155ps max; typ from 0.238 V to 0 V
[Pulldown]
-1.8V     -15.3mA    -10.05mA   -20.28mA
-1.2V     -13.02mA   -8.229mA   -17.9mA
-960mV    -11.53mA   -7.178mA   -16.13mA
-780mV    -9.975mA   -6.114mA   -14.25mA
-540mV    -7.195mA   -4.305mA   -10.6mA
-120mV    -1.499mA   -829uA     -2.359mA
180mV     1.936mA    1.026mA    3.159mA
420mV     3.782mA    1.968mA    6.273mA
660mV     4.863mA    2.466mA    8.245mA
840mV     5.225mA    2.604mA    9.012mA
1.14V     5.399mA    2.671mA    9.408mA
3.6V      5.646mA    2.818mA    9.802mA
[Pullup]
-1.8V     20.84mA    15.19mA    25.06mA
-1.56V    18.83mA    13.39mA    23.42mA
-1.08V    13.06mA    8.751mA    17.43mA
-960mV    11.53mA    7.619mA    15.65mA
-720mV    7.931mA    5.047mA    11.15mA
-180mV    1.72mA     1.042mA    2.588mA
60mV      -515.7uA   -302.6uA   -801.4uA
240mV     -1.861mA   -1.088mA   -2.907mA
600mV     -3.691mA   -2.122mA   -5.865mA
900mV     -4.402mA   -2.466mA   -7.176mA
1.26V     -4.645mA   -2.568mA   -7.72mA
3.6V      -5.067mA   -2.799mA   -8.432mA
[GND_clamp]
-1.8V     -597.4mA   -500.9mA   -710mA
-1.16V    -170.9mA   -184.3mA   -163.5mA
-1.12V    -144.6mA   -164.8mA   -129.7mA
-1.08V    -118.4mA   -145.4mA   -95.95mA
-1.04V    -92.22mA   -126mA     -62.27mA
-1V       -66.09mA   -106.6mA   -34.11mA
-960mV    -39.93mA   -87.3mA    -25.33mA
-920mV    -21.05mA   -67.84mA   -21.23mA
-800mV    -8.254mA   -13.78mA   -11.5mA
-680mV    -3.146mA   -2.862mA   -4.259mA
-440mV    -43.6uA    -64.31uA   -34.79uA
1.8V      0A         0A         0A
[POWER_clamp]
-1.8V     367.9mA    313.2mA    432.7mA
-1.16V    136.5mA    139.2mA    137mA
-1.12V    123mA      129mA      119.6mA
-920mV    56.74mA    79.65mA    34.28mA
-880mV    43.81mA    70.18mA    18.86mA
-840mV    30.81mA    60.69mA    13.38mA
-800mV    17.64mA    50.99mA    10.77mA
-760mV    9.019mA    41.18mA    8.633mA
-680mV    4.212mA    21.63mA    4.996mA
-600mV    1.988mA    5.044mA    2.281mA
-480mV    292.3uA    521.1uA    246.1uA
1.8V      0A         0A         0A
[Ramp]
dV/dt_r 0.143/0.553n   78.316m/0.948n   0.238/0.367n
dV/dt_f 0.164/0.779n   81.123m/1.276n   0.286/0.534n
R_load = 50.000
[Rising Waveform]
R_fixture= 50.000
V_fixture= 1.800
V_fixture_min= 1.620
V_fixture_max= 1.980
0s        1.527V     1.485V     1.503V
1.398ns   1.527V     1.485V     1.469V
1.508ns   1.527V     1.485V     1.551V
1.728ns   1.526V     1.485V     1.911V
2.059ns   1.498V     1.485V     1.973V
2.259ns   1.519V     1.485V     1.977V
2.829ns   1.791V     1.485V     1.98V
3.722ns   1.799V     1.471V     1.98V
4.591ns   1.8V       1.616V     1.98V
15ns      1.8V       1.62V      1.98V
[Rising Waveform]
R_fixture= 50.000
V_fixture= 0.0
V_fixture_min= 0.0
V_fixture_max= 0.0
0s        0V         0V         0V
1.727ns   230.6uV    0V         -18.43mV
1.857ns   627.1uV    -988.5nV   25.97mV
2.128ns   -169.9uV   -4.104uV   230.9mV
2.298ns   -3.987mV   -5.526uV   316.5mV
2.859ns   8.468mV    86.9uV     391.1mV
3.489ns   180.3mV    348.6uV    396.1mV
4.188ns   231.4mV    -5.018mV   396.4mV
6.778ns   237.6mV    123.3mV    396.4mV
15ns      237.6mV    130.5mV    396.4mV
[Falling Waveform]
R_fixture= 50.000
V_fixture= 1.800
V_fixture_min= 1.620
V_fixture_max= 1.980
0s        1.8V       1.62V      1.98V
1.509ns   1.8V       1.62V      1.98V
1.69ns    1.807V     1.62V      1.922V
2.278ns   1.802V     1.62V      1.602V
2.61ns    1.778V     1.62V      1.538V
3.009ns   1.678V     1.625V     1.513V
3.639ns   1.571V     1.622V     1.505V
4.559ns   1.533V     1.604V     1.503V
6.819ns   1.527V     1.494V     1.503V
15ns      1.527V     1.485V     1.503V
[Falling Waveform]
R_fixture= 50.000
V_fixture= 0.0
V_fixture_min= 0.0
V_fixture_max= 0.0
0s        237.6mV    130.5mV    396.4mV
980ps     238.7mV    130.3mV    416.8mV
1.069ns   240.1mV    130.3mV    357.3mV
1.279ns   247.6mV    130.4mV    58.26mV
1.609ns   241.3mV    130.9mV    6.139mV
1.939ns   36.74mV    132.8mV    3.364mV
2.217ns   4.457mV    137.2mV    1.543mV
2.707ns   3.084mV    135.3mV    338.3uV
3.528ns   824.6uV    2.67mV     24.44uV
15ns      0V         0V         0V
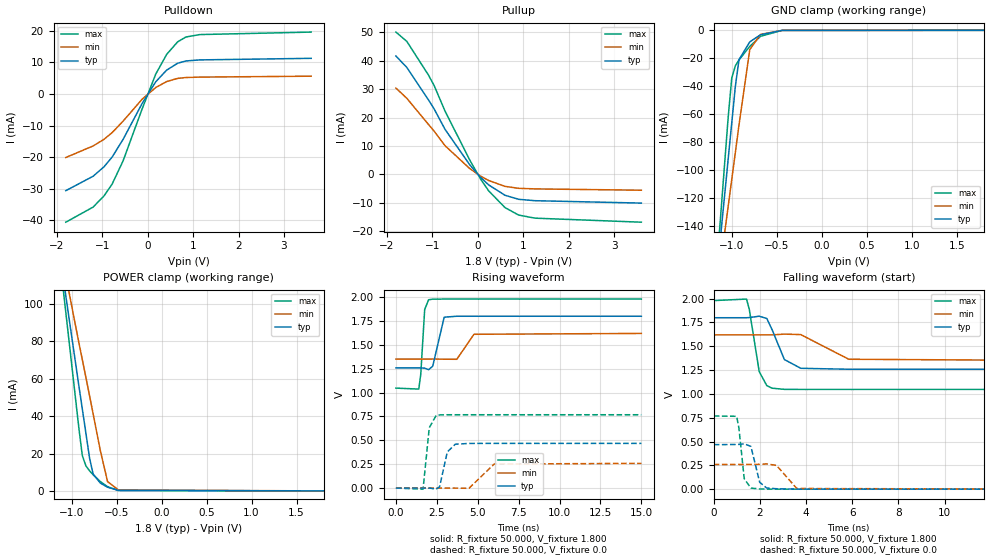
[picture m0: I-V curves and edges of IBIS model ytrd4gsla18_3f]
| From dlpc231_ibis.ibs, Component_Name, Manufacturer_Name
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| Model ytrd4gsla18_3f
[Model] ytrd4gsla18_3f
Model_type 3-state
Polarity   Non-Inverting
Enable   Active-High
Vmeas =  0.900V
Cref =  50.000pF
Rref =  0.500k
Vref =  0.0V
C_comp   1.770pF   1.665pF   1.865pF
C_comp_pullup   0.923pF   0.844pF   1.003pF
C_comp_pulldown   0.923pF   0.844pF   1.003pF
[Temperature Range]   25.000   0.125k   -40.000
[Voltage Range]   1.800V   1.620V   1.980V
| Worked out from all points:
|   slope of the pulldown table from 0 to 0.27 V, typ, clamps not added: 49.8 ohm
|   slope of the pullup table from 0 to 0.27 V, typ, clamps not added: 65.7 ohm
|   GND clamp passes 1 mA (typ) near -0.59 V on its own axis
|   POWER clamp passes 1 mA (typ) near -0.54 V on its own axis
|   rising waveform, R_fixture 50.000, V_fixture 1.800: 20-80 % time 260ps typ, 401ps min, 184ps max; typ from 1.26 V to 1.8 V
|   rising waveform, R_fixture 50.000, V_fixture 0.0: 20-80 % time 357ps typ, 612ps min, 239ps max; typ from 0 V to 0.468 V
|   falling waveform, R_fixture 50.000, V_fixture 1.800: 20-80 % time 536ps typ, 856ps min, 370ps max; typ from 1.8 V to 1.26 V
|   falling waveform, R_fixture 50.000, V_fixture 0.0: 20-80 % time 254ps typ, 388ps min, 187ps max; typ from 0.468 V to 0 V
[Pulldown]
-1.8V     -30.6mA    -20.11mA   -40.57mA
-1.2V     -26.04mA   -16.46mA   -35.8mA
-960mV    -23.06mA   -14.36mA   -32.27mA
-780mV    -19.95mA   -12.23mA   -28.5mA
-540mV    -14.38mA   -8.604mA   -21.18mA
-120mV    -2.994mA   -1.656mA   -4.715mA
180mV     3.867mA    2.049mA    6.312mA
420mV     7.552mA    3.928mA    12.53mA
660mV     9.708mA    4.92mA     16.47mA
840mV     10.43mA    5.193mA    18mA
1.14V     10.77mA    5.327mA    18.78mA
3.6V      11.27mA    5.62mA     19.57mA
[Pullup]
-1.8V     41.69mA    30.4mA     50.13mA
-1.56V    37.67mA    26.79mA    46.85mA
-1.08V    26.14mA    17.51mA    34.87mA
-960mV    23.07mA    15.24mA    31.3mA
-720mV    15.87mA    10.1mA     22.31mA
-180mV    3.442mA    2.085mA    5.177mA
60mV      -1.032mA   -605.4uA   -1.603mA
240mV     -3.724mA   -2.176mA   -5.815mA
600mV     -7.384mA   -4.245mA   -11.73mA
900mV     -8.807mA   -4.934mA   -14.36mA
1.26V     -9.294mA   -5.138mA   -15.45mA
3.6V      -10.14mA   -5.6mA     -16.87mA
[GND_clamp]
-1.8V     -597.4mA   -500.9mA   -710mA
-1.16V    -170.9mA   -184.3mA   -163.5mA
-1.12V    -144.6mA   -164.8mA   -129.7mA
-1.08V    -118.4mA   -145.4mA   -95.95mA
-1.04V    -92.22mA   -126mA     -62.27mA
-1V       -66.09mA   -106.6mA   -34.11mA
-960mV    -39.93mA   -87.3mA    -25.33mA
-920mV    -21.05mA   -67.84mA   -21.23mA
-800mV    -8.254mA   -13.78mA   -11.5mA
-680mV    -3.146mA   -2.862mA   -4.259mA
-440mV    -43.6uA    -64.31uA   -34.79uA
1.8V      0A         0A         0A
[POWER_clamp]
-1.8V     367.9mA    313.2mA    432.7mA
-1.16V    136.5mA    139.2mA    137mA
-1.12V    123mA      129mA      119.6mA
-920mV    56.74mA    79.65mA    34.28mA
-880mV    43.81mA    70.18mA    18.86mA
-840mV    30.81mA    60.69mA    13.38mA
-800mV    17.64mA    50.99mA    10.77mA
-760mV    9.019mA    41.18mA    8.633mA
-680mV    4.212mA    21.63mA    4.996mA
-600mV    1.988mA    5.044mA    2.281mA
-480mV    292.3uA    521.1uA    246.1uA
1.8V      0A         0A         0A
[Ramp]
dV/dt_r 0.281/0.357n   0.155/0.610n   0.461/0.241n
dV/dt_f 0.325/0.537n   0.161/0.870n   0.560/0.369n
R_load = 50.000
[Rising Waveform]
R_fixture= 50.000
V_fixture= 1.800
V_fixture_min= 1.620
V_fixture_max= 1.980
0s        1.259V     1.351V     1.047V
1.398ns   1.259V     1.351V     1.037V
1.518ns   1.259V     1.351V     1.193V
1.758ns   1.256V     1.351V     1.871V
1.998ns   1.24V      1.351V     1.973V
2.249ns   1.277V     1.352V     1.979V
2.949ns   1.79V      1.35V      1.98V
3.721ns   1.8V       1.349V     1.98V
4.771ns   1.8V       1.611V     1.98V
15ns      1.8V       1.62V      1.98V
[Rising Waveform]
R_fixture= 50.000
V_fixture= 0.0
V_fixture_min= 0.0
V_fixture_max= 0.0
0s        0V         0V         0V
1.658ns   70.98uV    0V         -11.44mV
2.038ns   280.6uV    -2.456uV   632.2mV
2.459ns   -11.54mV   -2.175uV   761mV
2.669ns   13mV       3.429uV    766.3mV
3.139ns   378.2mV    279.6uV    768mV
3.628ns   459.2mV    -624.4uV   768.1mV
4.462ns   467.5mV    -2.56mV    768.1mV
6.008ns   467.7mV    251.7mV    768.1mV
15ns      467.7mV    258.9mV    768.1mV
[Falling Waveform]
R_fixture= 50.000
V_fixture= 1.800
V_fixture_min= 1.620
V_fixture_max= 1.980
0s        1.8V       1.62V      1.98V
1.419ns   1.8V       1.62V      1.996V
1.539ns   1.802V     1.62V      1.888V
1.969ns   1.816V     1.62V      1.234V
2.298ns   1.792V     1.62V      1.087V
2.529ns   1.673V     1.62V      1.06V
3.059ns   1.361V     1.628V     1.048V
3.769ns   1.269V     1.623V     1.047V
5.849ns   1.259V     1.364V     1.047V
15ns      1.259V     1.351V     1.047V
[Falling Waveform]
R_fixture= 50.000
V_fixture= 0.0
V_fixture_min= 0.0
V_fixture_max= 0.0
0s        467.7mV    258.9mV    768.1mV
990ps     468.7mV    258.8mV    765mV
1.089ns   470mV      258.8mV    641.9mV
1.319ns   476.5mV    258.9mV    109.4mV
1.609ns   449.1mV    259.3mV    11.19mV
1.989ns   72.02mV    261.2mV    2.16mV
2.289ns   12.26mV    265.1mV    515.3uV
2.719ns   4.581mV    249.4mV    63.22uV
3.597ns   294.9uV    6.98mV     864.7nV
15ns      0V         0V         0V
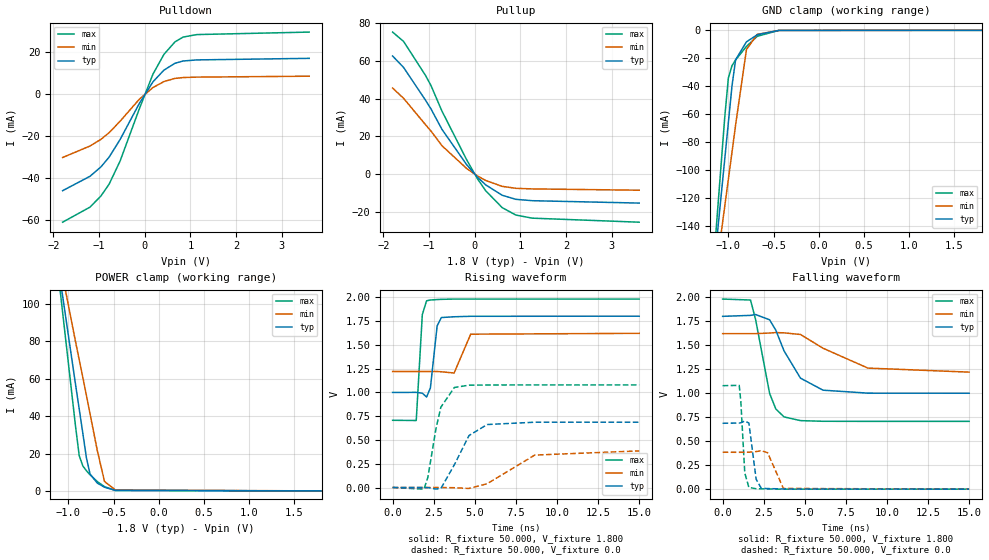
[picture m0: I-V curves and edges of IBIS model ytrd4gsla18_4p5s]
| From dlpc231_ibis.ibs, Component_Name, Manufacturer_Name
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| Model ytrd4gsla18_4p5s
[Model] ytrd4gsla18_4p5s
Model_type 3-state
Polarity   Non-Inverting
Enable   Active-High
Vmeas =  0.900V
Cref =  50.000pF
Rref =  0.500k
Vref =  0.0V
C_comp   2.313pF   2.236pF   2.315pF
C_comp_pullup   1.168pF   1.119pF   1.183pF
C_comp_pulldown   1.168pF   1.119pF   1.183pF
[Temperature Range]   25.000   0.125k   -40.000
[Voltage Range]   1.800V   1.620V   1.980V
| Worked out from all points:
|   slope of the pulldown table from 0 to 0.27 V, typ, clamps not added: 33.2 ohm
|   slope of the pullup table from 0 to 0.27 V, typ, clamps not added: 43.8 ohm
|   GND clamp passes 1 mA (typ) near -0.59 V on its own axis
|   POWER clamp passes 1 mA (typ) near -0.54 V on its own axis
|   rising waveform, R_fixture 50.000, V_fixture 1.800: 20-80 % time 276ps typ, 417ps min, 200ps max; typ from 0.999 V to 1.8 V
|   rising waveform, R_fixture 50.000, V_fixture 0.0: 20-80 % time 1.13ns typ, 1.97ns min, 706ps max; typ from 0 V to 0.686 V
|   falling waveform, R_fixture 50.000, V_fixture 1.800: 20-80 % time 1.45ns typ, 2.34ns min, 869ps max; typ from 1.8 V to 0.999 V
|   falling waveform, R_fixture 50.000, V_fixture 0.0: 20-80 % time 274ps typ, 415ps min, 200ps max; typ from 0.686 V to 0 V
[Pulldown]
-1.8V     -45.9mA    -30.16mA   -60.85mA
-1.2V     -39.06mA   -24.69mA   -53.7mA
-960mV    -34.59mA   -21.53mA   -48.4mA
-780mV    -29.93mA   -18.34mA   -42.75mA
-540mV    -21.58mA   -12.91mA   -31.78mA
-120mV    -4.493mA   -2.485mA   -7.075mA
180mV     5.802mA    3.075mA    9.47mA
420mV     11.33mA    5.896mA    18.81mA
660mV     14.57mA    7.386mA    24.71mA
840mV     15.65mA    7.797mA    27.01mA
1.14V     16.17mA    7.999mA    28.19mA
3.6V      16.91mA    8.437mA    29.37mA
[Pullup]
-1.8V     62.53mA    45.59mA    75.18mA
-1.56V    56.51mA    40.18mA    70.26mA
-1.08V    39.2mA     26.26mA    52.3mA
-960mV    34.6mA     22.86mA    46.95mA
-720mV    23.8mA     15.14mA    33.46mA
-180mV    5.162mA    3.128mA    7.765mA
60mV      -1.548mA   -908uA     -2.405mA
240mV     -5.585mA   -3.264mA   -8.722mA
600mV     -11.07mA   -6.366mA   -17.6mA
900mV     -13.21mA   -7.4mA     -21.53mA
1.26V     -13.94mA   -7.707mA   -23.17mA
3.6V      -15.2mA    -8.399mA   -25.3mA
[GND_clamp]
-1.8V     -597.4mA   -500.9mA   -710mA
-1.16V    -170.9mA   -184.3mA   -163.5mA
-1.12V    -144.6mA   -164.8mA   -129.7mA
-1.08V    -118.4mA   -145.4mA   -95.95mA
-1.04V    -92.22mA   -126mA     -62.27mA
-1V       -66.09mA   -106.6mA   -34.11mA
-960mV    -39.93mA   -87.3mA    -25.33mA
-920mV    -21.05mA   -67.84mA   -21.23mA
-800mV    -8.254mA   -13.78mA   -11.5mA
-680mV    -3.146mA   -2.862mA   -4.259mA
-440mV    -43.6uA    -64.31uA   -34.79uA
1.8V      0A         0A         0A
[POWER_clamp]
-1.8V     367.9mA    313.2mA    432.7mA
-1.16V    136.5mA    139.2mA    137mA
-1.12V    123mA      129mA      119.6mA
-920mV    56.74mA    79.65mA    34.28mA
-880mV    43.81mA    70.18mA    18.86mA
-840mV    30.81mA    60.69mA    13.38mA
-800mV    17.64mA    50.99mA    10.77mA
-760mV    9.019mA    41.18mA    8.633mA
-680mV    4.212mA    21.63mA    4.996mA
-600mV    1.988mA    5.044mA    2.281mA
-480mV    292.3uA    521.1uA    246.1uA
1.8V      0A         0A         0A
[Ramp]
dV/dt_r 0.412/1.139n   0.231/1.982n   0.647/0.709n
dV/dt_f 0.481/1.459n   0.241/2.365n   0.764/0.882n
R_load = 50.000
[Rising Waveform]
R_fixture= 50.000
V_fixture= 1.800
V_fixture_min= 1.620
V_fixture_max= 1.980
0s        999.1mV    1.219V     706.3mV
1.438ns   999.6mV    1.219V     704mV
1.808ns   991mV      1.219V     1.818V
2.068ns   951.1mV    1.219V     1.962V
2.299ns   1.046V     1.219V     1.97V
2.709ns   1.699V     1.219V     1.975V
2.969ns   1.786V     1.216V     1.977V
3.742ns   1.794V     1.203V     1.98V
4.751ns   1.799V     1.611V     1.98V
15ns      1.8V       1.62V      1.98V
[Rising Waveform]
R_fixture= 50.000
V_fixture= 0.0
V_fixture_min= 0.0
V_fixture_max= 0.0
0s        0V         0V         0V
1.908ns   793.1uV    -1.833uV   -17.43mV
2.149ns   -1.084mV   -5.717uV   109.3mV
2.638ns   -16.57mV   -2.869uV   618.6mV
2.937ns   -10.03mV   220.4uV    844.5mV
3.758ns   239.6mV    -2.278mV   1.051V
4.649ns   546.1mV    -10.07mV   1.075V
5.751ns   661.8mV    39.72mV    1.077V
8.648ns   686.1mV    340.8mV    1.078V
15ns      686.3mV    384.5mV    1.078V
[Falling Waveform]
R_fixture= 50.000
V_fixture= 1.800
V_fixture_min= 1.620
V_fixture_max= 1.980
0s        1.8V       1.62V      1.98V
1.699ns   1.81V      1.62V      1.97V
2.009ns   1.819V     1.62V      1.765V
2.86ns    1.764V     1.626V     996.9mV
3.239ns   1.655V     1.631V     834.8mV
3.739ns   1.44V      1.628V     752.5mV
4.739ns   1.156V     1.611V     713.9mV
6.109ns   1.031V     1.468V     707mV
8.839ns   1V         1.261V     706.3mV
15ns      999.1mV    1.219V     706.3mV
[Falling Waveform]
R_fixture= 50.000
V_fixture= 0.0
V_fixture_min= 0.0
V_fixture_max= 0.0
0s        686.3mV    384.6mV    1.078V
1.01ns    688.6mV    384.1mV    1.081V
1.109ns   691.8mV    384.1mV    913.1mV
1.349ns   709.9mV    384.3mV    168.6mV
1.599ns   688.9mV    385.1mV    17.89mV
2.039ns   104mV      390.9mV    4.625mV
2.349ns   10.19mV    402.1mV    3.506mV
2.739ns   6.105mV    379.1mV    1.917mV
3.697ns   2.53mV     7.643mV    392.2uV
15ns      0V         3.636uV    0V
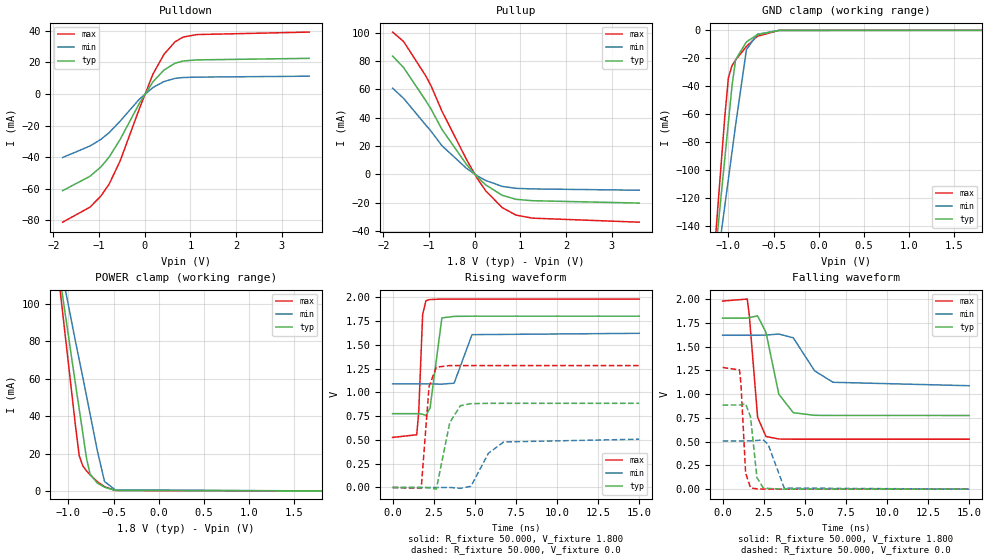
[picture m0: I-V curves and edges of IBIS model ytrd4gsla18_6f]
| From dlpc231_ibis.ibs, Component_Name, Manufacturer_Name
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| Model ytrd4gsla18_6f
[Model] ytrd4gsla18_6f
Model_type 3-state
Polarity   Non-Inverting
Enable   Active-High
Vmeas =  0.900V
Cref =  50.000pF
Rref =  0.500k
Vref =  0.0V
C_comp   2.166pF   2.148pF   2.193pF
C_comp_pullup   1.097pF   1.031pF   1.134pF
C_comp_pulldown   1.097pF   1.031pF   1.134pF
[Temperature Range]   25.000   0.125k   -40.000
[Voltage Range]   1.800V   1.620V   1.980V
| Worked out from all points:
|   slope of the pulldown table from 0 to 0.27 V, typ, clamps not added: 24.9 ohm
|   slope of the pullup table from 0 to 0.27 V, typ, clamps not added: 32.9 ohm
|   GND clamp passes 1 mA (typ) near -0.59 V on its own axis
|   POWER clamp passes 1 mA (typ) near -0.54 V on its own axis
|   rising waveform, R_fixture 50.000, V_fixture 1.800: 20-80 % time 296ps typ, 460ps min, 193ps max; typ from 0.776 V to 1.8 V
|   rising waveform, R_fixture 50.000, V_fixture 0.0: 20-80 % time 562ps typ, 1ns min, 308ps max; typ from 0 V to 0.884 V
|   falling waveform, R_fixture 50.000, V_fixture 1.800: 20-80 % time 761ps typ, 1.28ns min, 396ps max; typ from 1.8 V to 0.776 V
|   falling waveform, R_fixture 50.000, V_fixture 0.0: 20-80 % time 305ps typ, 464ps min, 215ps max; typ from 0.884 V to 0 V
[Pulldown]
-1.8V     -61.2mA    -40.22mA   -81.13mA
-1.2V     -52.08mA   -32.92mA   -71.61mA
-960mV    -46.13mA   -28.71mA   -64.54mA
-780mV    -39.9mA    -24.46mA   -57mA
-540mV    -28.77mA   -17.21mA   -42.37mA
-120mV    -5.989mA   -3.312mA   -9.431mA
180mV     7.733mA    4.097mA    12.62mA
420mV     15.1mA     7.857mA    25.06mA
660mV     19.42mA    9.839mA    32.94mA
840mV     20.86mA    10.39mA    35.99mA
1.14V     21.55mA    10.65mA    37.57mA
3.6V      22.53mA    11.24mA    39.14mA
[Pullup]
-1.8V     83.38mA    60.79mA    100.3mA
-1.56V    75.35mA    53.58mA    93.69mA
-1.08V    52.28mA    35.02mA    69.74mA
-960mV    46.13mA    30.49mA    62.61mA
-720mV    31.73mA    20.2mA     44.61mA
-180mV    6.883mA    4.171mA    10.35mA
60mV      -2.064mA   -1.211mA   -3.207mA
240mV     -7.448mA   -4.352mA   -11.63mA
600mV     -14.77mA   -8.49mA    -23.47mA
900mV     -17.61mA   -9.868mA   -28.71mA
1.26V     -18.59mA   -10.28mA   -30.89mA
3.6V      -20.27mA   -11.2mA    -33.74mA
[GND_clamp]
-1.8V     -597.4mA   -500.9mA   -710mA
-1.16V    -170.9mA   -184.3mA   -163.5mA
-1.12V    -144.6mA   -164.8mA   -129.7mA
-1.08V    -118.4mA   -145.4mA   -95.95mA
-1.04V    -92.22mA   -126mA     -62.27mA
-1V       -66.09mA   -106.6mA   -34.11mA
-960mV    -39.93mA   -87.3mA    -25.33mA
-920mV    -21.05mA   -67.84mA   -21.23mA
-800mV    -8.254mA   -13.78mA   -11.5mA
-680mV    -3.146mA   -2.862mA   -4.259mA
-440mV    -43.6uA    -64.31uA   -34.79uA
1.8V      0A         0A         0A
[POWER_clamp]
-1.8V     367.9mA    313.2mA    432.7mA
-1.16V    136.5mA    139.2mA    137mA
-1.12V    123mA      129mA      119.6mA
-920mV    56.74mA    79.65mA    34.28mA
-880mV    43.81mA    70.18mA    18.86mA
-840mV    30.81mA    60.69mA    13.38mA
-800mV    17.64mA    50.99mA    10.77mA
-760mV    9.019mA    41.18mA    8.633mA
-680mV    4.212mA    21.63mA    4.996mA
-600mV    1.988mA    5.044mA    2.281mA
-480mV    292.3uA    521.1uA    246.1uA
1.8V      0A         0A         0A
[Ramp]
dV/dt_r 0.531/0.565n   0.304/1.003n   0.769/0.306n
dV/dt_f 0.615/0.770n   0.319/1.289n   0.872/0.399n
R_load = 50.000
[Rising Waveform]
R_fixture= 50.000
V_fixture= 1.800
V_fixture_min= 1.620
V_fixture_max= 1.980
0s        775.5mV    1.089V     525.9mV
1.467ns   775.8mV    1.089V     554mV
1.588ns   775.9mV    1.089V     789.4mV
1.827ns   769.8mV    1.089V     1.818V
2.028ns   755.8mV    1.089V     1.963V
2.279ns   836.8mV    1.089V     1.975V
2.998ns   1.782V     1.086V     1.98V
3.741ns   1.798V     1.096V     1.98V
4.832ns   1.8V       1.606V     1.98V
15ns      1.8V       1.62V      1.98V
[Rising Waveform]
R_fixture= 50.000
V_fixture= 0.0
V_fixture_min= 0.0
V_fixture_max= 0.0
0s        0V         0V         0V
1.738ns   211.7uV    0V         -8.872mV
2.218ns   -3.508mV   -4.182uV   1.061V
2.659ns   -17.74mV   2.546uV    1.264V
3.479ns   683mV      75.79uV    1.281V
4.128ns   859.6mV    -8.844mV   1.281V
4.762ns   881mV      12.11mV    1.281V
5.829ns   884.3mV    359.4mV    1.281V
6.757ns   884.4mV    478.5mV    1.281V
15ns      884.4mV    507.2mV    1.281V
[Falling Waveform]
R_fixture= 50.000
V_fixture= 1.800
V_fixture_min= 1.620
V_fixture_max= 1.980
0s        1.8V       1.62V      1.98V
1.5ns     1.801V     1.62V      2.001V
1.619ns   1.806V     1.62V      1.839V
2.13ns    1.824V     1.62V      755.8mV
2.639ns   1.65V      1.622V     554.4mV
3.419ns   1V         1.633V     528.2mV
4.299ns   805.1mV    1.593V     526mV
5.599ns   777.2mV    1.245V     525.9mV
6.719ns   775.7mV    1.125V     525.9mV
15ns      775.5mV    1.089V     525.9mV
[Falling Waveform]
R_fixture= 50.000
V_fixture= 0.0
V_fixture_min= 0.0
V_fixture_max= 0.0
0s        884.4mV    507.2mV    1.281V
1.03ns    886.2mV    506.9mV    1.255V
1.119ns   887.9mV    506.9mV    1.104V
1.399ns   898.5mV    507.2mV    171.5mV
1.698ns   761.6mV    508.1mV    13.13mV
2.088ns   121.7mV    512.3mV    3.581mV
2.458ns   16.51mV    519.4mV    1.124mV
2.767ns   7.405mV    473.4mV    412uV
3.748ns   954.6uV    12.14mV    15.86uV
15ns      0V         0V         0V
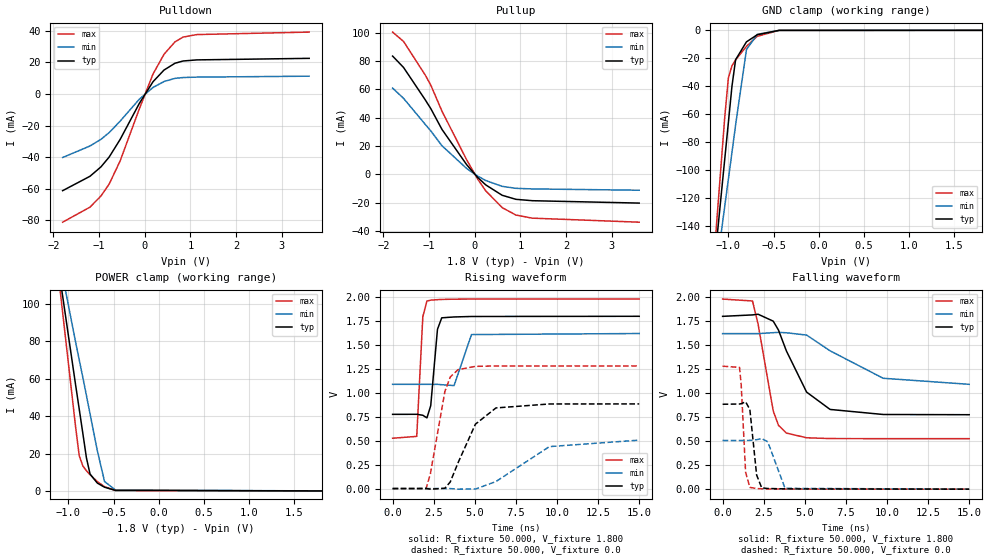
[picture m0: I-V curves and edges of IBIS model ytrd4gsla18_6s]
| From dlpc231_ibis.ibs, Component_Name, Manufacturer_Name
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| Model ytrd4gsla18_6s
[Model] ytrd4gsla18_6s
Model_type 3-state
Polarity   Non-Inverting
Enable   Active-High
Vmeas =  0.900V
Cref =  50.000pF
Rref =  0.500k
Vref =  0.0V
C_comp   2.850pF   2.597pF   2.930pF
C_comp_pullup   1.373pF   1.360pF   1.405pF
C_comp_pulldown   1.373pF   1.360pF   1.405pF
[Temperature Range]   25.000   0.125k   -40.000
[Voltage Range]   1.800V   1.620V   1.980V
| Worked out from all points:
|   slope of the pulldown table from 0 to 0.27 V, typ, clamps not added: 24.9 ohm
|   slope of the pullup table from 0 to 0.27 V, typ, clamps not added: 32.9 ohm
|   GND clamp passes 1 mA (typ) near -0.59 V on its own axis
|   POWER clamp passes 1 mA (typ) near -0.54 V on its own axis
|   rising waveform, R_fixture 50.000, V_fixture 1.800: 20-80 % time 292ps typ, 449ps min, 199ps max; typ from 0.776 V to 1.8 V
|   rising waveform, R_fixture 50.000, V_fixture 0.0: 20-80 % time 1.41ns typ, 2.49ns min, 792ps max; typ from 0 V to 0.884 V
|   falling waveform, R_fixture 50.000, V_fixture 1.800: 20-80 % time 1.7ns typ, 2.87ns min, 884ps max; typ from 1.8 V to 0.776 V
|   falling waveform, R_fixture 50.000, V_fixture 0.0: 20-80 % time 301ps typ, 457ps min, 213ps max; typ from 0.884 V to 0 V
[Pulldown]
-1.8V     -61.2mA    -40.22mA   -81.13mA
-1.2V     -52.08mA   -32.92mA   -71.61mA
-960mV    -46.13mA   -28.71mA   -64.54mA
-780mV    -39.9mA    -24.46mA   -57mA
-540mV    -28.77mA   -17.21mA   -42.37mA
-120mV    -5.989mA   -3.312mA   -9.431mA
180mV     7.733mA    4.097mA    12.62mA
420mV     15.1mA     7.857mA    25.06mA
660mV     19.42mA    9.839mA    32.94mA
840mV     20.86mA    10.39mA    35.99mA
1.14V     21.55mA    10.65mA    37.57mA
3.6V      22.53mA    11.24mA    39.14mA
[Pullup]
-1.8V     83.38mA    60.79mA    100.3mA
-1.56V    75.35mA    53.58mA    93.69mA
-1.08V    52.28mA    35.02mA    69.74mA
-960mV    46.13mA    30.49mA    62.61mA
-720mV    31.73mA    20.2mA     44.61mA
-180mV    6.883mA    4.171mA    10.35mA
60mV      -2.064mA   -1.211mA   -3.207mA
240mV     -7.448mA   -4.352mA   -11.63mA
600mV     -14.77mA   -8.49mA    -23.47mA
900mV     -17.61mA   -9.868mA   -28.71mA
1.26V     -18.59mA   -10.28mA   -30.89mA
3.6V      -20.27mA   -11.2mA    -33.74mA
[GND_clamp]
-1.8V     -597.4mA   -500.9mA   -710mA
-1.16V    -170.9mA   -184.3mA   -163.5mA
-1.12V    -144.6mA   -164.8mA   -129.7mA
-1.08V    -118.4mA   -145.4mA   -95.95mA
-1.04V    -92.22mA   -126mA     -62.27mA
-1V       -66.09mA   -106.6mA   -34.11mA
-960mV    -39.93mA   -87.3mA    -25.33mA
-920mV    -21.05mA   -67.84mA   -21.23mA
-800mV    -8.254mA   -13.78mA   -11.5mA
-680mV    -3.146mA   -2.862mA   -4.259mA
-440mV    -43.6uA    -64.31uA   -34.79uA
1.8V      0A         0A         0A
[POWER_clamp]
-1.8V     367.9mA    313.2mA    432.7mA
-1.16V    136.5mA    139.2mA    137mA
-1.12V    123mA      129mA      119.6mA
-920mV    56.74mA    79.65mA    34.28mA
-880mV    43.81mA    70.18mA    18.86mA
-840mV    30.81mA    60.69mA    13.38mA
-800mV    17.64mA    50.99mA    10.77mA
-760mV    9.019mA    41.18mA    8.633mA
-680mV    4.212mA    21.63mA    4.996mA
-600mV    1.988mA    5.044mA    2.281mA
-480mV    292.3uA    521.1uA    246.1uA
1.8V      0A         0A         0A
[Ramp]
dV/dt_r 0.531/1.418n   0.304/2.503n   0.769/0.794n
dV/dt_f 0.615/1.730n   0.317/2.884n   0.872/0.897n
R_load = 50.000
[Rising Waveform]
R_fixture= 50.000
V_fixture= 1.800
V_fixture_min= 1.620
V_fixture_max= 1.980
0s        775.5mV    1.089V     525.9mV
1.468ns   776mV      1.089V     545.3mV
1.838ns   765.8mV    1.089V     1.796V
2.088ns   738.5mV    1.089V     1.959V
2.319ns   866.2mV    1.089V     1.969V
2.729ns   1.664V     1.089V     1.974V
2.989ns   1.784V     1.085V     1.976V
3.739ns   1.793V     1.076V     1.979V
4.799ns   1.798V     1.609V     1.98V
15ns      1.8V       1.62V      1.98V
[Rising Waveform]
R_fixture= 50.000
V_fixture= 0.0
V_fixture_min= 0.0
V_fixture_max= 0.0
0s        0V         0V         0V
2.037ns   481.1uV    -3.832uV   744.6uV
2.298ns   -6.23mV    -7.279uV   154mV
3.179ns   3.091mV    510.5uV    1.014V
3.508ns   69.13mV    142.4uV    1.166V
3.978ns   268.5mV    -5.932mV   1.242V
5.039ns   673.1mV    -5.288mV   1.277V
6.287ns   842.6mV    73.44mV    1.281V
9.538ns   883.9mV    438.5mV    1.281V
15ns      884.4mV    506mV      1.281V
[Falling Waveform]
R_fixture= 50.000
V_fixture= 1.800
V_fixture_min= 1.620
V_fixture_max= 1.980
0s        1.8V       1.62V      1.98V
1.82ns    1.815V     1.62V      1.96V
2.16ns    1.822V     1.62V      1.718V
3.079ns   1.75V      1.63V      814.8mV
3.399ns   1.657V     1.633V     665.2mV
3.88ns    1.44V      1.629V     584.5mV
5.11ns    1.011V     1.605V     535.2mV
6.539ns   830.4mV    1.441V     527.1mV
9.769ns   777.8mV    1.155V     525.9mV
15ns      775.5mV    1.092V     525.9mV
[Falling Waveform]
R_fixture= 50.000
V_fixture= 0.0
V_fixture_min= 0.0
V_fixture_max= 0.0
0s        884.4mV    507.2mV    1.281V
1.03ns    887mV      506.7mV    1.268V
1.13ns    890.3mV    506.7mV    1.09V
1.399ns   909.9mV    507mV      176.9mV
1.658ns   830.2mV    508.1mV    18.35mV
2.069ns   148.1mV    515mV      6.705mV
2.378ns   13.79mV    527.5mV    3.84mV
2.748ns   6.995mV    493.2mV    2.646mV
3.797ns   3.09mV     8.503mV    663.9uV
15ns      0V         15.32uV    0V
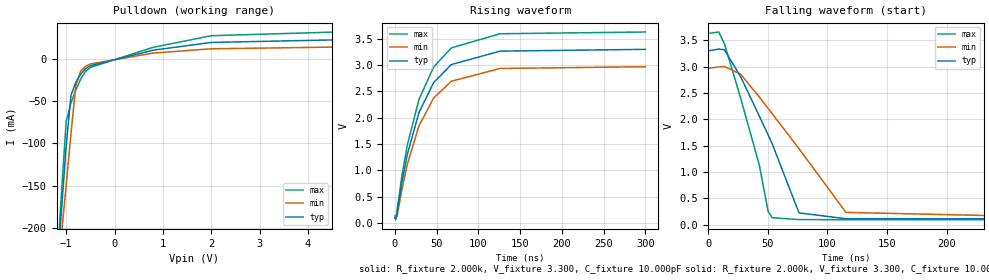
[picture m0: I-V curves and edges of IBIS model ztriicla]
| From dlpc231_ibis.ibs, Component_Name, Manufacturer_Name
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[Model] ztriicla
Model_type I/O_open_drain
Polarity   Non-Inverting
Enable   Active-High
Vmeas =  1.500V
Cref =  10.000pF
Rref =  2.000k
Vref =  3.300V
Vinl =  0.800V
Vinh =  2.000V
C_comp   2.090pF   2.074pF   2.126pF
|C_comp_pullup   45.037fF   NA   93.327fF
|C_comp_pulldown   45.037fF   NA   93.327fF
[Temperature Range]   25.000   0.125k   -40.000
[Voltage Range]   3.300V   2.970V   3.630V
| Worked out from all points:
|   slope of the pulldown table from 0 to 0.495 V, typ, clamps not added: 71.8 ohm
|   rising waveform, R_fixture 2.000k, V_fixture 3.300, C_fixture 10.000pF: 20-80 % time 37.9ns typ, 38.5ns min, 37.3ns max; typ from 0.108 V to 3.3 V
|   falling waveform, R_fixture 2.000k, V_fixture 3.300, C_fixture 10.000pF: 20-80 % time 37.5ns typ, 54.6ns min, 25.6ns max; typ from 3.3 V to 0.108 V
[Pulldown]
|Voltage   I(typ)   I(min)   I(max)
-3.3V     -1.963A    -1.602A    -2.329A
-1.2V     -260mA     -271.7mA   -257.1mA
-1.1V     -181.3mA   -210mA     -160.4mA
-1V       -102.8mA   -149.1mA   -73.77mA
-900mV    -42.71mA   -87.85mA   -51.89mA
-800mV    -27.39mA   -31.22mA   -36.51mA
-700mV    -17.94mA   -14.21mA   -23.68mA
-600mV    -11.45mA   -8.666mA   -14.59mA
-500mV    -7.85mA    -5.802mA   -9.911mA
800mV     10.55mA    7.138mA    13.96mA
2V        19.76mA    12.21mA    27.72mA
6.6V      25.2mA     15.87mA    35.54mA
[Ramp]
| variable   typ   min   max
dV/dt_r   1.915/10.548n   1.699/11.238n   2.123/9.798n
dV/dt_f   1.915/36.729n   1.699/53.528n   2.123/24.952n
R_load = 2.000k
[Rising Waveform]
R_fixture= 2.000k
V_fixture= 3.300
V_fixture_min= 2.970
V_fixture_max= 3.630
C_fixture= 10.000pF
|time   V(typ)   V(min)   V(max)
0s        107.6mV    137.5mV    91.83mV
1.08ns    89.71mV    136mV      64.8mV
2.567ns   172.6mV    126.8mV    234.2mV
8.45ns    774.5mV    637.3mV    902.6mV
14.91ns   1.305V     1.12V      1.484V
28.76ns   2.096V     1.844V     2.345V
46.45ns   2.671V     2.376V     2.965V
67.64ns   3.011V     2.694V     3.328V
126ns     3.266V     2.937V     3.596V
300ns     3.3V       2.97V      3.63V
[Falling Waveform]
R_fixture= 2.000k
V_fixture= 3.300
V_fixture_min= 2.970
V_fixture_max= 3.630
C_fixture= 10.000pF
|time   V(typ)   V(min)   V(max)
0s        3.3V       2.97V      3.63V
8.839ns   3.334V     2.995V     3.66V
13.59ns   3.322V     3.004V     3.44V
27.21ns   2.81V      2.858V     2.405V
42.97ns   2.057V     2.421V     1.123V
50.26ns   1.704V     2.207V     252.2mV
53.63ns   1.539V     2.108V     129.3mV
76.21ns   220.3mV    1.441V     93.54mV
115.6ns   110.7mV    230.2mV    91.9mV
300ns     107.6mV    137.6mV    91.83mV
